VERSION 5.8 ;
BUSBITCHARS "[]" ;
DIVIDERCHAR "/" ;
UNITS
    DATABASE MICRONS 1000 ;
END UNITS

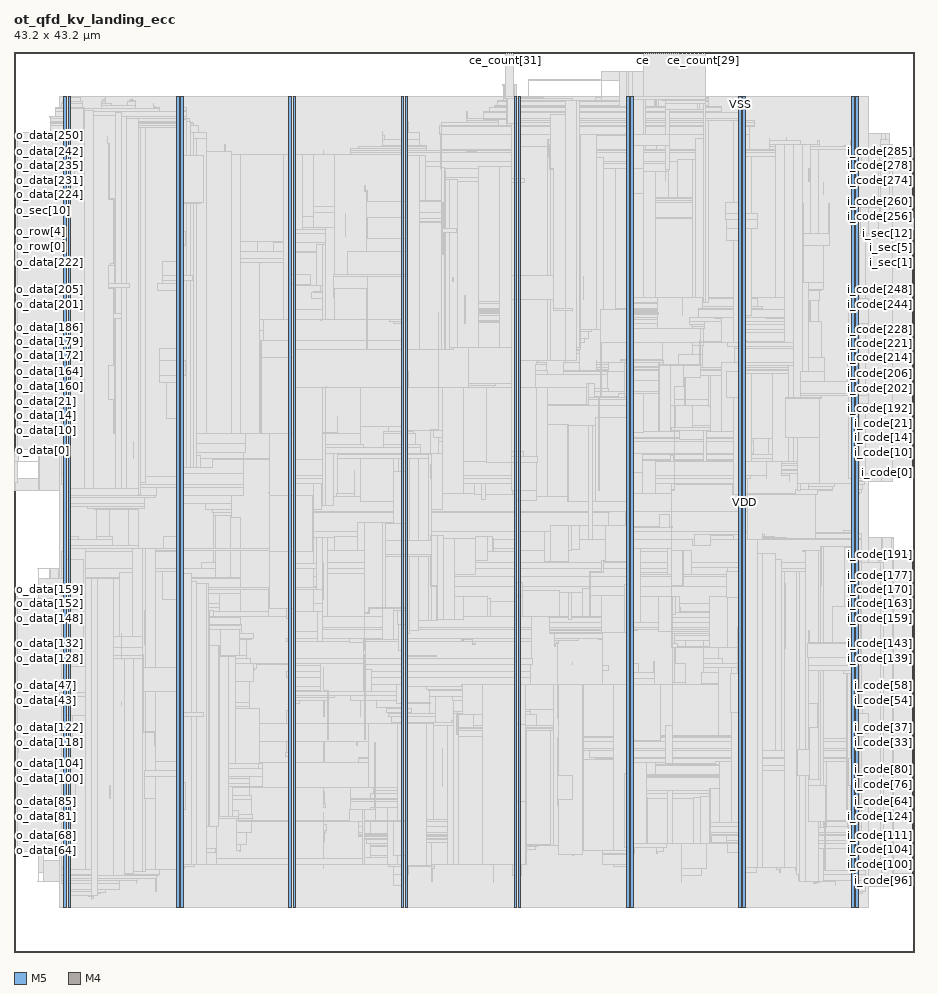
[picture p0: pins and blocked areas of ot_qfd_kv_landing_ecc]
MACRO ot_qfd_kv_landing_ecc
  FOREIGN ot_qfd_kv_landing_ecc 0 0 ;
  CLASS BLOCK ;
  SIZE 43.2 BY 43.2 ;
  PIN ce
    DIRECTION OUTPUT ;
    USE SIGNAL ;
    PORT
      LAYER M5 ;
        RECT  30.192 43.116 30.216 43.2 ;
    END
  END ce
  PIN ce_count[0]
    DIRECTION OUTPUT ;
    USE SIGNAL ;
    PORT
      LAYER M5 ;
        RECT  30.288 43.116 30.312 43.2 ;
    END
  END ce_count[0]
  PIN ce_count[10]
    DIRECTION OUTPUT ;
    USE SIGNAL ;
    PORT
      LAYER M5 ;
        RECT  31.248 43.116 31.272 43.2 ;
    END
  END ce_count[10]
  PIN ce_count[11]
    DIRECTION OUTPUT ;
    USE SIGNAL ;
    PORT
      LAYER M5 ;
        RECT  31.344 43.116 31.368 43.2 ;
    END
  END ce_count[11]
  PIN ce_count[12]
    DIRECTION OUTPUT ;
    USE SIGNAL ;
    PORT
      LAYER M5 ;
        RECT  31.44 43.116 31.464 43.2 ;
    END
  END ce_count[12]
  PIN ce_count[13]
    DIRECTION OUTPUT ;
    USE SIGNAL ;
    PORT
      LAYER M5 ;
        RECT  31.536 43.116 31.56 43.2 ;
    END
  END ce_count[13]
  PIN ce_count[14]
    DIRECTION OUTPUT ;
    USE SIGNAL ;
    PORT
      LAYER M5 ;
        RECT  31.632 43.116 31.656 43.2 ;
    END
  END ce_count[14]
  PIN ce_count[15]
    DIRECTION OUTPUT ;
    USE SIGNAL ;
    PORT
      LAYER M5 ;
        RECT  31.728 43.116 31.752 43.2 ;
    END
  END ce_count[15]
  PIN ce_count[16]
    DIRECTION OUTPUT ;
    USE SIGNAL ;
    PORT
      LAYER M5 ;
        RECT  31.824 43.116 31.848 43.2 ;
    END
  END ce_count[16]
  PIN ce_count[17]
    DIRECTION OUTPUT ;
    USE SIGNAL ;
    PORT
      LAYER M5 ;
        RECT  31.92 43.116 31.944 43.2 ;
    END
  END ce_count[17]
  PIN ce_count[18]
    DIRECTION OUTPUT ;
    USE SIGNAL ;
    PORT
      LAYER M5 ;
        RECT  32.016 43.116 32.04 43.2 ;
    END
  END ce_count[18]
  PIN ce_count[19]
    DIRECTION OUTPUT ;
    USE SIGNAL ;
    PORT
      LAYER M5 ;
        RECT  32.112 43.116 32.136 43.2 ;
    END
  END ce_count[19]
  PIN ce_count[1]
    DIRECTION OUTPUT ;
    USE SIGNAL ;
    PORT
      LAYER M5 ;
        RECT  30.384 43.116 30.408 43.2 ;
    END
  END ce_count[1]
  PIN ce_count[20]
    DIRECTION OUTPUT ;
    USE SIGNAL ;
    PORT
      LAYER M5 ;
        RECT  32.208 43.116 32.232 43.2 ;
    END
  END ce_count[20]
  PIN ce_count[21]
    DIRECTION OUTPUT ;
    USE SIGNAL ;
    PORT
      LAYER M5 ;
        RECT  32.304 43.116 32.328 43.2 ;
    END
  END ce_count[21]
  PIN ce_count[22]
    DIRECTION OUTPUT ;
    USE SIGNAL ;
    PORT
      LAYER M5 ;
        RECT  32.4 43.116 32.424 43.2 ;
    END
  END ce_count[22]
  PIN ce_count[23]
    DIRECTION OUTPUT ;
    USE SIGNAL ;
    PORT
      LAYER M5 ;
        RECT  32.496 43.116 32.52 43.2 ;
    END
  END ce_count[23]
  PIN ce_count[24]
    DIRECTION OUTPUT ;
    USE SIGNAL ;
    PORT
      LAYER M5 ;
        RECT  32.592 43.116 32.616 43.2 ;
    END
  END ce_count[24]
  PIN ce_count[25]
    DIRECTION OUTPUT ;
    USE SIGNAL ;
    PORT
      LAYER M5 ;
        RECT  32.688 43.116 32.712 43.2 ;
    END
  END ce_count[25]
  PIN ce_count[26]
    DIRECTION OUTPUT ;
    USE SIGNAL ;
    PORT
      LAYER M5 ;
        RECT  32.784 43.116 32.808 43.2 ;
    END
  END ce_count[26]
  PIN ce_count[27]
    DIRECTION OUTPUT ;
    USE SIGNAL ;
    PORT
      LAYER M5 ;
        RECT  32.88 43.116 32.904 43.2 ;
    END
  END ce_count[27]
  PIN ce_count[28]
    DIRECTION OUTPUT ;
    USE SIGNAL ;
    PORT
      LAYER M5 ;
        RECT  32.976 43.116 33 43.2 ;
    END
  END ce_count[28]
  PIN ce_count[29]
    DIRECTION OUTPUT ;
    USE SIGNAL ;
    PORT
      LAYER M5 ;
        RECT  33.072 43.116 33.096 43.2 ;
    END
  END ce_count[29]
  PIN ce_count[2]
    DIRECTION OUTPUT ;
    USE SIGNAL ;
    PORT
      LAYER M5 ;
        RECT  30.48 43.116 30.504 43.2 ;
    END
  END ce_count[2]
  PIN ce_count[30]
    DIRECTION OUTPUT ;
    USE SIGNAL ;
    PORT
      LAYER M5 ;
        RECT  33.168 43.116 33.192 43.2 ;
    END
  END ce_count[30]
  PIN ce_count[31]
    DIRECTION OUTPUT ;
    USE SIGNAL ;
    PORT
      LAYER M5 ;
        RECT  23.568 43.116 23.592 43.2 ;
    END
  END ce_count[31]
  PIN ce_count[3]
    DIRECTION OUTPUT ;
    USE SIGNAL ;
    PORT
      LAYER M5 ;
        RECT  30.576 43.116 30.6 43.2 ;
    END
  END ce_count[3]
  PIN ce_count[4]
    DIRECTION OUTPUT ;
    USE SIGNAL ;
    PORT
      LAYER M5 ;
        RECT  30.672 43.116 30.696 43.2 ;
    END
  END ce_count[4]
  PIN ce_count[5]
    DIRECTION OUTPUT ;
    USE SIGNAL ;
    PORT
      LAYER M5 ;
        RECT  30.768 43.116 30.792 43.2 ;
    END
  END ce_count[5]
  PIN ce_count[6]
    DIRECTION OUTPUT ;
    USE SIGNAL ;
    PORT
      LAYER M5 ;
        RECT  30.864 43.116 30.888 43.2 ;
    END
  END ce_count[6]
  PIN ce_count[7]
    DIRECTION OUTPUT ;
    USE SIGNAL ;
    PORT
      LAYER M5 ;
        RECT  30.96 43.116 30.984 43.2 ;
    END
  END ce_count[7]
  PIN ce_count[8]
    DIRECTION OUTPUT ;
    USE SIGNAL ;
    PORT
      LAYER M5 ;
        RECT  31.056 43.116 31.08 43.2 ;
    END
  END ce_count[8]
  PIN ce_count[9]
    DIRECTION OUTPUT ;
    USE SIGNAL ;
    PORT
      LAYER M5 ;
        RECT  31.152 43.116 31.176 43.2 ;
    END
  END ce_count[9]
  PIN fault
    DIRECTION OUTPUT ;
    USE SIGNAL ;
    PORT
      LAYER M5 ;
        RECT  23.664 43.116 23.688 43.2 ;
    END
  END fault
  PIN h_rst_n
    DIRECTION INPUT ;
    USE SIGNAL ;
    PORT
      LAYER M5 ;
        RECT  23.76 43.116 23.784 43.2 ;
    END
  END h_rst_n
  PIN hclk
    DIRECTION INPUT ;
    USE SIGNAL ;
    PORT
      LAYER M5 ;
        RECT  23.856 43.116 23.88 43.2 ;
    END
  END hclk
  PIN i_code[0]
    DIRECTION INPUT ;
    USE SIGNAL ;
    PORT
      LAYER M4 ;
        RECT  43.116 22.992 43.2 23.016 ;
    END
  END i_code[0]
  PIN i_code[100]
    DIRECTION INPUT ;
    USE SIGNAL ;
    PORT
      LAYER M4 ;
        RECT  43.116 4.176 43.2 4.2 ;
    END
  END i_code[100]
  PIN i_code[101]
    DIRECTION INPUT ;
    USE SIGNAL ;
    PORT
      LAYER M4 ;
        RECT  43.116 4.272 43.2 4.296 ;
    END
  END i_code[101]
  PIN i_code[102]
    DIRECTION INPUT ;
    USE SIGNAL ;
    PORT
      LAYER M4 ;
        RECT  43.116 4.368 43.2 4.392 ;
    END
  END i_code[102]
  PIN i_code[103]
    DIRECTION INPUT ;
    USE SIGNAL ;
    PORT
      LAYER M4 ;
        RECT  43.116 4.464 43.2 4.488 ;
    END
  END i_code[103]
  PIN i_code[104]
    DIRECTION INPUT ;
    USE SIGNAL ;
    PORT
      LAYER M4 ;
        RECT  43.116 4.56 43.2 4.584 ;
    END
  END i_code[104]
  PIN i_code[105]
    DIRECTION INPUT ;
    USE SIGNAL ;
    PORT
      LAYER M4 ;
        RECT  43.116 4.656 43.2 4.68 ;
    END
  END i_code[105]
  PIN i_code[106]
    DIRECTION INPUT ;
    USE SIGNAL ;
    PORT
      LAYER M4 ;
        RECT  43.116 4.752 43.2 4.776 ;
    END
  END i_code[106]
  PIN i_code[107]
    DIRECTION INPUT ;
    USE SIGNAL ;
    PORT
      LAYER M4 ;
        RECT  43.116 4.848 43.2 4.872 ;
    END
  END i_code[107]
  PIN i_code[108]
    DIRECTION INPUT ;
    USE SIGNAL ;
    PORT
      LAYER M4 ;
        RECT  43.116 4.944 43.2 4.968 ;
    END
  END i_code[108]
  PIN i_code[109]
    DIRECTION INPUT ;
    USE SIGNAL ;
    PORT
      LAYER M4 ;
        RECT  43.116 5.04 43.2 5.064 ;
    END
  END i_code[109]
  PIN i_code[10]
    DIRECTION INPUT ;
    USE SIGNAL ;
    PORT
      LAYER M4 ;
        RECT  43.116 23.952 43.2 23.976 ;
    END
  END i_code[10]
  PIN i_code[110]
    DIRECTION INPUT ;
    USE SIGNAL ;
    PORT
      LAYER M4 ;
        RECT  43.116 5.136 43.2 5.16 ;
    END
  END i_code[110]
  PIN i_code[111]
    DIRECTION INPUT ;
    USE SIGNAL ;
    PORT
      LAYER M4 ;
        RECT  43.116 5.232 43.2 5.256 ;
    END
  END i_code[111]
  PIN i_code[112]
    DIRECTION INPUT ;
    USE SIGNAL ;
    PORT
      LAYER M4 ;
        RECT  43.116 5.328 43.2 5.352 ;
    END
  END i_code[112]
  PIN i_code[113]
    DIRECTION INPUT ;
    USE SIGNAL ;
    PORT
      LAYER M4 ;
        RECT  43.116 5.424 43.2 5.448 ;
    END
  END i_code[113]
  PIN i_code[114]
    DIRECTION INPUT ;
    USE SIGNAL ;
    PORT
      LAYER M4 ;
        RECT  43.116 5.52 43.2 5.544 ;
    END
  END i_code[114]
  PIN i_code[115]
    DIRECTION INPUT ;
    USE SIGNAL ;
    PORT
      LAYER M4 ;
        RECT  43.116 5.616 43.2 5.64 ;
    END
  END i_code[115]
  PIN i_code[116]
    DIRECTION INPUT ;
    USE SIGNAL ;
    PORT
      LAYER M4 ;
        RECT  43.116 5.712 43.2 5.736 ;
    END
  END i_code[116]
  PIN i_code[117]
    DIRECTION INPUT ;
    USE SIGNAL ;
    PORT
      LAYER M4 ;
        RECT  43.116 5.808 43.2 5.832 ;
    END
  END i_code[117]
  PIN i_code[118]
    DIRECTION INPUT ;
    USE SIGNAL ;
    PORT
      LAYER M4 ;
        RECT  43.116 5.904 43.2 5.928 ;
    END
  END i_code[118]
  PIN i_code[119]
    DIRECTION INPUT ;
    USE SIGNAL ;
    PORT
      LAYER M4 ;
        RECT  43.116 6 43.2 6.024 ;
    END
  END i_code[119]
  PIN i_code[11]
    DIRECTION INPUT ;
    USE SIGNAL ;
    PORT
      LAYER M4 ;
        RECT  43.116 24.048 43.2 24.072 ;
    END
  END i_code[11]
  PIN i_code[120]
    DIRECTION INPUT ;
    USE SIGNAL ;
    PORT
      LAYER M4 ;
        RECT  43.116 6.096 43.2 6.12 ;
    END
  END i_code[120]
  PIN i_code[121]
    DIRECTION INPUT ;
    USE SIGNAL ;
    PORT
      LAYER M4 ;
        RECT  43.116 6.192 43.2 6.216 ;
    END
  END i_code[121]
  PIN i_code[122]
    DIRECTION INPUT ;
    USE SIGNAL ;
    PORT
      LAYER M4 ;
        RECT  43.116 6.288 43.2 6.312 ;
    END
  END i_code[122]
  PIN i_code[123]
    DIRECTION INPUT ;
    USE SIGNAL ;
    PORT
      LAYER M4 ;
        RECT  43.116 6.384 43.2 6.408 ;
    END
  END i_code[123]
  PIN i_code[124]
    DIRECTION INPUT ;
    USE SIGNAL ;
    PORT
      LAYER M4 ;
        RECT  43.116 6.48 43.2 6.504 ;
    END
  END i_code[124]
  PIN i_code[125]
    DIRECTION INPUT ;
    USE SIGNAL ;
    PORT
      LAYER M4 ;
        RECT  43.116 6.576 43.2 6.6 ;
    END
  END i_code[125]
  PIN i_code[126]
    DIRECTION INPUT ;
    USE SIGNAL ;
    PORT
      LAYER M4 ;
        RECT  43.116 6.672 43.2 6.696 ;
    END
  END i_code[126]
  PIN i_code[127]
    DIRECTION INPUT ;
    USE SIGNAL ;
    PORT
      LAYER M4 ;
        RECT  43.116 6.768 43.2 6.792 ;
    END
  END i_code[127]
  PIN i_code[128]
    DIRECTION INPUT ;
    USE SIGNAL ;
    PORT
      LAYER M4 ;
        RECT  43.116 13.008 43.2 13.032 ;
    END
  END i_code[128]
  PIN i_code[129]
    DIRECTION INPUT ;
    USE SIGNAL ;
    PORT
      LAYER M4 ;
        RECT  43.116 13.104 43.2 13.128 ;
    END
  END i_code[129]
  PIN i_code[12]
    DIRECTION INPUT ;
    USE SIGNAL ;
    PORT
      LAYER M4 ;
        RECT  43.116 24.144 43.2 24.168 ;
    END
  END i_code[12]
  PIN i_code[130]
    DIRECTION INPUT ;
    USE SIGNAL ;
    PORT
      LAYER M4 ;
        RECT  43.116 13.2 43.2 13.224 ;
    END
  END i_code[130]
  PIN i_code[131]
    DIRECTION INPUT ;
    USE SIGNAL ;
    PORT
      LAYER M4 ;
        RECT  43.116 13.296 43.2 13.32 ;
    END
  END i_code[131]
  PIN i_code[132]
    DIRECTION INPUT ;
    USE SIGNAL ;
    PORT
      LAYER M4 ;
        RECT  43.116 13.392 43.2 13.416 ;
    END
  END i_code[132]
  PIN i_code[133]
    DIRECTION INPUT ;
    USE SIGNAL ;
    PORT
      LAYER M4 ;
        RECT  43.116 13.488 43.2 13.512 ;
    END
  END i_code[133]
  PIN i_code[134]
    DIRECTION INPUT ;
    USE SIGNAL ;
    PORT
      LAYER M4 ;
        RECT  43.116 13.584 43.2 13.608 ;
    END
  END i_code[134]
  PIN i_code[135]
    DIRECTION INPUT ;
    USE SIGNAL ;
    PORT
      LAYER M4 ;
        RECT  43.116 13.68 43.2 13.704 ;
    END
  END i_code[135]
  PIN i_code[136]
    DIRECTION INPUT ;
    USE SIGNAL ;
    PORT
      LAYER M4 ;
        RECT  43.116 13.776 43.2 13.8 ;
    END
  END i_code[136]
  PIN i_code[137]
    DIRECTION INPUT ;
    USE SIGNAL ;
    PORT
      LAYER M4 ;
        RECT  43.116 13.872 43.2 13.896 ;
    END
  END i_code[137]
  PIN i_code[138]
    DIRECTION INPUT ;
    USE SIGNAL ;
    PORT
      LAYER M4 ;
        RECT  43.116 13.968 43.2 13.992 ;
    END
  END i_code[138]
  PIN i_code[139]
    DIRECTION INPUT ;
    USE SIGNAL ;
    PORT
      LAYER M4 ;
        RECT  43.116 14.064 43.2 14.088 ;
    END
  END i_code[139]
  PIN i_code[13]
    DIRECTION INPUT ;
    USE SIGNAL ;
    PORT
      LAYER M4 ;
        RECT  43.116 24.24 43.2 24.264 ;
    END
  END i_code[13]
  PIN i_code[140]
    DIRECTION INPUT ;
    USE SIGNAL ;
    PORT
      LAYER M4 ;
        RECT  43.116 14.16 43.2 14.184 ;
    END
  END i_code[140]
  PIN i_code[141]
    DIRECTION INPUT ;
    USE SIGNAL ;
    PORT
      LAYER M4 ;
        RECT  43.116 14.256 43.2 14.28 ;
    END
  END i_code[141]
  PIN i_code[142]
    DIRECTION INPUT ;
    USE SIGNAL ;
    PORT
      LAYER M4 ;
        RECT  43.116 14.352 43.2 14.376 ;
    END
  END i_code[142]
  PIN i_code[143]
    DIRECTION INPUT ;
    USE SIGNAL ;
    PORT
      LAYER M4 ;
        RECT  43.116 14.448 43.2 14.472 ;
    END
  END i_code[143]
  PIN i_code[144]
    DIRECTION INPUT ;
    USE SIGNAL ;
    PORT
      LAYER M4 ;
        RECT  43.116 14.544 43.2 14.568 ;
    END
  END i_code[144]
  PIN i_code[145]
    DIRECTION INPUT ;
    USE SIGNAL ;
    PORT
      LAYER M4 ;
        RECT  43.116 14.64 43.2 14.664 ;
    END
  END i_code[145]
  PIN i_code[146]
    DIRECTION INPUT ;
    USE SIGNAL ;
    PORT
      LAYER M4 ;
        RECT  43.116 14.736 43.2 14.76 ;
    END
  END i_code[146]
  PIN i_code[147]
    DIRECTION INPUT ;
    USE SIGNAL ;
    PORT
      LAYER M4 ;
        RECT  43.116 14.832 43.2 14.856 ;
    END
  END i_code[147]
  PIN i_code[148]
    DIRECTION INPUT ;
    USE SIGNAL ;
    PORT
      LAYER M4 ;
        RECT  43.116 14.928 43.2 14.952 ;
    END
  END i_code[148]
  PIN i_code[149]
    DIRECTION INPUT ;
    USE SIGNAL ;
    PORT
      LAYER M4 ;
        RECT  43.116 15.024 43.2 15.048 ;
    END
  END i_code[149]
  PIN i_code[14]
    DIRECTION INPUT ;
    USE SIGNAL ;
    PORT
      LAYER M4 ;
        RECT  43.116 24.336 43.2 24.36 ;
    END
  END i_code[14]
  PIN i_code[150]
    DIRECTION INPUT ;
    USE SIGNAL ;
    PORT
      LAYER M4 ;
        RECT  43.116 15.12 43.2 15.144 ;
    END
  END i_code[150]
  PIN i_code[151]
    DIRECTION INPUT ;
    USE SIGNAL ;
    PORT
      LAYER M4 ;
        RECT  43.116 15.216 43.2 15.24 ;
    END
  END i_code[151]
  PIN i_code[152]
    DIRECTION INPUT ;
    USE SIGNAL ;
    PORT
      LAYER M4 ;
        RECT  43.116 15.312 43.2 15.336 ;
    END
  END i_code[152]
  PIN i_code[153]
    DIRECTION INPUT ;
    USE SIGNAL ;
    PORT
      LAYER M4 ;
        RECT  43.116 15.408 43.2 15.432 ;
    END
  END i_code[153]
  PIN i_code[154]
    DIRECTION INPUT ;
    USE SIGNAL ;
    PORT
      LAYER M4 ;
        RECT  43.116 15.504 43.2 15.528 ;
    END
  END i_code[154]
  PIN i_code[155]
    DIRECTION INPUT ;
    USE SIGNAL ;
    PORT
      LAYER M4 ;
        RECT  43.116 15.6 43.2 15.624 ;
    END
  END i_code[155]
  PIN i_code[156]
    DIRECTION INPUT ;
    USE SIGNAL ;
    PORT
      LAYER M4 ;
        RECT  43.116 15.696 43.2 15.72 ;
    END
  END i_code[156]
  PIN i_code[157]
    DIRECTION INPUT ;
    USE SIGNAL ;
    PORT
      LAYER M4 ;
        RECT  43.116 15.792 43.2 15.816 ;
    END
  END i_code[157]
  PIN i_code[158]
    DIRECTION INPUT ;
    USE SIGNAL ;
    PORT
      LAYER M4 ;
        RECT  43.116 15.888 43.2 15.912 ;
    END
  END i_code[158]
  PIN i_code[159]
    DIRECTION INPUT ;
    USE SIGNAL ;
    PORT
      LAYER M4 ;
        RECT  43.116 15.984 43.2 16.008 ;
    END
  END i_code[159]
  PIN i_code[15]
    DIRECTION INPUT ;
    USE SIGNAL ;
    PORT
      LAYER M4 ;
        RECT  43.116 24.432 43.2 24.456 ;
    END
  END i_code[15]
  PIN i_code[160]
    DIRECTION INPUT ;
    USE SIGNAL ;
    PORT
      LAYER M4 ;
        RECT  43.116 16.08 43.2 16.104 ;
    END
  END i_code[160]
  PIN i_code[161]
    DIRECTION INPUT ;
    USE SIGNAL ;
    PORT
      LAYER M4 ;
        RECT  43.116 16.176 43.2 16.2 ;
    END
  END i_code[161]
  PIN i_code[162]
    DIRECTION INPUT ;
    USE SIGNAL ;
    PORT
      LAYER M4 ;
        RECT  43.116 16.272 43.2 16.296 ;
    END
  END i_code[162]
  PIN i_code[163]
    DIRECTION INPUT ;
    USE SIGNAL ;
    PORT
      LAYER M4 ;
        RECT  43.116 16.368 43.2 16.392 ;
    END
  END i_code[163]
  PIN i_code[164]
    DIRECTION INPUT ;
    USE SIGNAL ;
    PORT
      LAYER M4 ;
        RECT  43.116 16.464 43.2 16.488 ;
    END
  END i_code[164]
  PIN i_code[165]
    DIRECTION INPUT ;
    USE SIGNAL ;
    PORT
      LAYER M4 ;
        RECT  43.116 16.56 43.2 16.584 ;
    END
  END i_code[165]
  PIN i_code[166]
    DIRECTION INPUT ;
    USE SIGNAL ;
    PORT
      LAYER M4 ;
        RECT  43.116 16.656 43.2 16.68 ;
    END
  END i_code[166]
  PIN i_code[167]
    DIRECTION INPUT ;
    USE SIGNAL ;
    PORT
      LAYER M4 ;
        RECT  43.116 16.752 43.2 16.776 ;
    END
  END i_code[167]
  PIN i_code[168]
    DIRECTION INPUT ;
    USE SIGNAL ;
    PORT
      LAYER M4 ;
        RECT  43.116 16.848 43.2 16.872 ;
    END
  END i_code[168]
  PIN i_code[169]
    DIRECTION INPUT ;
    USE SIGNAL ;
    PORT
      LAYER M4 ;
        RECT  43.116 16.944 43.2 16.968 ;
    END
  END i_code[169]
  PIN i_code[16]
    DIRECTION INPUT ;
    USE SIGNAL ;
    PORT
      LAYER M4 ;
        RECT  43.116 24.528 43.2 24.552 ;
    END
  END i_code[16]
  PIN i_code[170]
    DIRECTION INPUT ;
    USE SIGNAL ;
    PORT
      LAYER M4 ;
        RECT  43.116 17.04 43.2 17.064 ;
    END
  END i_code[170]
  PIN i_code[171]
    DIRECTION INPUT ;
    USE SIGNAL ;
    PORT
      LAYER M4 ;
        RECT  43.116 17.136 43.2 17.16 ;
    END
  END i_code[171]
  PIN i_code[172]
    DIRECTION INPUT ;
    USE SIGNAL ;
    PORT
      LAYER M4 ;
        RECT  43.116 17.232 43.2 17.256 ;
    END
  END i_code[172]
  PIN i_code[173]
    DIRECTION INPUT ;
    USE SIGNAL ;
    PORT
      LAYER M4 ;
        RECT  43.116 17.328 43.2 17.352 ;
    END
  END i_code[173]
  PIN i_code[174]
    DIRECTION INPUT ;
    USE SIGNAL ;
    PORT
      LAYER M4 ;
        RECT  43.116 17.424 43.2 17.448 ;
    END
  END i_code[174]
  PIN i_code[175]
    DIRECTION INPUT ;
    USE SIGNAL ;
    PORT
      LAYER M4 ;
        RECT  43.116 17.52 43.2 17.544 ;
    END
  END i_code[175]
  PIN i_code[176]
    DIRECTION INPUT ;
    USE SIGNAL ;
    PORT
      LAYER M4 ;
        RECT  43.116 17.616 43.2 17.64 ;
    END
  END i_code[176]
  PIN i_code[177]
    DIRECTION INPUT ;
    USE SIGNAL ;
    PORT
      LAYER M4 ;
        RECT  43.116 17.712 43.2 17.736 ;
    END
  END i_code[177]
  PIN i_code[178]
    DIRECTION INPUT ;
    USE SIGNAL ;
    PORT
      LAYER M4 ;
        RECT  43.116 17.808 43.2 17.832 ;
    END
  END i_code[178]
  PIN i_code[179]
    DIRECTION INPUT ;
    USE SIGNAL ;
    PORT
      LAYER M4 ;
        RECT  43.116 17.904 43.2 17.928 ;
    END
  END i_code[179]
  PIN i_code[17]
    DIRECTION INPUT ;
    USE SIGNAL ;
    PORT
      LAYER M4 ;
        RECT  43.116 24.624 43.2 24.648 ;
    END
  END i_code[17]
  PIN i_code[180]
    DIRECTION INPUT ;
    USE SIGNAL ;
    PORT
      LAYER M4 ;
        RECT  43.116 18 43.2 18.024 ;
    END
  END i_code[180]
  PIN i_code[181]
    DIRECTION INPUT ;
    USE SIGNAL ;
    PORT
      LAYER M4 ;
        RECT  43.116 18.096 43.2 18.12 ;
    END
  END i_code[181]
  PIN i_code[182]
    DIRECTION INPUT ;
    USE SIGNAL ;
    PORT
      LAYER M4 ;
        RECT  43.116 18.192 43.2 18.216 ;
    END
  END i_code[182]
  PIN i_code[183]
    DIRECTION INPUT ;
    USE SIGNAL ;
    PORT
      LAYER M4 ;
        RECT  43.116 18.288 43.2 18.312 ;
    END
  END i_code[183]
  PIN i_code[184]
    DIRECTION INPUT ;
    USE SIGNAL ;
    PORT
      LAYER M4 ;
        RECT  43.116 18.384 43.2 18.408 ;
    END
  END i_code[184]
  PIN i_code[185]
    DIRECTION INPUT ;
    USE SIGNAL ;
    PORT
      LAYER M4 ;
        RECT  43.116 18.48 43.2 18.504 ;
    END
  END i_code[185]
  PIN i_code[186]
    DIRECTION INPUT ;
    USE SIGNAL ;
    PORT
      LAYER M4 ;
        RECT  43.116 18.576 43.2 18.6 ;
    END
  END i_code[186]
  PIN i_code[187]
    DIRECTION INPUT ;
    USE SIGNAL ;
    PORT
      LAYER M4 ;
        RECT  43.116 18.672 43.2 18.696 ;
    END
  END i_code[187]
  PIN i_code[188]
    DIRECTION INPUT ;
    USE SIGNAL ;
    PORT
      LAYER M4 ;
        RECT  43.116 18.768 43.2 18.792 ;
    END
  END i_code[188]
  PIN i_code[189]
    DIRECTION INPUT ;
    USE SIGNAL ;
    PORT
      LAYER M4 ;
        RECT  43.116 18.864 43.2 18.888 ;
    END
  END i_code[189]
  PIN i_code[18]
    DIRECTION INPUT ;
    USE SIGNAL ;
    PORT
      LAYER M4 ;
        RECT  43.116 24.72 43.2 24.744 ;
    END
  END i_code[18]
  PIN i_code[190]
    DIRECTION INPUT ;
    USE SIGNAL ;
    PORT
      LAYER M4 ;
        RECT  43.116 18.96 43.2 18.984 ;
    END
  END i_code[190]
  PIN i_code[191]
    DIRECTION INPUT ;
    USE SIGNAL ;
    PORT
      LAYER M4 ;
        RECT  43.116 19.056 43.2 19.08 ;
    END
  END i_code[191]
  PIN i_code[192]
    DIRECTION INPUT ;
    USE SIGNAL ;
    PORT
      LAYER M4 ;
        RECT  43.116 26.064 43.2 26.088 ;
    END
  END i_code[192]
  PIN i_code[193]
    DIRECTION INPUT ;
    USE SIGNAL ;
    PORT
      LAYER M4 ;
        RECT  43.116 26.16 43.2 26.184 ;
    END
  END i_code[193]
  PIN i_code[194]
    DIRECTION INPUT ;
    USE SIGNAL ;
    PORT
      LAYER M4 ;
        RECT  43.116 26.256 43.2 26.28 ;
    END
  END i_code[194]
  PIN i_code[195]
    DIRECTION INPUT ;
    USE SIGNAL ;
    PORT
      LAYER M4 ;
        RECT  43.116 26.352 43.2 26.376 ;
    END
  END i_code[195]
  PIN i_code[196]
    DIRECTION INPUT ;
    USE SIGNAL ;
    PORT
      LAYER M4 ;
        RECT  43.116 26.448 43.2 26.472 ;
    END
  END i_code[196]
  PIN i_code[197]
    DIRECTION INPUT ;
    USE SIGNAL ;
    PORT
      LAYER M4 ;
        RECT  43.116 26.544 43.2 26.568 ;
    END
  END i_code[197]
  PIN i_code[198]
    DIRECTION INPUT ;
    USE SIGNAL ;
    PORT
      LAYER M4 ;
        RECT  43.116 26.64 43.2 26.664 ;
    END
  END i_code[198]
  PIN i_code[199]
    DIRECTION INPUT ;
    USE SIGNAL ;
    PORT
      LAYER M4 ;
        RECT  43.116 26.736 43.2 26.76 ;
    END
  END i_code[199]
  PIN i_code[19]
    DIRECTION INPUT ;
    USE SIGNAL ;
    PORT
      LAYER M4 ;
        RECT  43.116 24.816 43.2 24.84 ;
    END
  END i_code[19]
  PIN i_code[1]
    DIRECTION INPUT ;
    USE SIGNAL ;
    PORT
      LAYER M4 ;
        RECT  43.116 23.088 43.2 23.112 ;
    END
  END i_code[1]
  PIN i_code[200]
    DIRECTION INPUT ;
    USE SIGNAL ;
    PORT
      LAYER M4 ;
        RECT  43.116 26.832 43.2 26.856 ;
    END
  END i_code[200]
  PIN i_code[201]
    DIRECTION INPUT ;
    USE SIGNAL ;
    PORT
      LAYER M4 ;
        RECT  43.116 26.928 43.2 26.952 ;
    END
  END i_code[201]
  PIN i_code[202]
    DIRECTION INPUT ;
    USE SIGNAL ;
    PORT
      LAYER M4 ;
        RECT  43.116 27.024 43.2 27.048 ;
    END
  END i_code[202]
  PIN i_code[203]
    DIRECTION INPUT ;
    USE SIGNAL ;
    PORT
      LAYER M4 ;
        RECT  43.116 27.12 43.2 27.144 ;
    END
  END i_code[203]
  PIN i_code[204]
    DIRECTION INPUT ;
    USE SIGNAL ;
    PORT
      LAYER M4 ;
        RECT  43.116 27.216 43.2 27.24 ;
    END
  END i_code[204]
  PIN i_code[205]
    DIRECTION INPUT ;
    USE SIGNAL ;
    PORT
      LAYER M4 ;
        RECT  43.116 27.312 43.2 27.336 ;
    END
  END i_code[205]
  PIN i_code[206]
    DIRECTION INPUT ;
    USE SIGNAL ;
    PORT
      LAYER M4 ;
        RECT  43.116 27.408 43.2 27.432 ;
    END
  END i_code[206]
  PIN i_code[207]
    DIRECTION INPUT ;
    USE SIGNAL ;
    PORT
      LAYER M4 ;
        RECT  43.116 27.504 43.2 27.528 ;
    END
  END i_code[207]
  PIN i_code[208]
    DIRECTION INPUT ;
    USE SIGNAL ;
    PORT
      LAYER M4 ;
        RECT  43.116 27.6 43.2 27.624 ;
    END
  END i_code[208]
  PIN i_code[209]
    DIRECTION INPUT ;
    USE SIGNAL ;
    PORT
      LAYER M4 ;
        RECT  43.116 27.696 43.2 27.72 ;
    END
  END i_code[209]
  PIN i_code[20]
    DIRECTION INPUT ;
    USE SIGNAL ;
    PORT
      LAYER M4 ;
        RECT  43.116 24.912 43.2 24.936 ;
    END
  END i_code[20]
  PIN i_code[210]
    DIRECTION INPUT ;
    USE SIGNAL ;
    PORT
      LAYER M4 ;
        RECT  43.116 27.792 43.2 27.816 ;
    END
  END i_code[210]
  PIN i_code[211]
    DIRECTION INPUT ;
    USE SIGNAL ;
    PORT
      LAYER M4 ;
        RECT  43.116 27.888 43.2 27.912 ;
    END
  END i_code[211]
  PIN i_code[212]
    DIRECTION INPUT ;
    USE SIGNAL ;
    PORT
      LAYER M4 ;
        RECT  43.116 27.984 43.2 28.008 ;
    END
  END i_code[212]
  PIN i_code[213]
    DIRECTION INPUT ;
    USE SIGNAL ;
    PORT
      LAYER M4 ;
        RECT  43.116 28.08 43.2 28.104 ;
    END
  END i_code[213]
  PIN i_code[214]
    DIRECTION INPUT ;
    USE SIGNAL ;
    PORT
      LAYER M4 ;
        RECT  43.116 28.176 43.2 28.2 ;
    END
  END i_code[214]
  PIN i_code[215]
    DIRECTION INPUT ;
    USE SIGNAL ;
    PORT
      LAYER M4 ;
        RECT  43.116 28.272 43.2 28.296 ;
    END
  END i_code[215]
  PIN i_code[216]
    DIRECTION INPUT ;
    USE SIGNAL ;
    PORT
      LAYER M4 ;
        RECT  43.116 28.368 43.2 28.392 ;
    END
  END i_code[216]
  PIN i_code[217]
    DIRECTION INPUT ;
    USE SIGNAL ;
    PORT
      LAYER M4 ;
        RECT  43.116 28.464 43.2 28.488 ;
    END
  END i_code[217]
  PIN i_code[218]
    DIRECTION INPUT ;
    USE SIGNAL ;
    PORT
      LAYER M4 ;
        RECT  43.116 28.56 43.2 28.584 ;
    END
  END i_code[218]
  PIN i_code[219]
    DIRECTION INPUT ;
    USE SIGNAL ;
    PORT
      LAYER M4 ;
        RECT  43.116 28.656 43.2 28.68 ;
    END
  END i_code[219]
  PIN i_code[21]
    DIRECTION INPUT ;
    USE SIGNAL ;
    PORT
      LAYER M4 ;
        RECT  43.116 25.008 43.2 25.032 ;
    END
  END i_code[21]
  PIN i_code[220]
    DIRECTION INPUT ;
    USE SIGNAL ;
    PORT
      LAYER M4 ;
        RECT  43.116 28.752 43.2 28.776 ;
    END
  END i_code[220]
  PIN i_code[221]
    DIRECTION INPUT ;
    USE SIGNAL ;
    PORT
      LAYER M4 ;
        RECT  43.116 28.848 43.2 28.872 ;
    END
  END i_code[221]
  PIN i_code[222]
    DIRECTION INPUT ;
    USE SIGNAL ;
    PORT
      LAYER M4 ;
        RECT  43.116 28.944 43.2 28.968 ;
    END
  END i_code[222]
  PIN i_code[223]
    DIRECTION INPUT ;
    USE SIGNAL ;
    PORT
      LAYER M4 ;
        RECT  43.116 29.04 43.2 29.064 ;
    END
  END i_code[223]
  PIN i_code[224]
    DIRECTION INPUT ;
    USE SIGNAL ;
    PORT
      LAYER M4 ;
        RECT  43.116 29.136 43.2 29.16 ;
    END
  END i_code[224]
  PIN i_code[225]
    DIRECTION INPUT ;
    USE SIGNAL ;
    PORT
      LAYER M4 ;
        RECT  43.116 29.232 43.2 29.256 ;
    END
  END i_code[225]
  PIN i_code[226]
    DIRECTION INPUT ;
    USE SIGNAL ;
    PORT
      LAYER M4 ;
        RECT  43.116 29.328 43.2 29.352 ;
    END
  END i_code[226]
  PIN i_code[227]
    DIRECTION INPUT ;
    USE SIGNAL ;
    PORT
      LAYER M4 ;
        RECT  43.116 29.424 43.2 29.448 ;
    END
  END i_code[227]
  PIN i_code[228]
    DIRECTION INPUT ;
    USE SIGNAL ;
    PORT
      LAYER M4 ;
        RECT  43.116 29.52 43.2 29.544 ;
    END
  END i_code[228]
  PIN i_code[229]
    DIRECTION INPUT ;
    USE SIGNAL ;
    PORT
      LAYER M4 ;
        RECT  43.116 29.616 43.2 29.64 ;
    END
  END i_code[229]
  PIN i_code[22]
    DIRECTION INPUT ;
    USE SIGNAL ;
    PORT
      LAYER M4 ;
        RECT  43.116 25.104 43.2 25.128 ;
    END
  END i_code[22]
  PIN i_code[230]
    DIRECTION INPUT ;
    USE SIGNAL ;
    PORT
      LAYER M4 ;
        RECT  43.116 29.712 43.2 29.736 ;
    END
  END i_code[230]
  PIN i_code[231]
    DIRECTION INPUT ;
    USE SIGNAL ;
    PORT
      LAYER M4 ;
        RECT  43.116 29.808 43.2 29.832 ;
    END
  END i_code[231]
  PIN i_code[232]
    DIRECTION INPUT ;
    USE SIGNAL ;
    PORT
      LAYER M4 ;
        RECT  43.116 29.904 43.2 29.928 ;
    END
  END i_code[232]
  PIN i_code[233]
    DIRECTION INPUT ;
    USE SIGNAL ;
    PORT
      LAYER M4 ;
        RECT  43.116 30 43.2 30.024 ;
    END
  END i_code[233]
  PIN i_code[234]
    DIRECTION INPUT ;
    USE SIGNAL ;
    PORT
      LAYER M4 ;
        RECT  43.116 30.096 43.2 30.12 ;
    END
  END i_code[234]
  PIN i_code[235]
    DIRECTION INPUT ;
    USE SIGNAL ;
    PORT
      LAYER M4 ;
        RECT  43.116 30.192 43.2 30.216 ;
    END
  END i_code[235]
  PIN i_code[236]
    DIRECTION INPUT ;
    USE SIGNAL ;
    PORT
      LAYER M4 ;
        RECT  43.116 30.288 43.2 30.312 ;
    END
  END i_code[236]
  PIN i_code[237]
    DIRECTION INPUT ;
    USE SIGNAL ;
    PORT
      LAYER M4 ;
        RECT  43.116 30.384 43.2 30.408 ;
    END
  END i_code[237]
  PIN i_code[238]
    DIRECTION INPUT ;
    USE SIGNAL ;
    PORT
      LAYER M4 ;
        RECT  43.116 30.48 43.2 30.504 ;
    END
  END i_code[238]
  PIN i_code[239]
    DIRECTION INPUT ;
    USE SIGNAL ;
    PORT
      LAYER M4 ;
        RECT  43.116 30.576 43.2 30.6 ;
    END
  END i_code[239]
  PIN i_code[23]
    DIRECTION INPUT ;
    USE SIGNAL ;
    PORT
      LAYER M4 ;
        RECT  43.116 25.2 43.2 25.224 ;
    END
  END i_code[23]
  PIN i_code[240]
    DIRECTION INPUT ;
    USE SIGNAL ;
    PORT
      LAYER M4 ;
        RECT  43.116 30.672 43.2 30.696 ;
    END
  END i_code[240]
  PIN i_code[241]
    DIRECTION INPUT ;
    USE SIGNAL ;
    PORT
      LAYER M4 ;
        RECT  43.116 30.768 43.2 30.792 ;
    END
  END i_code[241]
  PIN i_code[242]
    DIRECTION INPUT ;
    USE SIGNAL ;
    PORT
      LAYER M4 ;
        RECT  43.116 30.864 43.2 30.888 ;
    END
  END i_code[242]
  PIN i_code[243]
    DIRECTION INPUT ;
    USE SIGNAL ;
    PORT
      LAYER M4 ;
        RECT  43.116 30.96 43.2 30.984 ;
    END
  END i_code[243]
  PIN i_code[244]
    DIRECTION INPUT ;
    USE SIGNAL ;
    PORT
      LAYER M4 ;
        RECT  43.116 31.056 43.2 31.08 ;
    END
  END i_code[244]
  PIN i_code[245]
    DIRECTION INPUT ;
    USE SIGNAL ;
    PORT
      LAYER M4 ;
        RECT  43.116 31.152 43.2 31.176 ;
    END
  END i_code[245]
  PIN i_code[246]
    DIRECTION INPUT ;
    USE SIGNAL ;
    PORT
      LAYER M4 ;
        RECT  43.116 31.248 43.2 31.272 ;
    END
  END i_code[246]
  PIN i_code[247]
    DIRECTION INPUT ;
    USE SIGNAL ;
    PORT
      LAYER M4 ;
        RECT  43.116 31.344 43.2 31.368 ;
    END
  END i_code[247]
  PIN i_code[248]
    DIRECTION INPUT ;
    USE SIGNAL ;
    PORT
      LAYER M4 ;
        RECT  43.116 31.44 43.2 31.464 ;
    END
  END i_code[248]
  PIN i_code[249]
    DIRECTION INPUT ;
    USE SIGNAL ;
    PORT
      LAYER M4 ;
        RECT  43.116 31.536 43.2 31.56 ;
    END
  END i_code[249]
  PIN i_code[24]
    DIRECTION INPUT ;
    USE SIGNAL ;
    PORT
      LAYER M4 ;
        RECT  43.116 25.296 43.2 25.32 ;
    END
  END i_code[24]
  PIN i_code[250]
    DIRECTION INPUT ;
    USE SIGNAL ;
    PORT
      LAYER M4 ;
        RECT  43.116 31.632 43.2 31.656 ;
    END
  END i_code[250]
  PIN i_code[251]
    DIRECTION INPUT ;
    USE SIGNAL ;
    PORT
      LAYER M4 ;
        RECT  43.116 31.728 43.2 31.752 ;
    END
  END i_code[251]
  PIN i_code[252]
    DIRECTION INPUT ;
    USE SIGNAL ;
    PORT
      LAYER M4 ;
        RECT  43.116 31.824 43.2 31.848 ;
    END
  END i_code[252]
  PIN i_code[253]
    DIRECTION INPUT ;
    USE SIGNAL ;
    PORT
      LAYER M4 ;
        RECT  43.116 31.92 43.2 31.944 ;
    END
  END i_code[253]
  PIN i_code[254]
    DIRECTION INPUT ;
    USE SIGNAL ;
    PORT
      LAYER M4 ;
        RECT  43.116 32.016 43.2 32.04 ;
    END
  END i_code[254]
  PIN i_code[255]
    DIRECTION INPUT ;
    USE SIGNAL ;
    PORT
      LAYER M4 ;
        RECT  43.116 32.112 43.2 32.136 ;
    END
  END i_code[255]
  PIN i_code[256]
    DIRECTION INPUT ;
    USE SIGNAL ;
    PORT
      LAYER M4 ;
        RECT  43.116 35.28 43.2 35.304 ;
    END
  END i_code[256]
  PIN i_code[257]
    DIRECTION INPUT ;
    USE SIGNAL ;
    PORT
      LAYER M4 ;
        RECT  43.116 35.376 43.2 35.4 ;
    END
  END i_code[257]
  PIN i_code[258]
    DIRECTION INPUT ;
    USE SIGNAL ;
    PORT
      LAYER M4 ;
        RECT  43.116 35.472 43.2 35.496 ;
    END
  END i_code[258]
  PIN i_code[259]
    DIRECTION INPUT ;
    USE SIGNAL ;
    PORT
      LAYER M4 ;
        RECT  43.116 35.568 43.2 35.592 ;
    END
  END i_code[259]
  PIN i_code[25]
    DIRECTION INPUT ;
    USE SIGNAL ;
    PORT
      LAYER M4 ;
        RECT  43.116 25.392 43.2 25.416 ;
    END
  END i_code[25]
  PIN i_code[260]
    DIRECTION INPUT ;
    USE SIGNAL ;
    PORT
      LAYER M4 ;
        RECT  43.116 35.664 43.2 35.688 ;
    END
  END i_code[260]
  PIN i_code[261]
    DIRECTION INPUT ;
    USE SIGNAL ;
    PORT
      LAYER M4 ;
        RECT  43.116 35.76 43.2 35.784 ;
    END
  END i_code[261]
  PIN i_code[262]
    DIRECTION INPUT ;
    USE SIGNAL ;
    PORT
      LAYER M4 ;
        RECT  43.116 35.856 43.2 35.88 ;
    END
  END i_code[262]
  PIN i_code[263]
    DIRECTION INPUT ;
    USE SIGNAL ;
    PORT
      LAYER M4 ;
        RECT  43.116 35.952 43.2 35.976 ;
    END
  END i_code[263]
  PIN i_code[264]
    DIRECTION INPUT ;
    USE SIGNAL ;
    PORT
      LAYER M4 ;
        RECT  43.116 36.048 43.2 36.072 ;
    END
  END i_code[264]
  PIN i_code[265]
    DIRECTION INPUT ;
    USE SIGNAL ;
    PORT
      LAYER M4 ;
        RECT  43.116 36.144 43.2 36.168 ;
    END
  END i_code[265]
  PIN i_code[266]
    DIRECTION INPUT ;
    USE SIGNAL ;
    PORT
      LAYER M4 ;
        RECT  43.116 36.24 43.2 36.264 ;
    END
  END i_code[266]
  PIN i_code[267]
    DIRECTION INPUT ;
    USE SIGNAL ;
    PORT
      LAYER M4 ;
        RECT  43.116 36.336 43.2 36.36 ;
    END
  END i_code[267]
  PIN i_code[268]
    DIRECTION INPUT ;
    USE SIGNAL ;
    PORT
      LAYER M4 ;
        RECT  43.116 36.432 43.2 36.456 ;
    END
  END i_code[268]
  PIN i_code[269]
    DIRECTION INPUT ;
    USE SIGNAL ;
    PORT
      LAYER M4 ;
        RECT  43.116 36.528 43.2 36.552 ;
    END
  END i_code[269]
  PIN i_code[26]
    DIRECTION INPUT ;
    USE SIGNAL ;
    PORT
      LAYER M4 ;
        RECT  43.116 25.488 43.2 25.512 ;
    END
  END i_code[26]
  PIN i_code[270]
    DIRECTION INPUT ;
    USE SIGNAL ;
    PORT
      LAYER M4 ;
        RECT  43.116 36.624 43.2 36.648 ;
    END
  END i_code[270]
  PIN i_code[271]
    DIRECTION INPUT ;
    USE SIGNAL ;
    PORT
      LAYER M4 ;
        RECT  43.116 36.72 43.2 36.744 ;
    END
  END i_code[271]
  PIN i_code[272]
    DIRECTION INPUT ;
    USE SIGNAL ;
    PORT
      LAYER M4 ;
        RECT  43.116 36.816 43.2 36.84 ;
    END
  END i_code[272]
  PIN i_code[273]
    DIRECTION INPUT ;
    USE SIGNAL ;
    PORT
      LAYER M4 ;
        RECT  43.116 36.912 43.2 36.936 ;
    END
  END i_code[273]
  PIN i_code[274]
    DIRECTION INPUT ;
    USE SIGNAL ;
    PORT
      LAYER M4 ;
        RECT  43.116 37.008 43.2 37.032 ;
    END
  END i_code[274]
  PIN i_code[275]
    DIRECTION INPUT ;
    USE SIGNAL ;
    PORT
      LAYER M4 ;
        RECT  43.116 37.104 43.2 37.128 ;
    END
  END i_code[275]
  PIN i_code[276]
    DIRECTION INPUT ;
    USE SIGNAL ;
    PORT
      LAYER M4 ;
        RECT  43.116 37.2 43.2 37.224 ;
    END
  END i_code[276]
  PIN i_code[277]
    DIRECTION INPUT ;
    USE SIGNAL ;
    PORT
      LAYER M4 ;
        RECT  43.116 37.296 43.2 37.32 ;
    END
  END i_code[277]
  PIN i_code[278]
    DIRECTION INPUT ;
    USE SIGNAL ;
    PORT
      LAYER M4 ;
        RECT  43.116 37.392 43.2 37.416 ;
    END
  END i_code[278]
  PIN i_code[279]
    DIRECTION INPUT ;
    USE SIGNAL ;
    PORT
      LAYER M4 ;
        RECT  43.116 37.488 43.2 37.512 ;
    END
  END i_code[279]
  PIN i_code[27]
    DIRECTION INPUT ;
    USE SIGNAL ;
    PORT
      LAYER M4 ;
        RECT  43.116 25.584 43.2 25.608 ;
    END
  END i_code[27]
  PIN i_code[280]
    DIRECTION INPUT ;
    USE SIGNAL ;
    PORT
      LAYER M4 ;
        RECT  43.116 37.584 43.2 37.608 ;
    END
  END i_code[280]
  PIN i_code[281]
    DIRECTION INPUT ;
    USE SIGNAL ;
    PORT
      LAYER M4 ;
        RECT  43.116 37.68 43.2 37.704 ;
    END
  END i_code[281]
  PIN i_code[282]
    DIRECTION INPUT ;
    USE SIGNAL ;
    PORT
      LAYER M4 ;
        RECT  43.116 37.776 43.2 37.8 ;
    END
  END i_code[282]
  PIN i_code[283]
    DIRECTION INPUT ;
    USE SIGNAL ;
    PORT
      LAYER M4 ;
        RECT  43.116 37.872 43.2 37.896 ;
    END
  END i_code[283]
  PIN i_code[284]
    DIRECTION INPUT ;
    USE SIGNAL ;
    PORT
      LAYER M4 ;
        RECT  43.116 37.968 43.2 37.992 ;
    END
  END i_code[284]
  PIN i_code[285]
    DIRECTION INPUT ;
    USE SIGNAL ;
    PORT
      LAYER M4 ;
        RECT  43.116 38.064 43.2 38.088 ;
    END
  END i_code[285]
  PIN i_code[286]
    DIRECTION INPUT ;
    USE SIGNAL ;
    PORT
      LAYER M4 ;
        RECT  43.116 38.16 43.2 38.184 ;
    END
  END i_code[286]
  PIN i_code[287]
    DIRECTION INPUT ;
    USE SIGNAL ;
    PORT
      LAYER M4 ;
        RECT  43.116 38.256 43.2 38.28 ;
    END
  END i_code[287]
  PIN i_code[28]
    DIRECTION INPUT ;
    USE SIGNAL ;
    PORT
      LAYER M4 ;
        RECT  43.116 25.68 43.2 25.704 ;
    END
  END i_code[28]
  PIN i_code[29]
    DIRECTION INPUT ;
    USE SIGNAL ;
    PORT
      LAYER M4 ;
        RECT  43.116 25.776 43.2 25.8 ;
    END
  END i_code[29]
  PIN i_code[2]
    DIRECTION INPUT ;
    USE SIGNAL ;
    PORT
      LAYER M4 ;
        RECT  43.116 23.184 43.2 23.208 ;
    END
  END i_code[2]
  PIN i_code[30]
    DIRECTION INPUT ;
    USE SIGNAL ;
    PORT
      LAYER M4 ;
        RECT  43.116 25.872 43.2 25.896 ;
    END
  END i_code[30]
  PIN i_code[31]
    DIRECTION INPUT ;
    USE SIGNAL ;
    PORT
      LAYER M4 ;
        RECT  43.116 25.968 43.2 25.992 ;
    END
  END i_code[31]
  PIN i_code[32]
    DIRECTION INPUT ;
    USE SIGNAL ;
    PORT
      LAYER M4 ;
        RECT  43.116 9.936 43.2 9.96 ;
    END
  END i_code[32]
  PIN i_code[33]
    DIRECTION INPUT ;
    USE SIGNAL ;
    PORT
      LAYER M4 ;
        RECT  43.116 10.032 43.2 10.056 ;
    END
  END i_code[33]
  PIN i_code[34]
    DIRECTION INPUT ;
    USE SIGNAL ;
    PORT
      LAYER M4 ;
        RECT  43.116 10.128 43.2 10.152 ;
    END
  END i_code[34]
  PIN i_code[35]
    DIRECTION INPUT ;
    USE SIGNAL ;
    PORT
      LAYER M4 ;
        RECT  43.116 10.224 43.2 10.248 ;
    END
  END i_code[35]
  PIN i_code[36]
    DIRECTION INPUT ;
    USE SIGNAL ;
    PORT
      LAYER M4 ;
        RECT  43.116 10.32 43.2 10.344 ;
    END
  END i_code[36]
  PIN i_code[37]
    DIRECTION INPUT ;
    USE SIGNAL ;
    PORT
      LAYER M4 ;
        RECT  43.116 10.416 43.2 10.44 ;
    END
  END i_code[37]
  PIN i_code[38]
    DIRECTION INPUT ;
    USE SIGNAL ;
    PORT
      LAYER M4 ;
        RECT  43.116 10.512 43.2 10.536 ;
    END
  END i_code[38]
  PIN i_code[39]
    DIRECTION INPUT ;
    USE SIGNAL ;
    PORT
      LAYER M4 ;
        RECT  43.116 10.608 43.2 10.632 ;
    END
  END i_code[39]
  PIN i_code[3]
    DIRECTION INPUT ;
    USE SIGNAL ;
    PORT
      LAYER M4 ;
        RECT  43.116 23.28 43.2 23.304 ;
    END
  END i_code[3]
  PIN i_code[40]
    DIRECTION INPUT ;
    USE SIGNAL ;
    PORT
      LAYER M4 ;
        RECT  43.116 10.704 43.2 10.728 ;
    END
  END i_code[40]
  PIN i_code[41]
    DIRECTION INPUT ;
    USE SIGNAL ;
    PORT
      LAYER M4 ;
        RECT  43.116 10.8 43.2 10.824 ;
    END
  END i_code[41]
  PIN i_code[42]
    DIRECTION INPUT ;
    USE SIGNAL ;
    PORT
      LAYER M4 ;
        RECT  43.116 10.896 43.2 10.92 ;
    END
  END i_code[42]
  PIN i_code[43]
    DIRECTION INPUT ;
    USE SIGNAL ;
    PORT
      LAYER M4 ;
        RECT  43.116 10.992 43.2 11.016 ;
    END
  END i_code[43]
  PIN i_code[44]
    DIRECTION INPUT ;
    USE SIGNAL ;
    PORT
      LAYER M4 ;
        RECT  43.116 11.088 43.2 11.112 ;
    END
  END i_code[44]
  PIN i_code[45]
    DIRECTION INPUT ;
    USE SIGNAL ;
    PORT
      LAYER M4 ;
        RECT  43.116 11.184 43.2 11.208 ;
    END
  END i_code[45]
  PIN i_code[46]
    DIRECTION INPUT ;
    USE SIGNAL ;
    PORT
      LAYER M4 ;
        RECT  43.116 11.28 43.2 11.304 ;
    END
  END i_code[46]
  PIN i_code[47]
    DIRECTION INPUT ;
    USE SIGNAL ;
    PORT
      LAYER M4 ;
        RECT  43.116 11.376 43.2 11.4 ;
    END
  END i_code[47]
  PIN i_code[48]
    DIRECTION INPUT ;
    USE SIGNAL ;
    PORT
      LAYER M4 ;
        RECT  43.116 11.472 43.2 11.496 ;
    END
  END i_code[48]
  PIN i_code[49]
    DIRECTION INPUT ;
    USE SIGNAL ;
    PORT
      LAYER M4 ;
        RECT  43.116 11.568 43.2 11.592 ;
    END
  END i_code[49]
  PIN i_code[4]
    DIRECTION INPUT ;
    USE SIGNAL ;
    PORT
      LAYER M4 ;
        RECT  43.116 23.376 43.2 23.4 ;
    END
  END i_code[4]
  PIN i_code[50]
    DIRECTION INPUT ;
    USE SIGNAL ;
    PORT
      LAYER M4 ;
        RECT  43.116 11.664 43.2 11.688 ;
    END
  END i_code[50]
  PIN i_code[51]
    DIRECTION INPUT ;
    USE SIGNAL ;
    PORT
      LAYER M4 ;
        RECT  43.116 11.76 43.2 11.784 ;
    END
  END i_code[51]
  PIN i_code[52]
    DIRECTION INPUT ;
    USE SIGNAL ;
    PORT
      LAYER M4 ;
        RECT  43.116 11.856 43.2 11.88 ;
    END
  END i_code[52]
  PIN i_code[53]
    DIRECTION INPUT ;
    USE SIGNAL ;
    PORT
      LAYER M4 ;
        RECT  43.116 11.952 43.2 11.976 ;
    END
  END i_code[53]
  PIN i_code[54]
    DIRECTION INPUT ;
    USE SIGNAL ;
    PORT
      LAYER M4 ;
        RECT  43.116 12.048 43.2 12.072 ;
    END
  END i_code[54]
  PIN i_code[55]
    DIRECTION INPUT ;
    USE SIGNAL ;
    PORT
      LAYER M4 ;
        RECT  43.116 12.144 43.2 12.168 ;
    END
  END i_code[55]
  PIN i_code[56]
    DIRECTION INPUT ;
    USE SIGNAL ;
    PORT
      LAYER M4 ;
        RECT  43.116 12.24 43.2 12.264 ;
    END
  END i_code[56]
  PIN i_code[57]
    DIRECTION INPUT ;
    USE SIGNAL ;
    PORT
      LAYER M4 ;
        RECT  43.116 12.336 43.2 12.36 ;
    END
  END i_code[57]
  PIN i_code[58]
    DIRECTION INPUT ;
    USE SIGNAL ;
    PORT
      LAYER M4 ;
        RECT  43.116 12.432 43.2 12.456 ;
    END
  END i_code[58]
  PIN i_code[59]
    DIRECTION INPUT ;
    USE SIGNAL ;
    PORT
      LAYER M4 ;
        RECT  43.116 12.528 43.2 12.552 ;
    END
  END i_code[59]
  PIN i_code[5]
    DIRECTION INPUT ;
    USE SIGNAL ;
    PORT
      LAYER M4 ;
        RECT  43.116 23.472 43.2 23.496 ;
    END
  END i_code[5]
  PIN i_code[60]
    DIRECTION INPUT ;
    USE SIGNAL ;
    PORT
      LAYER M4 ;
        RECT  43.116 12.624 43.2 12.648 ;
    END
  END i_code[60]
  PIN i_code[61]
    DIRECTION INPUT ;
    USE SIGNAL ;
    PORT
      LAYER M4 ;
        RECT  43.116 12.72 43.2 12.744 ;
    END
  END i_code[61]
  PIN i_code[62]
    DIRECTION INPUT ;
    USE SIGNAL ;
    PORT
      LAYER M4 ;
        RECT  43.116 12.816 43.2 12.84 ;
    END
  END i_code[62]
  PIN i_code[63]
    DIRECTION INPUT ;
    USE SIGNAL ;
    PORT
      LAYER M4 ;
        RECT  43.116 12.912 43.2 12.936 ;
    END
  END i_code[63]
  PIN i_code[64]
    DIRECTION INPUT ;
    USE SIGNAL ;
    PORT
      LAYER M4 ;
        RECT  43.116 6.864 43.2 6.888 ;
    END
  END i_code[64]
  PIN i_code[65]
    DIRECTION INPUT ;
    USE SIGNAL ;
    PORT
      LAYER M4 ;
        RECT  43.116 6.96 43.2 6.984 ;
    END
  END i_code[65]
  PIN i_code[66]
    DIRECTION INPUT ;
    USE SIGNAL ;
    PORT
      LAYER M4 ;
        RECT  43.116 7.056 43.2 7.08 ;
    END
  END i_code[66]
  PIN i_code[67]
    DIRECTION INPUT ;
    USE SIGNAL ;
    PORT
      LAYER M4 ;
        RECT  43.116 7.152 43.2 7.176 ;
    END
  END i_code[67]
  PIN i_code[68]
    DIRECTION INPUT ;
    USE SIGNAL ;
    PORT
      LAYER M4 ;
        RECT  43.116 7.248 43.2 7.272 ;
    END
  END i_code[68]
  PIN i_code[69]
    DIRECTION INPUT ;
    USE SIGNAL ;
    PORT
      LAYER M4 ;
        RECT  43.116 7.344 43.2 7.368 ;
    END
  END i_code[69]
  PIN i_code[6]
    DIRECTION INPUT ;
    USE SIGNAL ;
    PORT
      LAYER M4 ;
        RECT  43.116 23.568 43.2 23.592 ;
    END
  END i_code[6]
  PIN i_code[70]
    DIRECTION INPUT ;
    USE SIGNAL ;
    PORT
      LAYER M4 ;
        RECT  43.116 7.44 43.2 7.464 ;
    END
  END i_code[70]
  PIN i_code[71]
    DIRECTION INPUT ;
    USE SIGNAL ;
    PORT
      LAYER M4 ;
        RECT  43.116 7.536 43.2 7.56 ;
    END
  END i_code[71]
  PIN i_code[72]
    DIRECTION INPUT ;
    USE SIGNAL ;
    PORT
      LAYER M4 ;
        RECT  43.116 7.632 43.2 7.656 ;
    END
  END i_code[72]
  PIN i_code[73]
    DIRECTION INPUT ;
    USE SIGNAL ;
    PORT
      LAYER M4 ;
        RECT  43.116 7.728 43.2 7.752 ;
    END
  END i_code[73]
  PIN i_code[74]
    DIRECTION INPUT ;
    USE SIGNAL ;
    PORT
      LAYER M4 ;
        RECT  43.116 7.824 43.2 7.848 ;
    END
  END i_code[74]
  PIN i_code[75]
    DIRECTION INPUT ;
    USE SIGNAL ;
    PORT
      LAYER M4 ;
        RECT  43.116 7.92 43.2 7.944 ;
    END
  END i_code[75]
  PIN i_code[76]
    DIRECTION INPUT ;
    USE SIGNAL ;
    PORT
      LAYER M4 ;
        RECT  43.116 8.016 43.2 8.04 ;
    END
  END i_code[76]
  PIN i_code[77]
    DIRECTION INPUT ;
    USE SIGNAL ;
    PORT
      LAYER M4 ;
        RECT  43.116 8.112 43.2 8.136 ;
    END
  END i_code[77]
  PIN i_code[78]
    DIRECTION INPUT ;
    USE SIGNAL ;
    PORT
      LAYER M4 ;
        RECT  43.116 8.208 43.2 8.232 ;
    END
  END i_code[78]
  PIN i_code[79]
    DIRECTION INPUT ;
    USE SIGNAL ;
    PORT
      LAYER M4 ;
        RECT  43.116 8.304 43.2 8.328 ;
    END
  END i_code[79]
  PIN i_code[7]
    DIRECTION INPUT ;
    USE SIGNAL ;
    PORT
      LAYER M4 ;
        RECT  43.116 23.664 43.2 23.688 ;
    END
  END i_code[7]
  PIN i_code[80]
    DIRECTION INPUT ;
    USE SIGNAL ;
    PORT
      LAYER M4 ;
        RECT  43.116 8.4 43.2 8.424 ;
    END
  END i_code[80]
  PIN i_code[81]
    DIRECTION INPUT ;
    USE SIGNAL ;
    PORT
      LAYER M4 ;
        RECT  43.116 8.496 43.2 8.52 ;
    END
  END i_code[81]
  PIN i_code[82]
    DIRECTION INPUT ;
    USE SIGNAL ;
    PORT
      LAYER M4 ;
        RECT  43.116 8.592 43.2 8.616 ;
    END
  END i_code[82]
  PIN i_code[83]
    DIRECTION INPUT ;
    USE SIGNAL ;
    PORT
      LAYER M4 ;
        RECT  43.116 8.688 43.2 8.712 ;
    END
  END i_code[83]
  PIN i_code[84]
    DIRECTION INPUT ;
    USE SIGNAL ;
    PORT
      LAYER M4 ;
        RECT  43.116 8.784 43.2 8.808 ;
    END
  END i_code[84]
  PIN i_code[85]
    DIRECTION INPUT ;
    USE SIGNAL ;
    PORT
      LAYER M4 ;
        RECT  43.116 8.88 43.2 8.904 ;
    END
  END i_code[85]
  PIN i_code[86]
    DIRECTION INPUT ;
    USE SIGNAL ;
    PORT
      LAYER M4 ;
        RECT  43.116 8.976 43.2 9 ;
    END
  END i_code[86]
  PIN i_code[87]
    DIRECTION INPUT ;
    USE SIGNAL ;
    PORT
      LAYER M4 ;
        RECT  43.116 9.072 43.2 9.096 ;
    END
  END i_code[87]
  PIN i_code[88]
    DIRECTION INPUT ;
    USE SIGNAL ;
    PORT
      LAYER M4 ;
        RECT  43.116 9.168 43.2 9.192 ;
    END
  END i_code[88]
  PIN i_code[89]
    DIRECTION INPUT ;
    USE SIGNAL ;
    PORT
      LAYER M4 ;
        RECT  43.116 9.264 43.2 9.288 ;
    END
  END i_code[89]
  PIN i_code[8]
    DIRECTION INPUT ;
    USE SIGNAL ;
    PORT
      LAYER M4 ;
        RECT  43.116 23.76 43.2 23.784 ;
    END
  END i_code[8]
  PIN i_code[90]
    DIRECTION INPUT ;
    USE SIGNAL ;
    PORT
      LAYER M4 ;
        RECT  43.116 9.36 43.2 9.384 ;
    END
  END i_code[90]
  PIN i_code[91]
    DIRECTION INPUT ;
    USE SIGNAL ;
    PORT
      LAYER M4 ;
        RECT  43.116 9.456 43.2 9.48 ;
    END
  END i_code[91]
  PIN i_code[92]
    DIRECTION INPUT ;
    USE SIGNAL ;
    PORT
      LAYER M4 ;
        RECT  43.116 9.552 43.2 9.576 ;
    END
  END i_code[92]
  PIN i_code[93]
    DIRECTION INPUT ;
    USE SIGNAL ;
    PORT
      LAYER M4 ;
        RECT  43.116 9.648 43.2 9.672 ;
    END
  END i_code[93]
  PIN i_code[94]
    DIRECTION INPUT ;
    USE SIGNAL ;
    PORT
      LAYER M4 ;
        RECT  43.116 9.744 43.2 9.768 ;
    END
  END i_code[94]
  PIN i_code[95]
    DIRECTION INPUT ;
    USE SIGNAL ;
    PORT
      LAYER M4 ;
        RECT  43.116 9.84 43.2 9.864 ;
    END
  END i_code[95]
  PIN i_code[96]
    DIRECTION INPUT ;
    USE SIGNAL ;
    PORT
      LAYER M4 ;
        RECT  43.116 3.792 43.2 3.816 ;
    END
  END i_code[96]
  PIN i_code[97]
    DIRECTION INPUT ;
    USE SIGNAL ;
    PORT
      LAYER M4 ;
        RECT  43.116 3.888 43.2 3.912 ;
    END
  END i_code[97]
  PIN i_code[98]
    DIRECTION INPUT ;
    USE SIGNAL ;
    PORT
      LAYER M4 ;
        RECT  43.116 3.984 43.2 4.008 ;
    END
  END i_code[98]
  PIN i_code[99]
    DIRECTION INPUT ;
    USE SIGNAL ;
    PORT
      LAYER M4 ;
        RECT  43.116 4.08 43.2 4.104 ;
    END
  END i_code[99]
  PIN i_code[9]
    DIRECTION INPUT ;
    USE SIGNAL ;
    PORT
      LAYER M4 ;
        RECT  43.116 23.856 43.2 23.88 ;
    END
  END i_code[9]
  PIN i_row[0]
    DIRECTION INPUT ;
    USE SIGNAL ;
    PORT
      LAYER M4 ;
        RECT  43.116 32.208 43.2 32.232 ;
    END
  END i_row[0]
  PIN i_row[1]
    DIRECTION INPUT ;
    USE SIGNAL ;
    PORT
      LAYER M4 ;
        RECT  43.116 32.304 43.2 32.328 ;
    END
  END i_row[1]
  PIN i_row[2]
    DIRECTION INPUT ;
    USE SIGNAL ;
    PORT
      LAYER M4 ;
        RECT  43.116 32.4 43.2 32.424 ;
    END
  END i_row[2]
  PIN i_row[3]
    DIRECTION INPUT ;
    USE SIGNAL ;
    PORT
      LAYER M4 ;
        RECT  43.116 32.496 43.2 32.52 ;
    END
  END i_row[3]
  PIN i_row[4]
    DIRECTION INPUT ;
    USE SIGNAL ;
    PORT
      LAYER M4 ;
        RECT  43.116 32.592 43.2 32.616 ;
    END
  END i_row[4]
  PIN i_row[5]
    DIRECTION INPUT ;
    USE SIGNAL ;
    PORT
      LAYER M4 ;
        RECT  43.116 32.688 43.2 32.712 ;
    END
  END i_row[5]
  PIN i_row[6]
    DIRECTION INPUT ;
    USE SIGNAL ;
    PORT
      LAYER M4 ;
        RECT  43.116 32.784 43.2 32.808 ;
    END
  END i_row[6]
  PIN i_row[7]
    DIRECTION INPUT ;
    USE SIGNAL ;
    PORT
      LAYER M4 ;
        RECT  43.116 32.88 43.2 32.904 ;
    END
  END i_row[7]
  PIN i_sec[0]
    DIRECTION INPUT ;
    USE SIGNAL ;
    PORT
      LAYER M4 ;
        RECT  43.116 32.976 43.2 33 ;
    END
  END i_sec[0]
  PIN i_sec[10]
    DIRECTION INPUT ;
    USE SIGNAL ;
    PORT
      LAYER M4 ;
        RECT  43.116 33.936 43.2 33.96 ;
    END
  END i_sec[10]
  PIN i_sec[11]
    DIRECTION INPUT ;
    USE SIGNAL ;
    PORT
      LAYER M4 ;
        RECT  43.116 34.032 43.2 34.056 ;
    END
  END i_sec[11]
  PIN i_sec[12]
    DIRECTION INPUT ;
    USE SIGNAL ;
    PORT
      LAYER M4 ;
        RECT  43.116 34.128 43.2 34.152 ;
    END
  END i_sec[12]
  PIN i_sec[13]
    DIRECTION INPUT ;
    USE SIGNAL ;
    PORT
      LAYER M4 ;
        RECT  43.116 34.224 43.2 34.248 ;
    END
  END i_sec[13]
  PIN i_sec[14]
    DIRECTION INPUT ;
    USE SIGNAL ;
    PORT
      LAYER M4 ;
        RECT  43.116 34.32 43.2 34.344 ;
    END
  END i_sec[14]
  PIN i_sec[15]
    DIRECTION INPUT ;
    USE SIGNAL ;
    PORT
      LAYER M4 ;
        RECT  43.116 34.416 43.2 34.44 ;
    END
  END i_sec[15]
  PIN i_sec[16]
    DIRECTION INPUT ;
    USE SIGNAL ;
    PORT
      LAYER M4 ;
        RECT  43.116 34.512 43.2 34.536 ;
    END
  END i_sec[16]
  PIN i_sec[1]
    DIRECTION INPUT ;
    USE SIGNAL ;
    PORT
      LAYER M4 ;
        RECT  43.116 33.072 43.2 33.096 ;
    END
  END i_sec[1]
  PIN i_sec[2]
    DIRECTION INPUT ;
    USE SIGNAL ;
    PORT
      LAYER M4 ;
        RECT  43.116 33.168 43.2 33.192 ;
    END
  END i_sec[2]
  PIN i_sec[3]
    DIRECTION INPUT ;
    USE SIGNAL ;
    PORT
      LAYER M4 ;
        RECT  43.116 33.264 43.2 33.288 ;
    END
  END i_sec[3]
  PIN i_sec[4]
    DIRECTION INPUT ;
    USE SIGNAL ;
    PORT
      LAYER M4 ;
        RECT  43.116 33.36 43.2 33.384 ;
    END
  END i_sec[4]
  PIN i_sec[5]
    DIRECTION INPUT ;
    USE SIGNAL ;
    PORT
      LAYER M4 ;
        RECT  43.116 33.456 43.2 33.48 ;
    END
  END i_sec[5]
  PIN i_sec[6]
    DIRECTION INPUT ;
    USE SIGNAL ;
    PORT
      LAYER M4 ;
        RECT  43.116 33.552 43.2 33.576 ;
    END
  END i_sec[6]
  PIN i_sec[7]
    DIRECTION INPUT ;
    USE SIGNAL ;
    PORT
      LAYER M4 ;
        RECT  43.116 33.648 43.2 33.672 ;
    END
  END i_sec[7]
  PIN i_sec[8]
    DIRECTION INPUT ;
    USE SIGNAL ;
    PORT
      LAYER M4 ;
        RECT  43.116 33.744 43.2 33.768 ;
    END
  END i_sec[8]
  PIN i_sec[9]
    DIRECTION INPUT ;
    USE SIGNAL ;
    PORT
      LAYER M4 ;
        RECT  43.116 33.84 43.2 33.864 ;
    END
  END i_sec[9]
  PIN i_v
    DIRECTION INPUT ;
    USE SIGNAL ;
    PORT
      LAYER M4 ;
        RECT  43.116 34.608 43.2 34.632 ;
    END
  END i_v
  PIN o_data[0]
    DIRECTION OUTPUT ;
    USE SIGNAL ;
    PORT
      LAYER M4 ;
        RECT  0 24.048 0.084 24.072 ;
    END
  END o_data[0]
  PIN o_data[100]
    DIRECTION OUTPUT ;
    USE SIGNAL ;
    PORT
      LAYER M4 ;
        RECT  0 8.304 0.084 8.328 ;
    END
  END o_data[100]
  PIN o_data[101]
    DIRECTION OUTPUT ;
    USE SIGNAL ;
    PORT
      LAYER M4 ;
        RECT  0 8.4 0.084 8.424 ;
    END
  END o_data[101]
  PIN o_data[102]
    DIRECTION OUTPUT ;
    USE SIGNAL ;
    PORT
      LAYER M4 ;
        RECT  0 8.496 0.084 8.52 ;
    END
  END o_data[102]
  PIN o_data[103]
    DIRECTION OUTPUT ;
    USE SIGNAL ;
    PORT
      LAYER M4 ;
        RECT  0 8.592 0.084 8.616 ;
    END
  END o_data[103]
  PIN o_data[104]
    DIRECTION OUTPUT ;
    USE SIGNAL ;
    PORT
      LAYER M4 ;
        RECT  0 8.688 0.084 8.712 ;
    END
  END o_data[104]
  PIN o_data[105]
    DIRECTION OUTPUT ;
    USE SIGNAL ;
    PORT
      LAYER M4 ;
        RECT  0 8.784 0.084 8.808 ;
    END
  END o_data[105]
  PIN o_data[106]
    DIRECTION OUTPUT ;
    USE SIGNAL ;
    PORT
      LAYER M4 ;
        RECT  0 8.88 0.084 8.904 ;
    END
  END o_data[106]
  PIN o_data[107]
    DIRECTION OUTPUT ;
    USE SIGNAL ;
    PORT
      LAYER M4 ;
        RECT  0 8.976 0.084 9 ;
    END
  END o_data[107]
  PIN o_data[108]
    DIRECTION OUTPUT ;
    USE SIGNAL ;
    PORT
      LAYER M4 ;
        RECT  0 9.072 0.084 9.096 ;
    END
  END o_data[108]
  PIN o_data[109]
    DIRECTION OUTPUT ;
    USE SIGNAL ;
    PORT
      LAYER M4 ;
        RECT  0 9.168 0.084 9.192 ;
    END
  END o_data[109]
  PIN o_data[10]
    DIRECTION OUTPUT ;
    USE SIGNAL ;
    PORT
      LAYER M4 ;
        RECT  0 25.008 0.084 25.032 ;
    END
  END o_data[10]
  PIN o_data[110]
    DIRECTION OUTPUT ;
    USE SIGNAL ;
    PORT
      LAYER M4 ;
        RECT  0 9.264 0.084 9.288 ;
    END
  END o_data[110]
  PIN o_data[111]
    DIRECTION OUTPUT ;
    USE SIGNAL ;
    PORT
      LAYER M4 ;
        RECT  0 9.36 0.084 9.384 ;
    END
  END o_data[111]
  PIN o_data[112]
    DIRECTION OUTPUT ;
    USE SIGNAL ;
    PORT
      LAYER M4 ;
        RECT  0 9.456 0.084 9.48 ;
    END
  END o_data[112]
  PIN o_data[113]
    DIRECTION OUTPUT ;
    USE SIGNAL ;
    PORT
      LAYER M4 ;
        RECT  0 9.552 0.084 9.576 ;
    END
  END o_data[113]
  PIN o_data[114]
    DIRECTION OUTPUT ;
    USE SIGNAL ;
    PORT
      LAYER M4 ;
        RECT  0 9.648 0.084 9.672 ;
    END
  END o_data[114]
  PIN o_data[115]
    DIRECTION OUTPUT ;
    USE SIGNAL ;
    PORT
      LAYER M4 ;
        RECT  0 9.744 0.084 9.768 ;
    END
  END o_data[115]
  PIN o_data[116]
    DIRECTION OUTPUT ;
    USE SIGNAL ;
    PORT
      LAYER M4 ;
        RECT  0 9.84 0.084 9.864 ;
    END
  END o_data[116]
  PIN o_data[117]
    DIRECTION OUTPUT ;
    USE SIGNAL ;
    PORT
      LAYER M4 ;
        RECT  0 9.936 0.084 9.96 ;
    END
  END o_data[117]
  PIN o_data[118]
    DIRECTION OUTPUT ;
    USE SIGNAL ;
    PORT
      LAYER M4 ;
        RECT  0 10.032 0.084 10.056 ;
    END
  END o_data[118]
  PIN o_data[119]
    DIRECTION OUTPUT ;
    USE SIGNAL ;
    PORT
      LAYER M4 ;
        RECT  0 10.128 0.084 10.152 ;
    END
  END o_data[119]
  PIN o_data[11]
    DIRECTION OUTPUT ;
    USE SIGNAL ;
    PORT
      LAYER M4 ;
        RECT  0 25.104 0.084 25.128 ;
    END
  END o_data[11]
  PIN o_data[120]
    DIRECTION OUTPUT ;
    USE SIGNAL ;
    PORT
      LAYER M4 ;
        RECT  0 10.224 0.084 10.248 ;
    END
  END o_data[120]
  PIN o_data[121]
    DIRECTION OUTPUT ;
    USE SIGNAL ;
    PORT
      LAYER M4 ;
        RECT  0 10.32 0.084 10.344 ;
    END
  END o_data[121]
  PIN o_data[122]
    DIRECTION OUTPUT ;
    USE SIGNAL ;
    PORT
      LAYER M4 ;
        RECT  0 10.416 0.084 10.44 ;
    END
  END o_data[122]
  PIN o_data[123]
    DIRECTION OUTPUT ;
    USE SIGNAL ;
    PORT
      LAYER M4 ;
        RECT  0 10.512 0.084 10.536 ;
    END
  END o_data[123]
  PIN o_data[124]
    DIRECTION OUTPUT ;
    USE SIGNAL ;
    PORT
      LAYER M4 ;
        RECT  0 10.608 0.084 10.632 ;
    END
  END o_data[124]
  PIN o_data[125]
    DIRECTION OUTPUT ;
    USE SIGNAL ;
    PORT
      LAYER M4 ;
        RECT  0 10.704 0.084 10.728 ;
    END
  END o_data[125]
  PIN o_data[126]
    DIRECTION OUTPUT ;
    USE SIGNAL ;
    PORT
      LAYER M4 ;
        RECT  0 10.8 0.084 10.824 ;
    END
  END o_data[126]
  PIN o_data[127]
    DIRECTION OUTPUT ;
    USE SIGNAL ;
    PORT
      LAYER M4 ;
        RECT  0 10.896 0.084 10.92 ;
    END
  END o_data[127]
  PIN o_data[128]
    DIRECTION OUTPUT ;
    USE SIGNAL ;
    PORT
      LAYER M4 ;
        RECT  0 14.064 0.084 14.088 ;
    END
  END o_data[128]
  PIN o_data[129]
    DIRECTION OUTPUT ;
    USE SIGNAL ;
    PORT
      LAYER M4 ;
        RECT  0 14.16 0.084 14.184 ;
    END
  END o_data[129]
  PIN o_data[12]
    DIRECTION OUTPUT ;
    USE SIGNAL ;
    PORT
      LAYER M4 ;
        RECT  0 25.2 0.084 25.224 ;
    END
  END o_data[12]
  PIN o_data[130]
    DIRECTION OUTPUT ;
    USE SIGNAL ;
    PORT
      LAYER M4 ;
        RECT  0 14.256 0.084 14.28 ;
    END
  END o_data[130]
  PIN o_data[131]
    DIRECTION OUTPUT ;
    USE SIGNAL ;
    PORT
      LAYER M4 ;
        RECT  0 14.352 0.084 14.376 ;
    END
  END o_data[131]
  PIN o_data[132]
    DIRECTION OUTPUT ;
    USE SIGNAL ;
    PORT
      LAYER M4 ;
        RECT  0 14.448 0.084 14.472 ;
    END
  END o_data[132]
  PIN o_data[133]
    DIRECTION OUTPUT ;
    USE SIGNAL ;
    PORT
      LAYER M4 ;
        RECT  0 14.544 0.084 14.568 ;
    END
  END o_data[133]
  PIN o_data[134]
    DIRECTION OUTPUT ;
    USE SIGNAL ;
    PORT
      LAYER M4 ;
        RECT  0 14.64 0.084 14.664 ;
    END
  END o_data[134]
  PIN o_data[135]
    DIRECTION OUTPUT ;
    USE SIGNAL ;
    PORT
      LAYER M4 ;
        RECT  0 14.736 0.084 14.76 ;
    END
  END o_data[135]
  PIN o_data[136]
    DIRECTION OUTPUT ;
    USE SIGNAL ;
    PORT
      LAYER M4 ;
        RECT  0 14.832 0.084 14.856 ;
    END
  END o_data[136]
  PIN o_data[137]
    DIRECTION OUTPUT ;
    USE SIGNAL ;
    PORT
      LAYER M4 ;
        RECT  0 14.928 0.084 14.952 ;
    END
  END o_data[137]
  PIN o_data[138]
    DIRECTION OUTPUT ;
    USE SIGNAL ;
    PORT
      LAYER M4 ;
        RECT  0 15.024 0.084 15.048 ;
    END
  END o_data[138]
  PIN o_data[139]
    DIRECTION OUTPUT ;
    USE SIGNAL ;
    PORT
      LAYER M4 ;
        RECT  0 15.12 0.084 15.144 ;
    END
  END o_data[139]
  PIN o_data[13]
    DIRECTION OUTPUT ;
    USE SIGNAL ;
    PORT
      LAYER M4 ;
        RECT  0 25.296 0.084 25.32 ;
    END
  END o_data[13]
  PIN o_data[140]
    DIRECTION OUTPUT ;
    USE SIGNAL ;
    PORT
      LAYER M4 ;
        RECT  0 15.216 0.084 15.24 ;
    END
  END o_data[140]
  PIN o_data[141]
    DIRECTION OUTPUT ;
    USE SIGNAL ;
    PORT
      LAYER M4 ;
        RECT  0 15.312 0.084 15.336 ;
    END
  END o_data[141]
  PIN o_data[142]
    DIRECTION OUTPUT ;
    USE SIGNAL ;
    PORT
      LAYER M4 ;
        RECT  0 15.408 0.084 15.432 ;
    END
  END o_data[142]
  PIN o_data[143]
    DIRECTION OUTPUT ;
    USE SIGNAL ;
    PORT
      LAYER M4 ;
        RECT  0 15.504 0.084 15.528 ;
    END
  END o_data[143]
  PIN o_data[144]
    DIRECTION OUTPUT ;
    USE SIGNAL ;
    PORT
      LAYER M4 ;
        RECT  0 15.6 0.084 15.624 ;
    END
  END o_data[144]
  PIN o_data[145]
    DIRECTION OUTPUT ;
    USE SIGNAL ;
    PORT
      LAYER M4 ;
        RECT  0 15.696 0.084 15.72 ;
    END
  END o_data[145]
  PIN o_data[146]
    DIRECTION OUTPUT ;
    USE SIGNAL ;
    PORT
      LAYER M4 ;
        RECT  0 15.792 0.084 15.816 ;
    END
  END o_data[146]
  PIN o_data[147]
    DIRECTION OUTPUT ;
    USE SIGNAL ;
    PORT
      LAYER M4 ;
        RECT  0 15.888 0.084 15.912 ;
    END
  END o_data[147]
  PIN o_data[148]
    DIRECTION OUTPUT ;
    USE SIGNAL ;
    PORT
      LAYER M4 ;
        RECT  0 15.984 0.084 16.008 ;
    END
  END o_data[148]
  PIN o_data[149]
    DIRECTION OUTPUT ;
    USE SIGNAL ;
    PORT
      LAYER M4 ;
        RECT  0 16.08 0.084 16.104 ;
    END
  END o_data[149]
  PIN o_data[14]
    DIRECTION OUTPUT ;
    USE SIGNAL ;
    PORT
      LAYER M4 ;
        RECT  0 25.392 0.084 25.416 ;
    END
  END o_data[14]
  PIN o_data[150]
    DIRECTION OUTPUT ;
    USE SIGNAL ;
    PORT
      LAYER M4 ;
        RECT  0 16.176 0.084 16.2 ;
    END
  END o_data[150]
  PIN o_data[151]
    DIRECTION OUTPUT ;
    USE SIGNAL ;
    PORT
      LAYER M4 ;
        RECT  0 16.272 0.084 16.296 ;
    END
  END o_data[151]
  PIN o_data[152]
    DIRECTION OUTPUT ;
    USE SIGNAL ;
    PORT
      LAYER M4 ;
        RECT  0 16.368 0.084 16.392 ;
    END
  END o_data[152]
  PIN o_data[153]
    DIRECTION OUTPUT ;
    USE SIGNAL ;
    PORT
      LAYER M4 ;
        RECT  0 16.464 0.084 16.488 ;
    END
  END o_data[153]
  PIN o_data[154]
    DIRECTION OUTPUT ;
    USE SIGNAL ;
    PORT
      LAYER M4 ;
        RECT  0 16.56 0.084 16.584 ;
    END
  END o_data[154]
  PIN o_data[155]
    DIRECTION OUTPUT ;
    USE SIGNAL ;
    PORT
      LAYER M4 ;
        RECT  0 16.656 0.084 16.68 ;
    END
  END o_data[155]
  PIN o_data[156]
    DIRECTION OUTPUT ;
    USE SIGNAL ;
    PORT
      LAYER M4 ;
        RECT  0 16.752 0.084 16.776 ;
    END
  END o_data[156]
  PIN o_data[157]
    DIRECTION OUTPUT ;
    USE SIGNAL ;
    PORT
      LAYER M4 ;
        RECT  0 16.848 0.084 16.872 ;
    END
  END o_data[157]
  PIN o_data[158]
    DIRECTION OUTPUT ;
    USE SIGNAL ;
    PORT
      LAYER M4 ;
        RECT  0 16.944 0.084 16.968 ;
    END
  END o_data[158]
  PIN o_data[159]
    DIRECTION OUTPUT ;
    USE SIGNAL ;
    PORT
      LAYER M4 ;
        RECT  0 17.04 0.084 17.064 ;
    END
  END o_data[159]
  PIN o_data[15]
    DIRECTION OUTPUT ;
    USE SIGNAL ;
    PORT
      LAYER M4 ;
        RECT  0 25.488 0.084 25.512 ;
    END
  END o_data[15]
  PIN o_data[160]
    DIRECTION OUTPUT ;
    USE SIGNAL ;
    PORT
      LAYER M4 ;
        RECT  0 27.12 0.084 27.144 ;
    END
  END o_data[160]
  PIN o_data[161]
    DIRECTION OUTPUT ;
    USE SIGNAL ;
    PORT
      LAYER M4 ;
        RECT  0 27.216 0.084 27.24 ;
    END
  END o_data[161]
  PIN o_data[162]
    DIRECTION OUTPUT ;
    USE SIGNAL ;
    PORT
      LAYER M4 ;
        RECT  0 27.312 0.084 27.336 ;
    END
  END o_data[162]
  PIN o_data[163]
    DIRECTION OUTPUT ;
    USE SIGNAL ;
    PORT
      LAYER M4 ;
        RECT  0 27.408 0.084 27.432 ;
    END
  END o_data[163]
  PIN o_data[164]
    DIRECTION OUTPUT ;
    USE SIGNAL ;
    PORT
      LAYER M4 ;
        RECT  0 27.504 0.084 27.528 ;
    END
  END o_data[164]
  PIN o_data[165]
    DIRECTION OUTPUT ;
    USE SIGNAL ;
    PORT
      LAYER M4 ;
        RECT  0 27.6 0.084 27.624 ;
    END
  END o_data[165]
  PIN o_data[166]
    DIRECTION OUTPUT ;
    USE SIGNAL ;
    PORT
      LAYER M4 ;
        RECT  0 27.696 0.084 27.72 ;
    END
  END o_data[166]
  PIN o_data[167]
    DIRECTION OUTPUT ;
    USE SIGNAL ;
    PORT
      LAYER M4 ;
        RECT  0 27.792 0.084 27.816 ;
    END
  END o_data[167]
  PIN o_data[168]
    DIRECTION OUTPUT ;
    USE SIGNAL ;
    PORT
      LAYER M4 ;
        RECT  0 27.888 0.084 27.912 ;
    END
  END o_data[168]
  PIN o_data[169]
    DIRECTION OUTPUT ;
    USE SIGNAL ;
    PORT
      LAYER M4 ;
        RECT  0 27.984 0.084 28.008 ;
    END
  END o_data[169]
  PIN o_data[16]
    DIRECTION OUTPUT ;
    USE SIGNAL ;
    PORT
      LAYER M4 ;
        RECT  0 25.584 0.084 25.608 ;
    END
  END o_data[16]
  PIN o_data[170]
    DIRECTION OUTPUT ;
    USE SIGNAL ;
    PORT
      LAYER M4 ;
        RECT  0 28.08 0.084 28.104 ;
    END
  END o_data[170]
  PIN o_data[171]
    DIRECTION OUTPUT ;
    USE SIGNAL ;
    PORT
      LAYER M4 ;
        RECT  0 28.176 0.084 28.2 ;
    END
  END o_data[171]
  PIN o_data[172]
    DIRECTION OUTPUT ;
    USE SIGNAL ;
    PORT
      LAYER M4 ;
        RECT  0 28.272 0.084 28.296 ;
    END
  END o_data[172]
  PIN o_data[173]
    DIRECTION OUTPUT ;
    USE SIGNAL ;
    PORT
      LAYER M4 ;
        RECT  0 28.368 0.084 28.392 ;
    END
  END o_data[173]
  PIN o_data[174]
    DIRECTION OUTPUT ;
    USE SIGNAL ;
    PORT
      LAYER M4 ;
        RECT  0 28.464 0.084 28.488 ;
    END
  END o_data[174]
  PIN o_data[175]
    DIRECTION OUTPUT ;
    USE SIGNAL ;
    PORT
      LAYER M4 ;
        RECT  0 28.56 0.084 28.584 ;
    END
  END o_data[175]
  PIN o_data[176]
    DIRECTION OUTPUT ;
    USE SIGNAL ;
    PORT
      LAYER M4 ;
        RECT  0 28.656 0.084 28.68 ;
    END
  END o_data[176]
  PIN o_data[177]
    DIRECTION OUTPUT ;
    USE SIGNAL ;
    PORT
      LAYER M4 ;
        RECT  0 28.752 0.084 28.776 ;
    END
  END o_data[177]
  PIN o_data[178]
    DIRECTION OUTPUT ;
    USE SIGNAL ;
    PORT
      LAYER M4 ;
        RECT  0 28.848 0.084 28.872 ;
    END
  END o_data[178]
  PIN o_data[179]
    DIRECTION OUTPUT ;
    USE SIGNAL ;
    PORT
      LAYER M4 ;
        RECT  0 28.944 0.084 28.968 ;
    END
  END o_data[179]
  PIN o_data[17]
    DIRECTION OUTPUT ;
    USE SIGNAL ;
    PORT
      LAYER M4 ;
        RECT  0 25.68 0.084 25.704 ;
    END
  END o_data[17]
  PIN o_data[180]
    DIRECTION OUTPUT ;
    USE SIGNAL ;
    PORT
      LAYER M4 ;
        RECT  0 29.04 0.084 29.064 ;
    END
  END o_data[180]
  PIN o_data[181]
    DIRECTION OUTPUT ;
    USE SIGNAL ;
    PORT
      LAYER M4 ;
        RECT  0 29.136 0.084 29.16 ;
    END
  END o_data[181]
  PIN o_data[182]
    DIRECTION OUTPUT ;
    USE SIGNAL ;
    PORT
      LAYER M4 ;
        RECT  0 29.232 0.084 29.256 ;
    END
  END o_data[182]
  PIN o_data[183]
    DIRECTION OUTPUT ;
    USE SIGNAL ;
    PORT
      LAYER M4 ;
        RECT  0 29.328 0.084 29.352 ;
    END
  END o_data[183]
  PIN o_data[184]
    DIRECTION OUTPUT ;
    USE SIGNAL ;
    PORT
      LAYER M4 ;
        RECT  0 29.424 0.084 29.448 ;
    END
  END o_data[184]
  PIN o_data[185]
    DIRECTION OUTPUT ;
    USE SIGNAL ;
    PORT
      LAYER M4 ;
        RECT  0 29.52 0.084 29.544 ;
    END
  END o_data[185]
  PIN o_data[186]
    DIRECTION OUTPUT ;
    USE SIGNAL ;
    PORT
      LAYER M4 ;
        RECT  0 29.616 0.084 29.64 ;
    END
  END o_data[186]
  PIN o_data[187]
    DIRECTION OUTPUT ;
    USE SIGNAL ;
    PORT
      LAYER M4 ;
        RECT  0 29.712 0.084 29.736 ;
    END
  END o_data[187]
  PIN o_data[188]
    DIRECTION OUTPUT ;
    USE SIGNAL ;
    PORT
      LAYER M4 ;
        RECT  0 29.808 0.084 29.832 ;
    END
  END o_data[188]
  PIN o_data[189]
    DIRECTION OUTPUT ;
    USE SIGNAL ;
    PORT
      LAYER M4 ;
        RECT  0 29.904 0.084 29.928 ;
    END
  END o_data[189]
  PIN o_data[18]
    DIRECTION OUTPUT ;
    USE SIGNAL ;
    PORT
      LAYER M4 ;
        RECT  0 25.776 0.084 25.8 ;
    END
  END o_data[18]
  PIN o_data[190]
    DIRECTION OUTPUT ;
    USE SIGNAL ;
    PORT
      LAYER M4 ;
        RECT  0 30 0.084 30.024 ;
    END
  END o_data[190]
  PIN o_data[191]
    DIRECTION OUTPUT ;
    USE SIGNAL ;
    PORT
      LAYER M4 ;
        RECT  0 30.096 0.084 30.12 ;
    END
  END o_data[191]
  PIN o_data[192]
    DIRECTION OUTPUT ;
    USE SIGNAL ;
    PORT
      LAYER M4 ;
        RECT  0 30.192 0.084 30.216 ;
    END
  END o_data[192]
  PIN o_data[193]
    DIRECTION OUTPUT ;
    USE SIGNAL ;
    PORT
      LAYER M4 ;
        RECT  0 30.288 0.084 30.312 ;
    END
  END o_data[193]
  PIN o_data[194]
    DIRECTION OUTPUT ;
    USE SIGNAL ;
    PORT
      LAYER M4 ;
        RECT  0 30.384 0.084 30.408 ;
    END
  END o_data[194]
  PIN o_data[195]
    DIRECTION OUTPUT ;
    USE SIGNAL ;
    PORT
      LAYER M4 ;
        RECT  0 30.48 0.084 30.504 ;
    END
  END o_data[195]
  PIN o_data[196]
    DIRECTION OUTPUT ;
    USE SIGNAL ;
    PORT
      LAYER M4 ;
        RECT  0 30.576 0.084 30.6 ;
    END
  END o_data[196]
  PIN o_data[197]
    DIRECTION OUTPUT ;
    USE SIGNAL ;
    PORT
      LAYER M4 ;
        RECT  0 30.672 0.084 30.696 ;
    END
  END o_data[197]
  PIN o_data[198]
    DIRECTION OUTPUT ;
    USE SIGNAL ;
    PORT
      LAYER M4 ;
        RECT  0 30.768 0.084 30.792 ;
    END
  END o_data[198]
  PIN o_data[199]
    DIRECTION OUTPUT ;
    USE SIGNAL ;
    PORT
      LAYER M4 ;
        RECT  0 30.864 0.084 30.888 ;
    END
  END o_data[199]
  PIN o_data[19]
    DIRECTION OUTPUT ;
    USE SIGNAL ;
    PORT
      LAYER M4 ;
        RECT  0 25.872 0.084 25.896 ;
    END
  END o_data[19]
  PIN o_data[1]
    DIRECTION OUTPUT ;
    USE SIGNAL ;
    PORT
      LAYER M4 ;
        RECT  0 24.144 0.084 24.168 ;
    END
  END o_data[1]
  PIN o_data[200]
    DIRECTION OUTPUT ;
    USE SIGNAL ;
    PORT
      LAYER M4 ;
        RECT  0 30.96 0.084 30.984 ;
    END
  END o_data[200]
  PIN o_data[201]
    DIRECTION OUTPUT ;
    USE SIGNAL ;
    PORT
      LAYER M4 ;
        RECT  0 31.056 0.084 31.08 ;
    END
  END o_data[201]
  PIN o_data[202]
    DIRECTION OUTPUT ;
    USE SIGNAL ;
    PORT
      LAYER M4 ;
        RECT  0 31.152 0.084 31.176 ;
    END
  END o_data[202]
  PIN o_data[203]
    DIRECTION OUTPUT ;
    USE SIGNAL ;
    PORT
      LAYER M4 ;
        RECT  0 31.248 0.084 31.272 ;
    END
  END o_data[203]
  PIN o_data[204]
    DIRECTION OUTPUT ;
    USE SIGNAL ;
    PORT
      LAYER M4 ;
        RECT  0 31.344 0.084 31.368 ;
    END
  END o_data[204]
  PIN o_data[205]
    DIRECTION OUTPUT ;
    USE SIGNAL ;
    PORT
      LAYER M4 ;
        RECT  0 31.44 0.084 31.464 ;
    END
  END o_data[205]
  PIN o_data[206]
    DIRECTION OUTPUT ;
    USE SIGNAL ;
    PORT
      LAYER M4 ;
        RECT  0 31.536 0.084 31.56 ;
    END
  END o_data[206]
  PIN o_data[207]
    DIRECTION OUTPUT ;
    USE SIGNAL ;
    PORT
      LAYER M4 ;
        RECT  0 31.632 0.084 31.656 ;
    END
  END o_data[207]
  PIN o_data[208]
    DIRECTION OUTPUT ;
    USE SIGNAL ;
    PORT
      LAYER M4 ;
        RECT  0 31.728 0.084 31.752 ;
    END
  END o_data[208]
  PIN o_data[209]
    DIRECTION OUTPUT ;
    USE SIGNAL ;
    PORT
      LAYER M4 ;
        RECT  0 31.824 0.084 31.848 ;
    END
  END o_data[209]
  PIN o_data[20]
    DIRECTION OUTPUT ;
    USE SIGNAL ;
    PORT
      LAYER M4 ;
        RECT  0 25.968 0.084 25.992 ;
    END
  END o_data[20]
  PIN o_data[210]
    DIRECTION OUTPUT ;
    USE SIGNAL ;
    PORT
      LAYER M4 ;
        RECT  0 31.92 0.084 31.944 ;
    END
  END o_data[210]
  PIN o_data[211]
    DIRECTION OUTPUT ;
    USE SIGNAL ;
    PORT
      LAYER M4 ;
        RECT  0 32.016 0.084 32.04 ;
    END
  END o_data[211]
  PIN o_data[212]
    DIRECTION OUTPUT ;
    USE SIGNAL ;
    PORT
      LAYER M4 ;
        RECT  0 32.112 0.084 32.136 ;
    END
  END o_data[212]
  PIN o_data[213]
    DIRECTION OUTPUT ;
    USE SIGNAL ;
    PORT
      LAYER M4 ;
        RECT  0 32.208 0.084 32.232 ;
    END
  END o_data[213]
  PIN o_data[214]
    DIRECTION OUTPUT ;
    USE SIGNAL ;
    PORT
      LAYER M4 ;
        RECT  0 32.304 0.084 32.328 ;
    END
  END o_data[214]
  PIN o_data[215]
    DIRECTION OUTPUT ;
    USE SIGNAL ;
    PORT
      LAYER M4 ;
        RECT  0 32.4 0.084 32.424 ;
    END
  END o_data[215]
  PIN o_data[216]
    DIRECTION OUTPUT ;
    USE SIGNAL ;
    PORT
      LAYER M4 ;
        RECT  0 32.496 0.084 32.52 ;
    END
  END o_data[216]
  PIN o_data[217]
    DIRECTION OUTPUT ;
    USE SIGNAL ;
    PORT
      LAYER M4 ;
        RECT  0 32.592 0.084 32.616 ;
    END
  END o_data[217]
  PIN o_data[218]
    DIRECTION OUTPUT ;
    USE SIGNAL ;
    PORT
      LAYER M4 ;
        RECT  0 32.688 0.084 32.712 ;
    END
  END o_data[218]
  PIN o_data[219]
    DIRECTION OUTPUT ;
    USE SIGNAL ;
    PORT
      LAYER M4 ;
        RECT  0 32.784 0.084 32.808 ;
    END
  END o_data[219]
  PIN o_data[21]
    DIRECTION OUTPUT ;
    USE SIGNAL ;
    PORT
      LAYER M4 ;
        RECT  0 26.064 0.084 26.088 ;
    END
  END o_data[21]
  PIN o_data[220]
    DIRECTION OUTPUT ;
    USE SIGNAL ;
    PORT
      LAYER M4 ;
        RECT  0 32.88 0.084 32.904 ;
    END
  END o_data[220]
  PIN o_data[221]
    DIRECTION OUTPUT ;
    USE SIGNAL ;
    PORT
      LAYER M4 ;
        RECT  0 32.976 0.084 33 ;
    END
  END o_data[221]
  PIN o_data[222]
    DIRECTION OUTPUT ;
    USE SIGNAL ;
    PORT
      LAYER M4 ;
        RECT  0 33.072 0.084 33.096 ;
    END
  END o_data[222]
  PIN o_data[223]
    DIRECTION OUTPUT ;
    USE SIGNAL ;
    PORT
      LAYER M4 ;
        RECT  0 33.168 0.084 33.192 ;
    END
  END o_data[223]
  PIN o_data[224]
    DIRECTION OUTPUT ;
    USE SIGNAL ;
    PORT
      LAYER M4 ;
        RECT  0 36.336 0.084 36.36 ;
    END
  END o_data[224]
  PIN o_data[225]
    DIRECTION OUTPUT ;
    USE SIGNAL ;
    PORT
      LAYER M4 ;
        RECT  0 36.432 0.084 36.456 ;
    END
  END o_data[225]
  PIN o_data[226]
    DIRECTION OUTPUT ;
    USE SIGNAL ;
    PORT
      LAYER M4 ;
        RECT  0 36.528 0.084 36.552 ;
    END
  END o_data[226]
  PIN o_data[227]
    DIRECTION OUTPUT ;
    USE SIGNAL ;
    PORT
      LAYER M4 ;
        RECT  0 36.624 0.084 36.648 ;
    END
  END o_data[227]
  PIN o_data[228]
    DIRECTION OUTPUT ;
    USE SIGNAL ;
    PORT
      LAYER M4 ;
        RECT  0 36.72 0.084 36.744 ;
    END
  END o_data[228]
  PIN o_data[229]
    DIRECTION OUTPUT ;
    USE SIGNAL ;
    PORT
      LAYER M4 ;
        RECT  0 36.816 0.084 36.84 ;
    END
  END o_data[229]
  PIN o_data[22]
    DIRECTION OUTPUT ;
    USE SIGNAL ;
    PORT
      LAYER M4 ;
        RECT  0 26.16 0.084 26.184 ;
    END
  END o_data[22]
  PIN o_data[230]
    DIRECTION OUTPUT ;
    USE SIGNAL ;
    PORT
      LAYER M4 ;
        RECT  0 36.912 0.084 36.936 ;
    END
  END o_data[230]
  PIN o_data[231]
    DIRECTION OUTPUT ;
    USE SIGNAL ;
    PORT
      LAYER M4 ;
        RECT  0 37.008 0.084 37.032 ;
    END
  END o_data[231]
  PIN o_data[232]
    DIRECTION OUTPUT ;
    USE SIGNAL ;
    PORT
      LAYER M4 ;
        RECT  0 37.104 0.084 37.128 ;
    END
  END o_data[232]
  PIN o_data[233]
    DIRECTION OUTPUT ;
    USE SIGNAL ;
    PORT
      LAYER M4 ;
        RECT  0 37.2 0.084 37.224 ;
    END
  END o_data[233]
  PIN o_data[234]
    DIRECTION OUTPUT ;
    USE SIGNAL ;
    PORT
      LAYER M4 ;
        RECT  0 37.296 0.084 37.32 ;
    END
  END o_data[234]
  PIN o_data[235]
    DIRECTION OUTPUT ;
    USE SIGNAL ;
    PORT
      LAYER M4 ;
        RECT  0 37.392 0.084 37.416 ;
    END
  END o_data[235]
  PIN o_data[236]
    DIRECTION OUTPUT ;
    USE SIGNAL ;
    PORT
      LAYER M4 ;
        RECT  0 37.488 0.084 37.512 ;
    END
  END o_data[236]
  PIN o_data[237]
    DIRECTION OUTPUT ;
    USE SIGNAL ;
    PORT
      LAYER M4 ;
        RECT  0 37.584 0.084 37.608 ;
    END
  END o_data[237]
  PIN o_data[238]
    DIRECTION OUTPUT ;
    USE SIGNAL ;
    PORT
      LAYER M4 ;
        RECT  0 37.68 0.084 37.704 ;
    END
  END o_data[238]
  PIN o_data[239]
    DIRECTION OUTPUT ;
    USE SIGNAL ;
    PORT
      LAYER M4 ;
        RECT  0 37.776 0.084 37.8 ;
    END
  END o_data[239]
  PIN o_data[23]
    DIRECTION OUTPUT ;
    USE SIGNAL ;
    PORT
      LAYER M4 ;
        RECT  0 26.256 0.084 26.28 ;
    END
  END o_data[23]
  PIN o_data[240]
    DIRECTION OUTPUT ;
    USE SIGNAL ;
    PORT
      LAYER M4 ;
        RECT  0 37.872 0.084 37.896 ;
    END
  END o_data[240]
  PIN o_data[241]
    DIRECTION OUTPUT ;
    USE SIGNAL ;
    PORT
      LAYER M4 ;
        RECT  0 37.968 0.084 37.992 ;
    END
  END o_data[241]
  PIN o_data[242]
    DIRECTION OUTPUT ;
    USE SIGNAL ;
    PORT
      LAYER M4 ;
        RECT  0 38.064 0.084 38.088 ;
    END
  END o_data[242]
  PIN o_data[243]
    DIRECTION OUTPUT ;
    USE SIGNAL ;
    PORT
      LAYER M4 ;
        RECT  0 38.16 0.084 38.184 ;
    END
  END o_data[243]
  PIN o_data[244]
    DIRECTION OUTPUT ;
    USE SIGNAL ;
    PORT
      LAYER M4 ;
        RECT  0 38.256 0.084 38.28 ;
    END
  END o_data[244]
  PIN o_data[245]
    DIRECTION OUTPUT ;
    USE SIGNAL ;
    PORT
      LAYER M4 ;
        RECT  0 38.352 0.084 38.376 ;
    END
  END o_data[245]
  PIN o_data[246]
    DIRECTION OUTPUT ;
    USE SIGNAL ;
    PORT
      LAYER M4 ;
        RECT  0 38.448 0.084 38.472 ;
    END
  END o_data[246]
  PIN o_data[247]
    DIRECTION OUTPUT ;
    USE SIGNAL ;
    PORT
      LAYER M4 ;
        RECT  0 38.544 0.084 38.568 ;
    END
  END o_data[247]
  PIN o_data[248]
    DIRECTION OUTPUT ;
    USE SIGNAL ;
    PORT
      LAYER M4 ;
        RECT  0 38.64 0.084 38.664 ;
    END
  END o_data[248]
  PIN o_data[249]
    DIRECTION OUTPUT ;
    USE SIGNAL ;
    PORT
      LAYER M4 ;
        RECT  0 38.736 0.084 38.76 ;
    END
  END o_data[249]
  PIN o_data[24]
    DIRECTION OUTPUT ;
    USE SIGNAL ;
    PORT
      LAYER M4 ;
        RECT  0 26.352 0.084 26.376 ;
    END
  END o_data[24]
  PIN o_data[250]
    DIRECTION OUTPUT ;
    USE SIGNAL ;
    PORT
      LAYER M4 ;
        RECT  0 38.832 0.084 38.856 ;
    END
  END o_data[250]
  PIN o_data[251]
    DIRECTION OUTPUT ;
    USE SIGNAL ;
    PORT
      LAYER M4 ;
        RECT  0 38.928 0.084 38.952 ;
    END
  END o_data[251]
  PIN o_data[252]
    DIRECTION OUTPUT ;
    USE SIGNAL ;
    PORT
      LAYER M4 ;
        RECT  0 39.024 0.084 39.048 ;
    END
  END o_data[252]
  PIN o_data[253]
    DIRECTION OUTPUT ;
    USE SIGNAL ;
    PORT
      LAYER M4 ;
        RECT  0 39.12 0.084 39.144 ;
    END
  END o_data[253]
  PIN o_data[254]
    DIRECTION OUTPUT ;
    USE SIGNAL ;
    PORT
      LAYER M4 ;
        RECT  0 39.216 0.084 39.24 ;
    END
  END o_data[254]
  PIN o_data[255]
    DIRECTION OUTPUT ;
    USE SIGNAL ;
    PORT
      LAYER M4 ;
        RECT  0 39.312 0.084 39.336 ;
    END
  END o_data[255]
  PIN o_data[25]
    DIRECTION OUTPUT ;
    USE SIGNAL ;
    PORT
      LAYER M4 ;
        RECT  0 26.448 0.084 26.472 ;
    END
  END o_data[25]
  PIN o_data[26]
    DIRECTION OUTPUT ;
    USE SIGNAL ;
    PORT
      LAYER M4 ;
        RECT  0 26.544 0.084 26.568 ;
    END
  END o_data[26]
  PIN o_data[27]
    DIRECTION OUTPUT ;
    USE SIGNAL ;
    PORT
      LAYER M4 ;
        RECT  0 26.64 0.084 26.664 ;
    END
  END o_data[27]
  PIN o_data[28]
    DIRECTION OUTPUT ;
    USE SIGNAL ;
    PORT
      LAYER M4 ;
        RECT  0 26.736 0.084 26.76 ;
    END
  END o_data[28]
  PIN o_data[29]
    DIRECTION OUTPUT ;
    USE SIGNAL ;
    PORT
      LAYER M4 ;
        RECT  0 26.832 0.084 26.856 ;
    END
  END o_data[29]
  PIN o_data[2]
    DIRECTION OUTPUT ;
    USE SIGNAL ;
    PORT
      LAYER M4 ;
        RECT  0 24.24 0.084 24.264 ;
    END
  END o_data[2]
  PIN o_data[30]
    DIRECTION OUTPUT ;
    USE SIGNAL ;
    PORT
      LAYER M4 ;
        RECT  0 26.928 0.084 26.952 ;
    END
  END o_data[30]
  PIN o_data[31]
    DIRECTION OUTPUT ;
    USE SIGNAL ;
    PORT
      LAYER M4 ;
        RECT  0 27.024 0.084 27.048 ;
    END
  END o_data[31]
  PIN o_data[32]
    DIRECTION OUTPUT ;
    USE SIGNAL ;
    PORT
      LAYER M4 ;
        RECT  0 10.992 0.084 11.016 ;
    END
  END o_data[32]
  PIN o_data[33]
    DIRECTION OUTPUT ;
    USE SIGNAL ;
    PORT
      LAYER M4 ;
        RECT  0 11.088 0.084 11.112 ;
    END
  END o_data[33]
  PIN o_data[34]
    DIRECTION OUTPUT ;
    USE SIGNAL ;
    PORT
      LAYER M4 ;
        RECT  0 11.184 0.084 11.208 ;
    END
  END o_data[34]
  PIN o_data[35]
    DIRECTION OUTPUT ;
    USE SIGNAL ;
    PORT
      LAYER M4 ;
        RECT  0 11.28 0.084 11.304 ;
    END
  END o_data[35]
  PIN o_data[36]
    DIRECTION OUTPUT ;
    USE SIGNAL ;
    PORT
      LAYER M4 ;
        RECT  0 11.376 0.084 11.4 ;
    END
  END o_data[36]
  PIN o_data[37]
    DIRECTION OUTPUT ;
    USE SIGNAL ;
    PORT
      LAYER M4 ;
        RECT  0 11.472 0.084 11.496 ;
    END
  END o_data[37]
  PIN o_data[38]
    DIRECTION OUTPUT ;
    USE SIGNAL ;
    PORT
      LAYER M4 ;
        RECT  0 11.568 0.084 11.592 ;
    END
  END o_data[38]
  PIN o_data[39]
    DIRECTION OUTPUT ;
    USE SIGNAL ;
    PORT
      LAYER M4 ;
        RECT  0 11.664 0.084 11.688 ;
    END
  END o_data[39]
  PIN o_data[3]
    DIRECTION OUTPUT ;
    USE SIGNAL ;
    PORT
      LAYER M4 ;
        RECT  0 24.336 0.084 24.36 ;
    END
  END o_data[3]
  PIN o_data[40]
    DIRECTION OUTPUT ;
    USE SIGNAL ;
    PORT
      LAYER M4 ;
        RECT  0 11.76 0.084 11.784 ;
    END
  END o_data[40]
  PIN o_data[41]
    DIRECTION OUTPUT ;
    USE SIGNAL ;
    PORT
      LAYER M4 ;
        RECT  0 11.856 0.084 11.88 ;
    END
  END o_data[41]
  PIN o_data[42]
    DIRECTION OUTPUT ;
    USE SIGNAL ;
    PORT
      LAYER M4 ;
        RECT  0 11.952 0.084 11.976 ;
    END
  END o_data[42]
  PIN o_data[43]
    DIRECTION OUTPUT ;
    USE SIGNAL ;
    PORT
      LAYER M4 ;
        RECT  0 12.048 0.084 12.072 ;
    END
  END o_data[43]
  PIN o_data[44]
    DIRECTION OUTPUT ;
    USE SIGNAL ;
    PORT
      LAYER M4 ;
        RECT  0 12.144 0.084 12.168 ;
    END
  END o_data[44]
  PIN o_data[45]
    DIRECTION OUTPUT ;
    USE SIGNAL ;
    PORT
      LAYER M4 ;
        RECT  0 12.24 0.084 12.264 ;
    END
  END o_data[45]
  PIN o_data[46]
    DIRECTION OUTPUT ;
    USE SIGNAL ;
    PORT
      LAYER M4 ;
        RECT  0 12.336 0.084 12.36 ;
    END
  END o_data[46]
  PIN o_data[47]
    DIRECTION OUTPUT ;
    USE SIGNAL ;
    PORT
      LAYER M4 ;
        RECT  0 12.432 0.084 12.456 ;
    END
  END o_data[47]
  PIN o_data[48]
    DIRECTION OUTPUT ;
    USE SIGNAL ;
    PORT
      LAYER M4 ;
        RECT  0 12.528 0.084 12.552 ;
    END
  END o_data[48]
  PIN o_data[49]
    DIRECTION OUTPUT ;
    USE SIGNAL ;
    PORT
      LAYER M4 ;
        RECT  0 12.624 0.084 12.648 ;
    END
  END o_data[49]
  PIN o_data[4]
    DIRECTION OUTPUT ;
    USE SIGNAL ;
    PORT
      LAYER M4 ;
        RECT  0 24.432 0.084 24.456 ;
    END
  END o_data[4]
  PIN o_data[50]
    DIRECTION OUTPUT ;
    USE SIGNAL ;
    PORT
      LAYER M4 ;
        RECT  0 12.72 0.084 12.744 ;
    END
  END o_data[50]
  PIN o_data[51]
    DIRECTION OUTPUT ;
    USE SIGNAL ;
    PORT
      LAYER M4 ;
        RECT  0 12.816 0.084 12.84 ;
    END
  END o_data[51]
  PIN o_data[52]
    DIRECTION OUTPUT ;
    USE SIGNAL ;
    PORT
      LAYER M4 ;
        RECT  0 12.912 0.084 12.936 ;
    END
  END o_data[52]
  PIN o_data[53]
    DIRECTION OUTPUT ;
    USE SIGNAL ;
    PORT
      LAYER M4 ;
        RECT  0 13.008 0.084 13.032 ;
    END
  END o_data[53]
  PIN o_data[54]
    DIRECTION OUTPUT ;
    USE SIGNAL ;
    PORT
      LAYER M4 ;
        RECT  0 13.104 0.084 13.128 ;
    END
  END o_data[54]
  PIN o_data[55]
    DIRECTION OUTPUT ;
    USE SIGNAL ;
    PORT
      LAYER M4 ;
        RECT  0 13.2 0.084 13.224 ;
    END
  END o_data[55]
  PIN o_data[56]
    DIRECTION OUTPUT ;
    USE SIGNAL ;
    PORT
      LAYER M4 ;
        RECT  0 13.296 0.084 13.32 ;
    END
  END o_data[56]
  PIN o_data[57]
    DIRECTION OUTPUT ;
    USE SIGNAL ;
    PORT
      LAYER M4 ;
        RECT  0 13.392 0.084 13.416 ;
    END
  END o_data[57]
  PIN o_data[58]
    DIRECTION OUTPUT ;
    USE SIGNAL ;
    PORT
      LAYER M4 ;
        RECT  0 13.488 0.084 13.512 ;
    END
  END o_data[58]
  PIN o_data[59]
    DIRECTION OUTPUT ;
    USE SIGNAL ;
    PORT
      LAYER M4 ;
        RECT  0 13.584 0.084 13.608 ;
    END
  END o_data[59]
  PIN o_data[5]
    DIRECTION OUTPUT ;
    USE SIGNAL ;
    PORT
      LAYER M4 ;
        RECT  0 24.528 0.084 24.552 ;
    END
  END o_data[5]
  PIN o_data[60]
    DIRECTION OUTPUT ;
    USE SIGNAL ;
    PORT
      LAYER M4 ;
        RECT  0 13.68 0.084 13.704 ;
    END
  END o_data[60]
  PIN o_data[61]
    DIRECTION OUTPUT ;
    USE SIGNAL ;
    PORT
      LAYER M4 ;
        RECT  0 13.776 0.084 13.8 ;
    END
  END o_data[61]
  PIN o_data[62]
    DIRECTION OUTPUT ;
    USE SIGNAL ;
    PORT
      LAYER M4 ;
        RECT  0 13.872 0.084 13.896 ;
    END
  END o_data[62]
  PIN o_data[63]
    DIRECTION OUTPUT ;
    USE SIGNAL ;
    PORT
      LAYER M4 ;
        RECT  0 13.968 0.084 13.992 ;
    END
  END o_data[63]
  PIN o_data[64]
    DIRECTION OUTPUT ;
    USE SIGNAL ;
    PORT
      LAYER M4 ;
        RECT  0 4.848 0.084 4.872 ;
    END
  END o_data[64]
  PIN o_data[65]
    DIRECTION OUTPUT ;
    USE SIGNAL ;
    PORT
      LAYER M4 ;
        RECT  0 4.944 0.084 4.968 ;
    END
  END o_data[65]
  PIN o_data[66]
    DIRECTION OUTPUT ;
    USE SIGNAL ;
    PORT
      LAYER M4 ;
        RECT  0 5.04 0.084 5.064 ;
    END
  END o_data[66]
  PIN o_data[67]
    DIRECTION OUTPUT ;
    USE SIGNAL ;
    PORT
      LAYER M4 ;
        RECT  0 5.136 0.084 5.16 ;
    END
  END o_data[67]
  PIN o_data[68]
    DIRECTION OUTPUT ;
    USE SIGNAL ;
    PORT
      LAYER M4 ;
        RECT  0 5.232 0.084 5.256 ;
    END
  END o_data[68]
  PIN o_data[69]
    DIRECTION OUTPUT ;
    USE SIGNAL ;
    PORT
      LAYER M4 ;
        RECT  0 5.328 0.084 5.352 ;
    END
  END o_data[69]
  PIN o_data[6]
    DIRECTION OUTPUT ;
    USE SIGNAL ;
    PORT
      LAYER M4 ;
        RECT  0 24.624 0.084 24.648 ;
    END
  END o_data[6]
  PIN o_data[70]
    DIRECTION OUTPUT ;
    USE SIGNAL ;
    PORT
      LAYER M4 ;
        RECT  0 5.424 0.084 5.448 ;
    END
  END o_data[70]
  PIN o_data[71]
    DIRECTION OUTPUT ;
    USE SIGNAL ;
    PORT
      LAYER M4 ;
        RECT  0 5.52 0.084 5.544 ;
    END
  END o_data[71]
  PIN o_data[72]
    DIRECTION OUTPUT ;
    USE SIGNAL ;
    PORT
      LAYER M4 ;
        RECT  0 5.616 0.084 5.64 ;
    END
  END o_data[72]
  PIN o_data[73]
    DIRECTION OUTPUT ;
    USE SIGNAL ;
    PORT
      LAYER M4 ;
        RECT  0 5.712 0.084 5.736 ;
    END
  END o_data[73]
  PIN o_data[74]
    DIRECTION OUTPUT ;
    USE SIGNAL ;
    PORT
      LAYER M4 ;
        RECT  0 5.808 0.084 5.832 ;
    END
  END o_data[74]
  PIN o_data[75]
    DIRECTION OUTPUT ;
    USE SIGNAL ;
    PORT
      LAYER M4 ;
        RECT  0 5.904 0.084 5.928 ;
    END
  END o_data[75]
  PIN o_data[76]
    DIRECTION OUTPUT ;
    USE SIGNAL ;
    PORT
      LAYER M4 ;
        RECT  0 6 0.084 6.024 ;
    END
  END o_data[76]
  PIN o_data[77]
    DIRECTION OUTPUT ;
    USE SIGNAL ;
    PORT
      LAYER M4 ;
        RECT  0 6.096 0.084 6.12 ;
    END
  END o_data[77]
  PIN o_data[78]
    DIRECTION OUTPUT ;
    USE SIGNAL ;
    PORT
      LAYER M4 ;
        RECT  0 6.192 0.084 6.216 ;
    END
  END o_data[78]
  PIN o_data[79]
    DIRECTION OUTPUT ;
    USE SIGNAL ;
    PORT
      LAYER M4 ;
        RECT  0 6.288 0.084 6.312 ;
    END
  END o_data[79]
  PIN o_data[7]
    DIRECTION OUTPUT ;
    USE SIGNAL ;
    PORT
      LAYER M4 ;
        RECT  0 24.72 0.084 24.744 ;
    END
  END o_data[7]
  PIN o_data[80]
    DIRECTION OUTPUT ;
    USE SIGNAL ;
    PORT
      LAYER M4 ;
        RECT  0 6.384 0.084 6.408 ;
    END
  END o_data[80]
  PIN o_data[81]
    DIRECTION OUTPUT ;
    USE SIGNAL ;
    PORT
      LAYER M4 ;
        RECT  0 6.48 0.084 6.504 ;
    END
  END o_data[81]
  PIN o_data[82]
    DIRECTION OUTPUT ;
    USE SIGNAL ;
    PORT
      LAYER M4 ;
        RECT  0 6.576 0.084 6.6 ;
    END
  END o_data[82]
  PIN o_data[83]
    DIRECTION OUTPUT ;
    USE SIGNAL ;
    PORT
      LAYER M4 ;
        RECT  0 6.672 0.084 6.696 ;
    END
  END o_data[83]
  PIN o_data[84]
    DIRECTION OUTPUT ;
    USE SIGNAL ;
    PORT
      LAYER M4 ;
        RECT  0 6.768 0.084 6.792 ;
    END
  END o_data[84]
  PIN o_data[85]
    DIRECTION OUTPUT ;
    USE SIGNAL ;
    PORT
      LAYER M4 ;
        RECT  0 6.864 0.084 6.888 ;
    END
  END o_data[85]
  PIN o_data[86]
    DIRECTION OUTPUT ;
    USE SIGNAL ;
    PORT
      LAYER M4 ;
        RECT  0 6.96 0.084 6.984 ;
    END
  END o_data[86]
  PIN o_data[87]
    DIRECTION OUTPUT ;
    USE SIGNAL ;
    PORT
      LAYER M4 ;
        RECT  0 7.056 0.084 7.08 ;
    END
  END o_data[87]
  PIN o_data[88]
    DIRECTION OUTPUT ;
    USE SIGNAL ;
    PORT
      LAYER M4 ;
        RECT  0 7.152 0.084 7.176 ;
    END
  END o_data[88]
  PIN o_data[89]
    DIRECTION OUTPUT ;
    USE SIGNAL ;
    PORT
      LAYER M4 ;
        RECT  0 7.248 0.084 7.272 ;
    END
  END o_data[89]
  PIN o_data[8]
    DIRECTION OUTPUT ;
    USE SIGNAL ;
    PORT
      LAYER M4 ;
        RECT  0 24.816 0.084 24.84 ;
    END
  END o_data[8]
  PIN o_data[90]
    DIRECTION OUTPUT ;
    USE SIGNAL ;
    PORT
      LAYER M4 ;
        RECT  0 7.344 0.084 7.368 ;
    END
  END o_data[90]
  PIN o_data[91]
    DIRECTION OUTPUT ;
    USE SIGNAL ;
    PORT
      LAYER M4 ;
        RECT  0 7.44 0.084 7.464 ;
    END
  END o_data[91]
  PIN o_data[92]
    DIRECTION OUTPUT ;
    USE SIGNAL ;
    PORT
      LAYER M4 ;
        RECT  0 7.536 0.084 7.56 ;
    END
  END o_data[92]
  PIN o_data[93]
    DIRECTION OUTPUT ;
    USE SIGNAL ;
    PORT
      LAYER M4 ;
        RECT  0 7.632 0.084 7.656 ;
    END
  END o_data[93]
  PIN o_data[94]
    DIRECTION OUTPUT ;
    USE SIGNAL ;
    PORT
      LAYER M4 ;
        RECT  0 7.728 0.084 7.752 ;
    END
  END o_data[94]
  PIN o_data[95]
    DIRECTION OUTPUT ;
    USE SIGNAL ;
    PORT
      LAYER M4 ;
        RECT  0 7.824 0.084 7.848 ;
    END
  END o_data[95]
  PIN o_data[96]
    DIRECTION OUTPUT ;
    USE SIGNAL ;
    PORT
      LAYER M4 ;
        RECT  0 7.92 0.084 7.944 ;
    END
  END o_data[96]
  PIN o_data[97]
    DIRECTION OUTPUT ;
    USE SIGNAL ;
    PORT
      LAYER M4 ;
        RECT  0 8.016 0.084 8.04 ;
    END
  END o_data[97]
  PIN o_data[98]
    DIRECTION OUTPUT ;
    USE SIGNAL ;
    PORT
      LAYER M4 ;
        RECT  0 8.112 0.084 8.136 ;
    END
  END o_data[98]
  PIN o_data[99]
    DIRECTION OUTPUT ;
    USE SIGNAL ;
    PORT
      LAYER M4 ;
        RECT  0 8.208 0.084 8.232 ;
    END
  END o_data[99]
  PIN o_data[9]
    DIRECTION OUTPUT ;
    USE SIGNAL ;
    PORT
      LAYER M4 ;
        RECT  0 24.912 0.084 24.936 ;
    END
  END o_data[9]
  PIN o_row[0]
    DIRECTION OUTPUT ;
    USE SIGNAL ;
    PORT
      LAYER M4 ;
        RECT  0 33.84 0.084 33.864 ;
    END
  END o_row[0]
  PIN o_row[1]
    DIRECTION OUTPUT ;
    USE SIGNAL ;
    PORT
      LAYER M4 ;
        RECT  0 33.936 0.084 33.96 ;
    END
  END o_row[1]
  PIN o_row[2]
    DIRECTION OUTPUT ;
    USE SIGNAL ;
    PORT
      LAYER M4 ;
        RECT  0 34.032 0.084 34.056 ;
    END
  END o_row[2]
  PIN o_row[3]
    DIRECTION OUTPUT ;
    USE SIGNAL ;
    PORT
      LAYER M4 ;
        RECT  0 34.128 0.084 34.152 ;
    END
  END o_row[3]
  PIN o_row[4]
    DIRECTION OUTPUT ;
    USE SIGNAL ;
    PORT
      LAYER M4 ;
        RECT  0 34.224 0.084 34.248 ;
    END
  END o_row[4]
  PIN o_row[5]
    DIRECTION OUTPUT ;
    USE SIGNAL ;
    PORT
      LAYER M4 ;
        RECT  0 34.32 0.084 34.344 ;
    END
  END o_row[5]
  PIN o_row[6]
    DIRECTION OUTPUT ;
    USE SIGNAL ;
    PORT
      LAYER M4 ;
        RECT  0 34.416 0.084 34.44 ;
    END
  END o_row[6]
  PIN o_row[7]
    DIRECTION OUTPUT ;
    USE SIGNAL ;
    PORT
      LAYER M4 ;
        RECT  0 34.512 0.084 34.536 ;
    END
  END o_row[7]
  PIN o_sec[0]
    DIRECTION OUTPUT ;
    USE SIGNAL ;
    PORT
      LAYER M4 ;
        RECT  0 34.608 0.084 34.632 ;
    END
  END o_sec[0]
  PIN o_sec[10]
    DIRECTION OUTPUT ;
    USE SIGNAL ;
    PORT
      LAYER M4 ;
        RECT  0 35.568 0.084 35.592 ;
    END
  END o_sec[10]
  PIN o_sec[11]
    DIRECTION OUTPUT ;
    USE SIGNAL ;
    PORT
      LAYER M4 ;
        RECT  0 35.664 0.084 35.688 ;
    END
  END o_sec[11]
  PIN o_sec[12]
    DIRECTION OUTPUT ;
    USE SIGNAL ;
    PORT
      LAYER M4 ;
        RECT  0 35.76 0.084 35.784 ;
    END
  END o_sec[12]
  PIN o_sec[13]
    DIRECTION OUTPUT ;
    USE SIGNAL ;
    PORT
      LAYER M4 ;
        RECT  0 35.856 0.084 35.88 ;
    END
  END o_sec[13]
  PIN o_sec[14]
    DIRECTION OUTPUT ;
    USE SIGNAL ;
    PORT
      LAYER M4 ;
        RECT  0 35.952 0.084 35.976 ;
    END
  END o_sec[14]
  PIN o_sec[15]
    DIRECTION OUTPUT ;
    USE SIGNAL ;
    PORT
      LAYER M4 ;
        RECT  0 36.048 0.084 36.072 ;
    END
  END o_sec[15]
  PIN o_sec[16]
    DIRECTION OUTPUT ;
    USE SIGNAL ;
    PORT
      LAYER M4 ;
        RECT  0 36.144 0.084 36.168 ;
    END
  END o_sec[16]
  PIN o_sec[1]
    DIRECTION OUTPUT ;
    USE SIGNAL ;
    PORT
      LAYER M4 ;
        RECT  0 34.704 0.084 34.728 ;
    END
  END o_sec[1]
  PIN o_sec[2]
    DIRECTION OUTPUT ;
    USE SIGNAL ;
    PORT
      LAYER M4 ;
        RECT  0 34.8 0.084 34.824 ;
    END
  END o_sec[2]
  PIN o_sec[3]
    DIRECTION OUTPUT ;
    USE SIGNAL ;
    PORT
      LAYER M4 ;
        RECT  0 34.896 0.084 34.92 ;
    END
  END o_sec[3]
  PIN o_sec[4]
    DIRECTION OUTPUT ;
    USE SIGNAL ;
    PORT
      LAYER M4 ;
        RECT  0 34.992 0.084 35.016 ;
    END
  END o_sec[4]
  PIN o_sec[5]
    DIRECTION OUTPUT ;
    USE SIGNAL ;
    PORT
      LAYER M4 ;
        RECT  0 35.088 0.084 35.112 ;
    END
  END o_sec[5]
  PIN o_sec[6]
    DIRECTION OUTPUT ;
    USE SIGNAL ;
    PORT
      LAYER M4 ;
        RECT  0 35.184 0.084 35.208 ;
    END
  END o_sec[6]
  PIN o_sec[7]
    DIRECTION OUTPUT ;
    USE SIGNAL ;
    PORT
      LAYER M4 ;
        RECT  0 35.28 0.084 35.304 ;
    END
  END o_sec[7]
  PIN o_sec[8]
    DIRECTION OUTPUT ;
    USE SIGNAL ;
    PORT
      LAYER M4 ;
        RECT  0 35.376 0.084 35.4 ;
    END
  END o_sec[8]
  PIN o_sec[9]
    DIRECTION OUTPUT ;
    USE SIGNAL ;
    PORT
      LAYER M4 ;
        RECT  0 35.472 0.084 35.496 ;
    END
  END o_sec[9]
  PIN o_v
    DIRECTION OUTPUT ;
    USE SIGNAL ;
    PORT
      LAYER M4 ;
        RECT  0 36.24 0.084 36.264 ;
    END
  END o_v
  PIN ue
    DIRECTION OUTPUT ;
    USE SIGNAL ;
    PORT
      LAYER M5 ;
        RECT  23.952 43.116 23.976 43.2 ;
    END
  END ue
  PIN VDD
    DIRECTION INOUT ;
    USE POWER ;
    PORT
      LAYER M5 ;
        RECT  40.392 2.151 40.512 41.049 ;
        RECT  34.992 2.151 35.112 41.049 ;
        RECT  29.592 2.151 29.712 41.049 ;
        RECT  24.192 2.151 24.312 41.049 ;
        RECT  18.792 2.151 18.912 41.049 ;
        RECT  13.392 2.151 13.512 41.049 ;
        RECT  7.992 2.151 8.112 41.049 ;
        RECT  2.592 2.151 2.712 41.049 ;
    END
  END VDD
  PIN VSS
    DIRECTION INOUT ;
    USE GROUND ;
    PORT
      LAYER M5 ;
        RECT  40.2 2.137 40.32 41.063 ;
        RECT  34.8 2.137 34.92 41.063 ;
        RECT  29.4 2.137 29.52 41.063 ;
        RECT  24 2.137 24.12 41.063 ;
        RECT  18.6 2.137 18.72 41.063 ;
        RECT  13.2 2.137 13.32 41.063 ;
        RECT  7.8 2.137 7.92 41.063 ;
        RECT  2.4 2.137 2.52 41.063 ;
    END
  END VSS
  OBS
    LAYER RVTN ;
     RECT  2.16 2.16 41.04 2.295 ;
     RECT  2.16 2.565 41.04 2.835 ;
     RECT  2.16 3.105 41.04 3.375 ;
     RECT  2.16 3.645 41.04 3.915 ;
     RECT  2.16 4.185 41.04 4.455 ;
     RECT  2.16 4.725 41.04 4.995 ;
     RECT  2.16 5.265 41.04 5.535 ;
     RECT  2.16 5.805 41.04 6.075 ;
     RECT  2.16 6.345 41.04 6.615 ;
     RECT  2.16 6.885 41.04 7.155 ;
     RECT  2.16 7.425 41.04 7.695 ;
     RECT  2.16 7.965 41.04 8.235 ;
     RECT  2.16 8.505 41.04 8.775 ;
     RECT  2.16 9.045 41.04 9.315 ;
     RECT  2.16 9.585 41.04 9.855 ;
     RECT  2.16 10.125 41.04 10.395 ;
     RECT  2.16 10.665 41.04 10.935 ;
     RECT  2.16 11.205 41.04 11.475 ;
     RECT  2.16 11.745 41.04 12.015 ;
     RECT  2.16 12.285 41.04 12.555 ;
     RECT  2.16 12.825 41.04 13.095 ;
     RECT  2.16 13.365 41.04 13.635 ;
     RECT  2.16 13.905 41.04 14.175 ;
     RECT  2.16 14.445 41.04 14.715 ;
     RECT  2.16 14.985 41.04 15.255 ;
     RECT  2.16 15.525 41.04 15.795 ;
     RECT  2.16 16.065 41.04 16.335 ;
     RECT  2.16 16.605 41.04 16.875 ;
     RECT  2.16 17.145 41.04 17.415 ;
     RECT  2.16 17.685 41.04 17.955 ;
     RECT  2.16 18.225 41.04 18.495 ;
     RECT  2.16 18.765 41.04 19.035 ;
     RECT  2.16 19.305 41.04 19.575 ;
     RECT  2.16 19.845 41.04 20.115 ;
     RECT  2.16 20.385 41.04 20.655 ;
     RECT  2.16 20.925 41.04 21.195 ;
     RECT  2.16 21.465 41.04 21.735 ;
     RECT  2.16 22.005 41.04 22.275 ;
     RECT  2.16 22.545 41.04 22.815 ;
     RECT  2.16 23.085 41.04 23.355 ;
     RECT  2.16 23.625 41.04 23.895 ;
     RECT  2.16 24.165 41.04 24.435 ;
     RECT  2.16 24.705 41.04 24.975 ;
     RECT  2.16 25.245 41.04 25.515 ;
     RECT  2.16 25.785 41.04 26.055 ;
     RECT  2.16 26.325 41.04 26.595 ;
     RECT  2.16 26.865 41.04 27.135 ;
     RECT  2.16 27.405 41.04 27.675 ;
     RECT  2.16 27.945 41.04 28.215 ;
     RECT  2.16 28.485 41.04 28.755 ;
     RECT  2.16 29.025 41.04 29.295 ;
     RECT  2.16 29.565 41.04 29.835 ;
     RECT  2.16 30.105 41.04 30.375 ;
     RECT  2.16 30.645 41.04 30.915 ;
     RECT  2.16 31.185 41.04 31.455 ;
     RECT  2.16 31.725 41.04 31.995 ;
     RECT  2.16 32.265 41.04 32.535 ;
     RECT  2.16 32.805 41.04 33.075 ;
     RECT  2.16 33.345 41.04 33.615 ;
     RECT  2.16 33.885 41.04 34.155 ;
     RECT  2.16 34.425 41.04 34.695 ;
     RECT  2.16 34.965 41.04 35.235 ;
     RECT  2.16 35.505 41.04 35.775 ;
     RECT  2.16 36.045 41.04 36.315 ;
     RECT  2.16 36.585 41.04 36.855 ;
     RECT  2.16 37.125 41.04 37.395 ;
     RECT  2.16 37.665 41.04 37.935 ;
     RECT  2.16 38.205 41.04 38.475 ;
     RECT  2.16 38.745 41.04 39.015 ;
     RECT  2.16 39.285 41.04 39.555 ;
     RECT  2.16 39.825 41.04 40.095 ;
     RECT  2.16 40.365 41.04 40.635 ;
     RECT  2.16 40.905 41.04 41.04 ;
    LAYER RVTP ;
     RECT  2.16 2.295 41.04 2.565 ;
     RECT  2.16 2.835 41.04 3.105 ;
     RECT  2.16 3.375 41.04 3.645 ;
     RECT  2.16 3.915 41.04 4.185 ;
     RECT  2.16 4.455 41.04 4.725 ;
     RECT  2.16 4.995 41.04 5.265 ;
     RECT  2.16 5.535 41.04 5.805 ;
     RECT  2.16 6.075 41.04 6.345 ;
     RECT  2.16 6.615 41.04 6.885 ;
     RECT  2.16 7.155 41.04 7.425 ;
     RECT  2.16 7.695 41.04 7.965 ;
     RECT  2.16 8.235 41.04 8.505 ;
     RECT  2.16 8.775 41.04 9.045 ;
     RECT  2.16 9.315 41.04 9.585 ;
     RECT  2.16 9.855 41.04 10.125 ;
     RECT  2.16 10.395 41.04 10.665 ;
     RECT  2.16 10.935 41.04 11.205 ;
     RECT  2.16 11.475 41.04 11.745 ;
     RECT  2.16 12.015 41.04 12.285 ;
     RECT  2.16 12.555 41.04 12.825 ;
     RECT  2.16 13.095 41.04 13.365 ;
     RECT  2.16 13.635 41.04 13.905 ;
     RECT  2.16 14.175 41.04 14.445 ;
     RECT  2.16 14.715 41.04 14.985 ;
     RECT  2.16 15.255 41.04 15.525 ;
     RECT  2.16 15.795 41.04 16.065 ;
     RECT  2.16 16.335 41.04 16.605 ;
     RECT  2.16 16.875 41.04 17.145 ;
     RECT  2.16 17.415 41.04 17.685 ;
     RECT  2.16 17.955 41.04 18.225 ;
     RECT  2.16 18.495 41.04 18.765 ;
     RECT  2.16 19.035 41.04 19.305 ;
     RECT  2.16 19.575 41.04 19.845 ;
     RECT  2.16 20.115 41.04 20.385 ;
     RECT  2.16 20.655 41.04 20.925 ;
     RECT  2.16 21.195 41.04 21.465 ;
     RECT  2.16 21.735 41.04 22.005 ;
     RECT  2.16 22.275 41.04 22.545 ;
     RECT  2.16 22.815 41.04 23.085 ;
     RECT  2.16 23.355 41.04 23.625 ;
     RECT  2.16 23.895 41.04 24.165 ;
     RECT  2.16 24.435 41.04 24.705 ;
     RECT  2.16 24.975 41.04 25.245 ;
     RECT  2.16 25.515 41.04 25.785 ;
     RECT  2.16 26.055 41.04 26.325 ;
     RECT  2.16 26.595 41.04 26.865 ;
     RECT  2.16 27.135 41.04 27.405 ;
     RECT  2.16 27.675 41.04 27.945 ;
     RECT  2.16 28.215 41.04 28.485 ;
     RECT  2.16 28.755 41.04 29.025 ;
     RECT  2.16 29.295 41.04 29.565 ;
     RECT  2.16 29.835 41.04 30.105 ;
     RECT  2.16 30.375 41.04 30.645 ;
     RECT  2.16 30.915 41.04 31.185 ;
     RECT  2.16 31.455 41.04 31.725 ;
     RECT  2.16 31.995 41.04 32.265 ;
     RECT  2.16 32.535 41.04 32.805 ;
     RECT  2.16 33.075 41.04 33.345 ;
     RECT  2.16 33.615 41.04 33.885 ;
     RECT  2.16 34.155 41.04 34.425 ;
     RECT  2.16 34.695 41.04 34.965 ;
     RECT  2.16 35.235 41.04 35.505 ;
     RECT  2.16 35.775 41.04 36.045 ;
     RECT  2.16 36.315 41.04 36.585 ;
     RECT  2.16 36.855 41.04 37.125 ;
     RECT  2.16 37.395 41.04 37.665 ;
     RECT  2.16 37.935 41.04 38.205 ;
     RECT  2.16 38.475 41.04 38.745 ;
     RECT  2.16 39.015 41.04 39.285 ;
     RECT  2.16 39.555 41.04 39.825 ;
     RECT  2.16 40.095 41.04 40.365 ;
     RECT  2.16 40.635 41.04 40.905 ;
    LAYER M1 ;
     RECT  2.16 2.151 41.04 41.049 ;
    LAYER M2 ;
     RECT  0.031 22.176 0.067 22.194 ;
     RECT  0.031 24.606 0.103 24.624 ;
     RECT  0.103 24.444 0.131 24.624 ;
     RECT  0.131 24.444 0.139 24.462 ;
     RECT  0.103 27.846 0.139 27.864 ;
     RECT  0.103 33.084 0.139 33.102 ;
     RECT  0.103 34.434 0.139 34.452 ;
     RECT  0.103 5.661 0.175 6.174 ;
     RECT  0.139 23.868 0.175 24.462 ;
     RECT  0.103 26.766 0.175 26.784 ;
     RECT  0.139 34.128 0.175 34.524 ;
     RECT  0.103 35.478 0.175 35.496 ;
     RECT  0.103 9.828 0.203 9.846 ;
     RECT  0.103 11.682 0.203 11.7 ;
     RECT  0.103 29.916 0.203 29.934 ;
     RECT  0.103 30.726 0.203 30.744 ;
     RECT  0.139 32.778 0.203 33.102 ;
     RECT  0.175 5.661 0.211 6.804 ;
     RECT  0.103 7.596 0.211 7.614 ;
     RECT  0.139 8.586 0.211 8.604 ;
     RECT  0.211 7.596 0.239 8.604 ;
     RECT  0.175 23.526 0.239 24.462 ;
     RECT  0.203 32.778 0.239 32.796 ;
     RECT  0.175 34.128 0.239 35.496 ;
     RECT  0.247 25.326 0.283 25.344 ;
     RECT  0.139 27.846 0.383 28.206 ;
     RECT  0.283 25.326 0.419 25.542 ;
     RECT  0.103 13.644 0.499 14.166 ;
     RECT  0.211 5.346 0.535 6.804 ;
     RECT  0.239 7.596 0.535 8.262 ;
     RECT  0.499 9.756 0.535 9.774 ;
     RECT  0.103 29.034 0.535 29.052 ;
     RECT  0.535 5.346 0.671 8.262 ;
     RECT  0.239 24.336 1.147 24.462 ;
     RECT  0.419 25.326 1.147 25.344 ;
     RECT  0.383 27.846 1.147 27.864 ;
     RECT  1.147 27.846 1.175 27.936 ;
     RECT  0.067 22.176 1.183 22.734 ;
     RECT  0.239 23.526 1.183 23.544 ;
     RECT  1.183 22.176 1.219 23.544 ;
     RECT  1.147 24.336 1.219 25.344 ;
     RECT  1.147 3.384 1.399 3.402 ;
     RECT  1.183 4.356 1.399 4.374 ;
     RECT  1.147 18.396 1.723 18.414 ;
     RECT  0.175 26.766 1.723 27.054 ;
     RECT  1.723 17.928 1.759 18.414 ;
     RECT  1.723 40.068 1.975 40.086 ;
     RECT  1.759 17.226 2.119 18.414 ;
     RECT  2.119 17.154 2.155 18.414 ;
     RECT  1.399 3.384 2.16 4.374 ;
     RECT  0.671 5.346 2.16 7.956 ;
     RECT  0.535 9.558 2.16 9.774 ;
     RECT  0.535 12.186 2.16 12.204 ;
     RECT  0.499 13.338 2.16 14.166 ;
     RECT  2.155 16.776 2.16 18.414 ;
     RECT  1.219 22.176 2.16 25.344 ;
     RECT  1.723 26.496 2.16 27.054 ;
     RECT  1.175 27.918 2.16 27.936 ;
     RECT  0.535 29.034 2.16 29.214 ;
     RECT  0.427 30.15 2.16 30.636 ;
     RECT  0.535 31.896 2.16 31.914 ;
     RECT  0.239 34.74 2.16 34.884 ;
     RECT  1.975 40.068 2.16 40.554 ;
     RECT  2.16 2.151 41.04 41.049 ;
     RECT  41.04 3.15 41.639 19.908 ;
     RECT  41.04 22.59 41.639 39.276 ;
     RECT  41.639 3.15 41.675 16.056 ;
     RECT  41.639 16.848 41.675 19.908 ;
     RECT  41.639 25.218 41.819 39.276 ;
     RECT  41.819 29.808 41.855 39.276 ;
     RECT  41.855 30.888 42.035 39.276 ;
     RECT  41.675 3.15 42.179 14.742 ;
     RECT  41.675 15.57 42.179 16.056 ;
     RECT  41.675 16.92 42.179 19.908 ;
     RECT  41.639 22.59 42.179 24.426 ;
     RECT  41.819 25.218 42.179 26.316 ;
     RECT  41.819 27.108 42.179 29.052 ;
     RECT  41.855 29.808 42.179 30.132 ;
     RECT  42.035 30.888 42.179 38.736 ;
     RECT  42.179 3.15 42.215 3.978 ;
     RECT  42.179 8.514 42.215 8.532 ;
     RECT  42.179 10.44 42.215 11.268 ;
     RECT  42.179 12.636 42.215 13.086 ;
     RECT  42.179 13.986 42.215 14.508 ;
     RECT  42.179 15.57 42.215 15.822 ;
     RECT  42.179 16.92 42.215 16.974 ;
     RECT  42.179 18 42.215 18.054 ;
     RECT  42.179 19.89 42.215 19.908 ;
     RECT  42.179 28.296 42.215 29.052 ;
     RECT  42.179 30.114 42.215 30.132 ;
     RECT  42.179 36.054 42.215 36.072 ;
     RECT  42.215 3.15 42.251 3.168 ;
     RECT  42.179 6.12 42.251 7.524 ;
     RECT  42.215 13.986 42.251 14.004 ;
     RECT  42.215 15.804 42.251 15.822 ;
     RECT  42.251 6.39 42.287 7.524 ;
     RECT  42.179 23.328 42.287 24.228 ;
     RECT  42.215 12.798 42.899 13.086 ;
     RECT  42.215 18.036 42.971 18.054 ;
     RECT  42.287 6.696 43.043 7.524 ;
     RECT  42.899 12.798 43.043 12.816 ;
     RECT  42.179 25.218 43.043 25.506 ;
     RECT  42.179 26.298 43.043 26.316 ;
     RECT  42.179 33.858 43.043 33.876 ;
     RECT  42.179 34.938 43.043 35.028 ;
     RECT  42.179 37.098 43.043 37.116 ;
     RECT  42.215 3.96 43.079 3.978 ;
     RECT  42.215 10.872 43.079 11.268 ;
     RECT  42.179 38.016 43.079 38.574 ;
     RECT  43.043 6.696 43.115 6.84 ;
     RECT  43.079 11.25 43.115 11.268 ;
     RECT  42.215 16.956 43.115 16.974 ;
     RECT  42.179 19.008 43.115 19.026 ;
     RECT  42.287 23.328 43.115 23.346 ;
     RECT  42.287 24.21 43.115 24.228 ;
     RECT  43.043 25.488 43.115 25.506 ;
     RECT  42.179 27.216 43.115 27.504 ;
     RECT  42.179 31.536 43.115 31.752 ;
     RECT  42.179 32.886 43.115 32.904 ;
     RECT  43.043 35.01 43.115 35.028 ;
     RECT  43.079 38.016 43.115 38.034 ;
    LAYER M3 ;
     RECT  2.415 2.143 2.505 2.413 ;
     RECT  7.815 2.143 7.905 2.413 ;
     RECT  13.215 2.143 13.305 2.413 ;
     RECT  18.615 2.143 18.705 2.413 ;
     RECT  24.015 2.143 24.105 2.413 ;
     RECT  29.415 2.143 29.505 2.413 ;
     RECT  34.815 2.143 34.905 2.413 ;
     RECT  40.215 2.143 40.305 2.413 ;
     RECT  3.708 2.533 3.726 2.569 ;
     RECT  3.708 2.569 3.798 2.641 ;
     RECT  2.415 2.413 2.697 2.731 ;
     RECT  3.564 2.641 3.798 2.731 ;
     RECT  2.415 2.731 3.978 2.803 ;
     RECT  40.215 2.413 40.497 2.803 ;
     RECT  2.415 2.803 4.158 2.839 ;
     RECT  40.215 2.803 40.734 2.911 ;
     RECT  2.415 2.839 4.41 3.001 ;
     RECT  18.615 2.413 18.897 3.181 ;
     RECT  34.815 2.413 35.097 3.181 ;
     RECT  2.415 3.001 5.058 3.271 ;
     RECT  2.376 3.271 5.058 3.307 ;
     RECT  38.376 3.307 38.502 3.343 ;
     RECT  38.376 3.343 38.646 3.403 ;
     RECT  39.42 3.181 39.438 3.403 ;
     RECT  2.304 3.307 5.058 3.415 ;
     RECT  5.868 3.271 5.886 3.415 ;
     RECT  37.728 3.403 39.438 3.451 ;
     RECT  40.215 2.911 40.878 3.451 ;
     RECT  2.304 3.415 5.922 3.541 ;
     RECT  6.804 2.911 6.822 3.541 ;
     RECT  2.304 3.541 6.822 3.649 ;
     RECT  24.015 2.413 24.297 3.649 ;
     RECT  32.04 3.343 32.058 3.649 ;
     RECT  23.94 3.649 24.297 3.685 ;
     RECT  32.04 3.649 32.346 3.685 ;
     RECT  42.228 3.145 42.246 3.685 ;
     RECT  2.304 3.649 6.93 3.721 ;
     RECT  18.216 3.181 18.897 3.721 ;
     RECT  37.656 3.451 40.878 3.739 ;
     RECT  1.152 3.379 1.17 3.811 ;
     RECT  34.776 3.181 35.097 3.811 ;
     RECT  42.192 3.685 42.246 3.821 ;
     RECT  42.192 3.821 42.21 3.883 ;
     RECT  37.548 3.739 40.878 3.919 ;
     RECT  36.756 3.811 36.774 3.955 ;
     RECT  2.304 3.721 7.002 3.979 ;
     RECT  7.815 2.413 8.097 3.979 ;
     RECT  2.304 3.979 8.097 3.991 ;
     RECT  20.052 3.379 20.07 3.991 ;
     RECT  32.04 3.685 32.994 3.991 ;
     RECT  34.776 3.811 35.622 4.075 ;
     RECT  36.576 3.955 36.774 4.075 ;
     RECT  37.512 3.919 40.878 4.075 ;
     RECT  2.304 3.991 8.19 4.081 ;
     RECT  20.052 3.991 20.178 4.081 ;
     RECT  29.415 2.413 29.697 4.081 ;
     RECT  18.216 3.721 18.954 4.117 ;
     RECT  19.728 4.081 20.178 4.117 ;
     RECT  42.156 3.883 42.21 4.171 ;
     RECT  28.764 4.081 29.697 4.189 ;
     RECT  37.512 4.075 41.022 4.217 ;
     RECT  23.94 3.685 24.354 4.219 ;
     RECT  34.776 4.075 36.774 4.225 ;
     RECT  37.512 4.217 40.698 4.225 ;
     RECT  21.78 4.225 21.798 4.261 ;
     RECT  41.832 4.171 42.21 4.301 ;
     RECT  21.276 4.261 21.798 4.459 ;
     RECT  41.832 4.301 42.174 4.459 ;
     RECT  17.1 4.459 17.118 4.495 ;
     RECT  17.964 4.117 20.178 4.495 ;
     RECT  34.776 4.225 40.698 4.589 ;
     RECT  2.304 4.081 8.658 4.621 ;
     RECT  23.004 3.343 23.022 4.621 ;
     RECT  17.1 4.495 20.178 4.651 ;
     RECT  23.004 4.621 23.166 4.651 ;
     RECT  23.94 4.219 24.606 4.651 ;
     RECT  21.132 4.459 21.798 4.657 ;
     RECT  23.004 4.651 24.606 4.657 ;
     RECT  26.82 4.621 26.838 4.657 ;
     RECT  28.224 4.189 29.697 4.657 ;
     RECT  26.82 4.657 27.27 4.693 ;
     RECT  26.28 4.693 27.27 4.699 ;
     RECT  28.224 4.657 29.754 4.729 ;
     RECT  34.776 4.589 40.626 4.765 ;
     RECT  2.268 4.621 8.658 4.801 ;
     RECT  30.852 4.729 30.87 4.801 ;
     RECT  10.836 4.801 10.854 4.891 ;
     RECT  28.224 4.729 29.79 4.891 ;
     RECT  21.132 4.657 24.606 4.927 ;
     RECT  28.152 4.891 29.79 4.963 ;
     RECT  2.268 4.801 8.874 4.987 ;
     RECT  9.684 4.747 9.702 4.987 ;
     RECT  28.08 4.963 29.79 4.999 ;
     RECT  30.852 4.801 31.158 4.999 ;
     RECT  17.1 4.651 20.286 5.071 ;
     RECT  21.132 4.927 25.038 5.071 ;
     RECT  17.1 5.071 25.11 5.131 ;
     RECT  26.136 4.699 27.27 5.131 ;
     RECT  10.656 4.891 10.854 5.161 ;
     RECT  17.1 5.131 27.27 5.197 ;
     RECT  28.08 4.999 31.302 5.197 ;
     RECT  32.04 3.991 33.246 5.197 ;
     RECT  34.236 4.765 40.626 5.197 ;
     RECT  1.152 3.811 1.422 5.261 ;
     RECT  14.832 3.991 14.85 5.305 ;
     RECT  0.144 5.179 0.162 5.341 ;
     RECT  34.2 5.197 40.626 5.341 ;
     RECT  16.92 5.197 31.302 5.419 ;
     RECT  0.144 5.341 0.234 5.431 ;
     RECT  16.776 5.419 31.302 5.431 ;
     RECT  32.04 5.197 33.462 5.431 ;
     RECT  16.776 5.431 33.462 5.539 ;
     RECT  16.524 5.539 33.462 5.575 ;
     RECT  34.2 5.341 40.662 5.575 ;
     RECT  41.508 4.459 42.174 5.575 ;
     RECT  0.144 5.431 0.27 5.644 ;
     RECT  16.524 5.575 42.174 5.645 ;
     RECT  16.524 5.645 40.842 5.729 ;
     RECT  10.656 5.161 11.178 5.737 ;
     RECT  14.832 5.305 14.922 5.737 ;
     RECT  14.832 5.737 14.958 5.809 ;
     RECT  43.056 3.955 43.074 5.995 ;
     RECT  16.524 5.729 40.662 6.029 ;
     RECT  2.268 4.987 9.702 6.043 ;
     RECT  41.58 5.645 42.174 6.115 ;
     RECT  43.056 5.995 43.11 6.125 ;
     RECT  14.832 5.809 14.994 6.143 ;
     RECT  1.188 5.261 1.422 6.187 ;
     RECT  2.268 6.043 9.81 6.187 ;
     RECT  36.72 6.029 40.662 6.269 ;
     RECT  16.524 6.029 35.838 6.283 ;
     RECT  10.656 5.737 11.394 6.313 ;
     RECT  41.58 6.115 42.246 6.385 ;
     RECT  1.188 6.187 9.81 6.419 ;
     RECT  7.596 6.419 9.81 6.421 ;
     RECT  10.656 6.313 11.466 6.421 ;
     RECT  1.188 6.419 6.858 6.611 ;
     RECT  7.596 6.421 11.466 6.611 ;
     RECT  14.832 6.143 14.85 6.719 ;
     RECT  1.188 6.611 1.422 6.797 ;
     RECT  41.58 6.385 42.282 6.797 ;
     RECT  36.936 6.269 40.662 6.853 ;
     RECT  43.092 6.125 43.11 6.893 ;
     RECT  36.936 6.853 40.698 6.961 ;
     RECT  0.108 5.644 0.27 7.051 ;
     RECT  36.936 6.961 40.842 7.147 ;
     RECT  41.58 6.797 42.21 7.147 ;
     RECT  14.868 6.925 14.958 7.151 ;
     RECT  0.108 7.051 0.342 7.231 ;
     RECT  16.128 6.283 35.838 7.231 ;
     RECT  2.304 6.611 6.858 7.321 ;
     RECT  7.596 6.611 11.394 7.321 ;
     RECT  16.128 7.231 36.09 7.321 ;
     RECT  36.936 7.147 42.21 7.321 ;
     RECT  16.128 7.321 42.21 7.349 ;
     RECT  2.304 7.321 11.394 7.493 ;
     RECT  14.868 7.151 14.886 7.501 ;
     RECT  1.404 6.797 1.422 7.565 ;
     RECT  17.1 7.349 42.21 7.619 ;
     RECT  14.832 7.501 14.886 7.691 ;
     RECT  17.244 7.619 42.21 7.763 ;
     RECT  16.128 7.349 16.146 7.889 ;
     RECT  2.304 7.493 11.286 7.933 ;
     RECT  2.232 7.933 11.286 8.069 ;
     RECT  0.108 7.231 0.558 8.203 ;
     RECT  14.832 7.691 14.85 8.231 ;
     RECT  0.108 8.203 0.594 8.239 ;
     RECT  0.108 8.239 0.666 8.285 ;
     RECT  2.304 8.069 11.286 8.311 ;
     RECT  0.108 8.285 0.558 8.333 ;
     RECT  17.244 7.763 40.698 8.392 ;
     RECT  17.172 8.392 40.698 8.429 ;
     RECT  43.02 7.501 43.038 8.429 ;
     RECT  2.304 8.311 11.322 8.437 ;
     RECT  2.304 8.437 11.754 8.443 ;
     RECT  17.172 8.429 27.054 8.465 ;
     RECT  18.615 8.465 27.054 8.477 ;
     RECT  27.9 8.429 40.698 8.491 ;
     RECT  41.544 7.763 42.21 8.491 ;
     RECT  0.108 8.333 0.342 8.525 ;
     RECT  26.496 8.477 27.054 8.537 ;
     RECT  27.9 8.491 42.21 8.537 ;
     RECT  26.532 8.537 27.054 8.573 ;
     RECT  0.108 8.525 0.234 8.609 ;
     RECT  0.108 8.609 0.162 8.621 ;
     RECT  18.615 8.477 25.758 8.699 ;
     RECT  0.108 8.621 0.126 8.717 ;
     RECT  2.304 8.443 11.97 8.807 ;
     RECT  26.532 8.573 26.874 8.879 ;
     RECT  27.9 8.537 42.174 8.969 ;
     RECT  16.344 8.971 16.362 9.011 ;
     RECT  27.9 8.969 40.698 9.275 ;
     RECT  16.524 9.085 16.542 9.307 ;
     RECT  17.28 8.465 17.802 9.307 ;
     RECT  27.9 9.275 40.662 9.319 ;
     RECT  16.524 9.307 17.802 9.347 ;
     RECT  13.215 2.413 13.497 9.391 ;
     RECT  14.868 8.581 14.886 9.481 ;
     RECT  14.832 9.481 14.886 9.553 ;
     RECT  13.032 9.391 13.497 9.581 ;
     RECT  0.54 9.553 0.558 9.595 ;
     RECT  2.304 8.807 11.754 9.643 ;
     RECT  14.832 9.553 14.922 9.653 ;
     RECT  17.244 9.347 17.802 9.661 ;
     RECT  18.615 8.699 24.786 9.661 ;
     RECT  25.56 8.699 25.758 9.661 ;
     RECT  26.532 8.879 26.586 9.661 ;
     RECT  2.268 9.643 11.79 9.689 ;
     RECT  25.56 9.661 26.694 9.691 ;
     RECT  27.612 9.319 40.662 9.691 ;
     RECT  17.244 9.661 24.786 9.779 ;
     RECT  17.424 9.779 24.786 9.787 ;
     RECT  25.56 9.691 40.662 9.787 ;
     RECT  0.18 9.595 0.558 9.82 ;
     RECT  2.268 9.689 11.394 9.923 ;
     RECT  0.108 9.82 0.558 9.965 ;
     RECT  17.424 9.787 40.662 10.085 ;
     RECT  17.676 10.085 40.662 10.093 ;
     RECT  41.508 8.969 42.174 10.123 ;
     RECT  2.268 9.923 11.322 10.219 ;
     RECT  41.508 10.123 42.21 10.219 ;
     RECT  14.868 9.653 14.922 10.229 ;
     RECT  16.452 9.895 16.47 10.253 ;
     RECT  2.232 10.219 11.322 10.319 ;
     RECT  17.676 10.093 40.698 10.319 ;
     RECT  18.108 10.319 40.698 10.357 ;
     RECT  13.068 9.581 13.497 10.363 ;
     RECT  41.472 10.219 42.21 10.427 ;
     RECT  0.144 9.965 0.558 10.445 ;
     RECT  2.268 10.319 11.322 10.463 ;
     RECT  13.032 10.363 13.497 10.589 ;
     RECT  18.108 10.357 40.734 10.625 ;
     RECT  0.144 10.445 0.522 10.637 ;
     RECT  18.108 10.625 27.162 10.733 ;
     RECT  18.108 10.733 27.126 10.769 ;
     RECT  43.092 10.603 43.11 10.795 ;
     RECT  2.268 10.463 11.286 10.859 ;
     RECT  22.032 10.769 27.126 10.859 ;
     RECT  28.008 10.625 40.734 10.859 ;
     RECT  14.832 10.597 14.85 10.967 ;
     RECT  28.224 10.859 40.734 10.975 ;
     RECT  18.108 10.769 21.294 11.039 ;
     RECT  43.056 10.795 43.11 11.039 ;
     RECT  20.988 11.039 21.294 11.129 ;
     RECT  25.884 10.859 27.126 11.165 ;
     RECT  42.156 10.427 42.21 11.179 ;
     RECT  28.224 10.975 40.878 11.201 ;
     RECT  25.992 11.165 27.126 11.213 ;
     RECT  26.064 11.213 27.09 11.237 ;
     RECT  29.412 11.201 40.878 11.237 ;
     RECT  41.796 11.179 42.21 11.237 ;
     RECT  43.092 11.039 43.11 11.273 ;
     RECT  2.304 10.859 11.286 11.281 ;
     RECT  18.108 11.039 20.25 11.281 ;
     RECT  28.224 11.201 28.35 11.309 ;
     RECT  14.868 11.281 14.886 11.398 ;
     RECT  22.032 10.859 25.074 11.399 ;
     RECT  26.064 11.237 26.946 11.399 ;
     RECT  17.964 11.281 20.25 11.435 ;
     RECT  0.144 10.637 0.162 11.515 ;
     RECT  17.964 11.435 19.062 11.515 ;
     RECT  41.796 11.237 42.174 11.543 ;
     RECT  26.748 11.399 26.874 11.549 ;
     RECT  21.096 11.129 21.294 11.551 ;
     RECT  22.032 11.399 24.786 11.551 ;
     RECT  0.144 11.515 0.198 11.563 ;
     RECT  13.068 10.589 13.497 11.579 ;
     RECT  2.304 11.281 11.394 11.659 ;
     RECT  17.892 11.515 19.062 11.669 ;
     RECT  2.304 11.659 11.79 11.705 ;
     RECT  29.415 11.237 40.878 11.705 ;
     RECT  0.108 11.563 0.198 11.708 ;
     RECT  17.892 11.669 18.897 11.749 ;
     RECT  26.784 11.549 26.874 11.777 ;
     RECT  2.304 11.705 11.286 11.785 ;
     RECT  31.608 11.705 40.878 11.785 ;
     RECT  0.144 11.708 0.198 11.885 ;
     RECT  13.215 11.579 13.497 11.911 ;
     RECT  26.784 11.777 26.802 11.939 ;
     RECT  2.232 11.785 11.286 11.981 ;
     RECT  14.868 11.398 14.922 12.055 ;
     RECT  21.096 11.551 24.786 12.055 ;
     RECT  13.215 11.911 13.698 12.091 ;
     RECT  14.868 12.055 15.066 12.091 ;
     RECT  16.632 11.281 16.65 12.091 ;
     RECT  17.424 11.749 18.897 12.091 ;
     RECT  31.608 11.785 40.914 12.091 ;
     RECT  13.215 12.091 15.066 12.217 ;
     RECT  19.944 11.435 20.25 12.253 ;
     RECT  21.024 12.055 24.786 12.253 ;
     RECT  13.215 12.217 15.39 12.325 ;
     RECT  16.128 12.091 18.897 12.325 ;
     RECT  31.608 12.091 41.274 12.325 ;
     RECT  42.12 11.543 42.174 12.325 ;
     RECT  29.415 11.705 30.87 12.353 ;
     RECT  29.415 12.353 30.798 12.479 ;
     RECT  31.608 12.325 42.174 12.557 ;
     RECT  19.944 12.253 24.786 12.559 ;
     RECT  19.872 12.559 24.786 12.595 ;
     RECT  41.544 12.557 42.174 12.631 ;
     RECT  13.215 12.325 18.897 12.721 ;
     RECT  19.8 12.595 24.786 12.721 ;
     RECT  41.544 12.631 42.21 12.811 ;
     RECT  43.02 12.715 43.038 12.811 ;
     RECT  41.544 12.811 43.038 12.821 ;
     RECT  31.608 12.557 40.698 12.857 ;
     RECT  33.012 12.857 40.698 12.893 ;
     RECT  41.544 12.821 42.894 12.902 ;
     RECT  0.54 12.181 0.558 12.907 ;
     RECT  31.608 12.857 32.238 12.929 ;
     RECT  2.304 11.981 11.286 13.003 ;
     RECT  41.58 12.902 42.894 13.091 ;
     RECT  29.415 12.479 30.762 13.127 ;
     RECT  13.215 12.721 24.786 13.171 ;
     RECT  29.415 13.127 30.726 13.433 ;
     RECT  33.012 12.893 40.626 13.433 ;
     RECT  41.58 13.091 42.174 13.433 ;
     RECT  2.304 13.003 11.466 13.441 ;
     RECT  13.104 13.171 24.786 13.469 ;
     RECT  2.268 13.441 11.466 13.531 ;
     RECT  28.224 11.309 28.242 13.531 ;
     RECT  2.268 13.531 11.538 13.603 ;
     RECT  0.144 12.907 0.558 13.613 ;
     RECT  0.144 13.613 0.522 13.639 ;
     RECT  2.268 13.603 11.61 13.661 ;
     RECT  2.268 13.661 11.538 13.667 ;
     RECT  2.268 13.667 11.358 13.675 ;
     RECT  33.084 13.433 40.626 13.675 ;
     RECT  28.224 13.531 28.53 13.739 ;
     RECT  13.215 13.469 24.786 13.801 ;
     RECT  29.415 13.433 29.97 13.829 ;
     RECT  31.716 12.929 32.238 13.829 ;
     RECT  33.084 13.675 41.022 13.829 ;
     RECT  29.415 13.829 29.826 13.865 ;
     RECT  0.108 13.639 0.522 13.901 ;
     RECT  26.784 13.801 26.802 13.901 ;
     RECT  42.12 13.433 42.174 13.901 ;
     RECT  30.708 13.433 30.726 13.937 ;
     RECT  42.156 13.901 42.174 13.963 ;
     RECT  42.156 13.963 42.21 13.981 ;
     RECT  42.156 13.981 42.246 14.093 ;
     RECT  2.232 13.675 11.358 14.099 ;
     RECT  13.215 13.801 24.894 14.099 ;
     RECT  33.084 13.829 34.002 14.099 ;
     RECT  34.74 13.829 41.022 14.135 ;
     RECT  34.74 14.135 36.018 14.207 ;
     RECT  2.232 14.099 11.178 14.243 ;
     RECT  34.74 14.207 35.982 14.243 ;
     RECT  36.936 14.135 41.022 14.441 ;
     RECT  36.972 14.441 41.022 14.635 ;
     RECT  42.156 14.093 42.21 14.635 ;
     RECT  2.232 14.243 9.918 14.639 ;
     RECT  0.108 13.901 0.342 14.669 ;
     RECT  31.716 13.829 31.734 14.683 ;
     RECT  25.956 14.683 25.974 14.827 ;
     RECT  34.74 14.243 35.946 14.881 ;
     RECT  13.215 14.099 24.858 14.917 ;
     RECT  25.956 14.827 26.118 14.953 ;
     RECT  31.716 14.683 32.238 14.953 ;
     RECT  33.084 14.099 33.822 14.953 ;
     RECT  34.56 14.881 35.946 14.953 ;
     RECT  10.8 14.243 11.178 14.989 ;
     RECT  28.224 13.739 28.242 14.989 ;
     RECT  25.956 14.953 27.09 15.025 ;
     RECT  28.044 14.989 28.242 15.025 ;
     RECT  13.104 14.917 24.858 15.053 ;
     RECT  10.8 14.989 11.394 15.061 ;
     RECT  31.716 14.953 35.946 15.187 ;
     RECT  36.972 14.635 42.21 15.187 ;
     RECT  10.8 15.061 11.502 15.287 ;
     RECT  25.956 15.025 28.242 15.295 ;
     RECT  31.716 15.187 42.21 15.295 ;
     RECT  25.704 15.295 28.242 15.355 ;
     RECT  29.415 13.865 29.697 15.355 ;
     RECT  31.572 15.295 42.21 15.403 ;
     RECT  25.704 15.355 29.697 15.421 ;
     RECT  2.268 14.639 9.918 15.457 ;
     RECT  10.8 15.287 10.926 15.457 ;
     RECT  25.704 15.421 29.934 15.457 ;
     RECT  30.924 15.403 42.21 15.457 ;
     RECT  13.176 15.053 24.858 15.485 ;
     RECT  0.144 14.669 0.162 15.547 ;
     RECT  25.704 15.457 42.21 15.592 ;
     RECT  14.256 15.485 24.858 15.593 ;
     RECT  0.144 15.547 0.198 15.595 ;
     RECT  2.268 15.457 10.926 15.691 ;
     RECT  2.232 15.691 10.926 15.719 ;
     RECT  0.144 15.595 0.342 15.773 ;
     RECT  0.18 15.773 0.342 15.821 ;
     RECT  25.704 15.592 42.246 15.827 ;
     RECT  0.18 15.821 0.198 15.917 ;
     RECT  13.176 15.485 13.497 16.027 ;
     RECT  25.704 15.827 42.174 16.033 ;
     RECT  2.232 15.719 10.89 16.075 ;
     RECT  2.196 16.075 10.89 16.133 ;
     RECT  2.196 16.133 9.846 16.171 ;
     RECT  10.836 16.133 10.89 16.259 ;
     RECT  13.104 16.027 13.497 16.267 ;
     RECT  14.364 15.593 24.858 16.339 ;
     RECT  25.632 16.033 42.174 16.339 ;
     RECT  12.816 16.267 13.497 16.501 ;
     RECT  12.24 16.501 13.497 16.541 ;
     RECT  2.16 16.171 9.846 16.555 ;
     RECT  14.364 16.339 42.174 16.709 ;
     RECT  1.152 16.363 1.17 16.747 ;
     RECT  2.124 16.555 9.846 16.747 ;
     RECT  41.58 16.709 42.174 16.747 ;
     RECT  12.528 16.541 13.497 16.799 ;
     RECT  43.092 16.459 43.11 16.979 ;
     RECT  0.144 16.891 0.162 17.069 ;
     RECT  13.104 16.799 13.497 17.105 ;
     RECT  1.152 16.747 9.846 17.185 ;
     RECT  10.872 16.259 10.89 17.185 ;
     RECT  41.58 16.747 42.21 17.323 ;
     RECT  41.58 17.323 43.038 17.453 ;
     RECT  14.364 16.709 40.842 17.563 ;
     RECT  41.58 17.453 42.21 17.563 ;
     RECT  42.948 17.453 43.038 17.597 ;
     RECT  1.152 17.185 10.89 17.951 ;
     RECT  2.304 17.951 10.89 17.987 ;
     RECT  14.364 17.563 42.21 18.023 ;
     RECT  42.948 17.597 42.966 18.059 ;
     RECT  1.152 17.951 1.17 18.419 ;
     RECT  2.304 17.987 9.666 18.419 ;
     RECT  13.215 17.105 13.497 18.427 ;
     RECT  14.364 18.023 42.174 18.427 ;
     RECT  9 18.419 9.666 18.689 ;
     RECT  13.215 18.427 42.174 18.701 ;
     RECT  41.508 18.701 42.174 18.797 ;
     RECT  43.092 18.571 43.11 19.031 ;
     RECT  41.76 18.797 42.174 19.051 ;
     RECT  2.304 18.419 8.097 19.229 ;
     RECT  6.804 19.229 8.097 19.265 ;
     RECT  2.415 19.229 6.066 19.337 ;
     RECT  41.76 19.051 42.21 19.373 ;
     RECT  2.415 19.337 5.958 19.499 ;
     RECT  2.415 19.499 4.734 19.805 ;
     RECT  14.292 18.701 40.698 19.805 ;
     RECT  35.928 19.805 40.698 19.841 ;
     RECT  42.12 19.373 42.21 19.841 ;
     RECT  35.928 19.841 37.098 19.913 ;
     RECT  42.192 19.841 42.21 19.913 ;
     RECT  2.415 19.805 3.078 19.949 ;
     RECT  3.96 19.805 4.734 19.949 ;
     RECT  7.164 19.265 8.097 19.949 ;
     RECT  35.928 19.913 36.522 19.949 ;
     RECT  35.928 19.949 36.018 20.039 ;
     RECT  35.928 20.039 35.946 20.075 ;
     RECT  38.448 19.841 40.698 20.075 ;
     RECT  38.448 20.075 40.497 20.147 ;
     RECT  13.215 18.701 13.497 20.155 ;
     RECT  14.292 19.805 35.19 20.189 ;
     RECT  13.215 20.155 13.554 20.191 ;
     RECT  14.292 20.189 28.53 20.191 ;
     RECT  39.816 20.147 40.497 20.219 ;
     RECT  10.404 17.987 10.89 20.849 ;
     RECT  9.576 18.689 9.666 20.965 ;
     RECT  10.404 20.849 10.422 20.965 ;
     RECT  9.576 20.965 10.422 21.091 ;
     RECT  13.215 20.191 28.53 21.091 ;
     RECT  13.215 21.091 28.566 21.127 ;
     RECT  29.34 20.189 35.19 21.127 ;
     RECT  3.96 19.949 4.59 21.235 ;
     RECT  5.472 19.499 5.958 21.235 ;
     RECT  9.54 21.091 10.422 21.235 ;
     RECT  3.852 21.235 5.958 21.271 ;
     RECT  2.415 19.949 2.697 21.397 ;
     RECT  3.528 21.271 6.246 21.397 ;
     RECT  7.815 19.949 8.097 21.505 ;
     RECT  9.18 21.235 10.422 21.505 ;
     RECT  2.415 21.397 6.246 21.541 ;
     RECT  2.415 21.541 6.282 21.811 ;
     RECT  2.415 21.811 6.786 21.901 ;
     RECT  7.815 21.505 10.422 21.901 ;
     RECT  40.215 20.219 40.497 21.973 ;
     RECT  38.448 20.147 38.466 21.979 ;
     RECT  38.448 21.979 38.538 22.009 ;
     RECT  40.215 21.973 40.59 22.045 ;
     RECT  37.584 22.165 37.602 22.171 ;
     RECT  38.448 22.009 38.574 22.171 ;
     RECT  40.215 22.045 40.698 22.207 ;
     RECT  37.584 22.171 39.294 22.208 ;
     RECT  2.415 21.901 6.858 22.279 ;
     RECT  7.815 21.901 11.034 22.279 ;
     RECT  2.415 22.279 11.034 22.315 ;
     RECT  38.124 22.208 39.294 22.351 ;
     RECT  2.376 22.315 11.034 22.441 ;
     RECT  40.215 22.207 40.734 22.441 ;
     RECT  0.036 22.171 0.054 22.513 ;
     RECT  38.124 22.351 39.366 22.549 ;
     RECT  38.124 22.549 39.438 22.585 ;
     RECT  40.215 22.441 40.842 22.585 ;
     RECT  38.124 22.585 40.842 22.621 ;
     RECT  13.215 21.127 35.19 22.711 ;
     RECT  13.215 22.711 35.334 22.855 ;
     RECT  36.108 22.711 36.126 22.855 ;
     RECT  37.224 22.585 37.242 22.855 ;
     RECT  2.304 22.441 11.034 22.981 ;
     RECT  36.864 22.855 37.242 22.981 ;
     RECT  38.124 22.621 41.058 22.981 ;
     RECT  36.864 22.981 41.058 23.125 ;
     RECT  36.864 23.125 41.274 23.161 ;
     RECT  42.156 22.585 42.174 23.161 ;
     RECT  43.092 23.179 43.11 23.351 ;
     RECT  36.864 23.161 42.174 23.371 ;
     RECT  36.864 23.371 42.21 23.431 ;
     RECT  0.036 22.513 0.162 23.521 ;
     RECT  36.864 23.431 42.246 23.629 ;
     RECT  13.215 22.855 36.126 23.659 ;
     RECT  36.864 23.629 42.282 23.659 ;
     RECT  0.036 23.521 0.198 23.863 ;
     RECT  13.215 23.659 42.282 23.891 ;
     RECT  1.188 23.251 1.206 23.899 ;
     RECT  13.215 23.891 35.478 23.933 ;
     RECT  2.268 22.981 11.034 23.971 ;
     RECT  0.036 23.863 0.234 24.139 ;
     RECT  37.368 23.891 42.282 24.173 ;
     RECT  1.188 23.899 1.242 24.187 ;
     RECT  13.215 23.933 19.53 24.233 ;
     RECT  0.036 24.139 0.342 24.269 ;
     RECT  13.215 24.233 16.794 24.359 ;
     RECT  17.712 24.233 19.53 24.359 ;
     RECT  2.268 23.971 11.106 24.395 ;
     RECT  37.368 24.173 42.174 24.431 ;
     RECT  20.376 23.933 35.478 24.509 ;
     RECT  0.036 24.269 0.198 24.629 ;
     RECT  43.092 24.205 43.11 24.653 ;
     RECT  25.02 24.509 35.478 24.664 ;
     RECT  36.216 23.891 36.558 24.664 ;
     RECT  20.376 24.509 24.297 24.709 ;
     RECT  25.02 24.664 36.558 24.709 ;
     RECT  37.368 24.431 41.67 24.709 ;
     RECT  0.108 24.629 0.198 24.845 ;
     RECT  2.304 24.395 11.106 24.871 ;
     RECT  13.215 24.359 16.614 24.899 ;
     RECT  17.712 24.359 19.278 24.899 ;
     RECT  0.18 24.845 0.198 24.941 ;
     RECT  15.768 24.899 16.614 24.941 ;
     RECT  17.712 24.899 19.17 24.971 ;
     RECT  13.215 24.899 14.994 25.037 ;
     RECT  15.768 24.941 16.506 25.043 ;
     RECT  2.304 24.871 11.142 25.169 ;
     RECT  14.58 25.037 14.994 25.169 ;
     RECT  25.02 24.709 41.67 25.169 ;
     RECT  32.58 25.169 41.67 25.195 ;
     RECT  13.215 25.037 13.662 25.205 ;
     RECT  32.58 25.195 42.21 25.277 ;
     RECT  41.58 25.277 42.21 25.313 ;
     RECT  1.152 24.187 1.242 25.339 ;
     RECT  2.304 25.169 10.746 25.339 ;
     RECT  43.02 25.099 43.038 25.387 ;
     RECT  20.124 24.709 24.297 25.411 ;
     RECT  17.964 24.971 19.17 25.439 ;
     RECT  17.964 25.439 18.99 25.475 ;
     RECT  19.944 25.411 24.297 25.475 ;
     RECT  14.832 25.169 14.994 25.511 ;
     RECT  17.964 25.475 18.897 25.511 ;
     RECT  43.02 25.387 43.11 25.511 ;
     RECT  0.216 25.099 0.342 25.519 ;
     RECT  0.216 25.519 0.414 25.565 ;
     RECT  14.868 25.511 14.994 25.583 ;
     RECT  19.944 25.475 19.962 25.583 ;
     RECT  21.204 25.475 24.297 25.619 ;
     RECT  14.976 25.583 14.994 25.675 ;
     RECT  16.488 25.043 16.506 25.709 ;
     RECT  14.976 25.675 15.57 25.715 ;
     RECT  21.204 25.619 22.842 25.781 ;
     RECT  41.58 25.313 42.174 25.781 ;
     RECT  0.216 25.565 0.342 25.805 ;
     RECT  21.636 25.781 22.842 25.853 ;
     RECT  0.216 25.805 0.27 25.867 ;
     RECT  21.816 25.853 22.842 26.087 ;
     RECT  25.02 25.169 31.77 26.221 ;
     RECT  32.58 25.277 40.626 26.221 ;
     RECT  43.02 25.511 43.038 26.321 ;
     RECT  13.215 25.205 13.497 26.329 ;
     RECT  1.152 25.339 10.746 26.519 ;
     RECT  25.02 26.221 40.626 26.519 ;
     RECT  2.196 26.519 10.746 26.635 ;
     RECT  38.304 26.519 40.626 26.635 ;
     RECT  41.58 25.781 42.03 26.635 ;
     RECT  38.304 26.635 40.734 26.671 ;
     RECT  38.304 26.671 40.806 26.731 ;
     RECT  0.144 25.867 0.27 26.761 ;
     RECT  0.108 26.761 0.27 26.765 ;
     RECT  0.108 26.765 0.234 26.861 ;
     RECT  25.02 26.519 37.53 26.897 ;
     RECT  2.196 26.635 10.818 26.941 ;
     RECT  18.615 25.511 18.897 26.941 ;
     RECT  21.816 26.087 22.41 26.941 ;
     RECT  38.304 26.731 40.842 26.941 ;
     RECT  41.58 26.635 42.174 26.941 ;
     RECT  2.196 26.941 11.322 27.031 ;
     RECT  12.528 26.329 13.497 27.031 ;
     RECT  0.18 26.861 0.234 27.053 ;
     RECT  25.02 26.897 28.53 27.059 ;
     RECT  14.976 25.715 14.994 27.131 ;
     RECT  21.816 26.941 23.022 27.211 ;
     RECT  21.816 27.211 23.094 27.301 ;
     RECT  24.015 25.619 24.297 27.301 ;
     RECT  29.304 26.897 37.53 27.445 ;
     RECT  38.304 26.941 42.174 27.445 ;
     RECT  43.092 27.115 43.11 27.533 ;
     RECT  0.18 27.053 0.198 27.643 ;
     RECT  18.615 26.941 18.918 27.643 ;
     RECT  25.02 27.059 28.494 27.707 ;
     RECT  0.144 27.643 0.198 27.841 ;
     RECT  18.615 27.643 18.954 27.869 ;
     RECT  26.352 27.707 28.494 27.883 ;
     RECT  25.02 27.707 25.614 27.905 ;
     RECT  26.352 27.883 28.566 27.905 ;
     RECT  2.196 27.031 13.497 27.917 ;
     RECT  29.304 27.445 42.174 27.917 ;
     RECT  27.936 27.905 28.566 27.949 ;
     RECT  29.304 27.917 40.842 27.949 ;
     RECT  0.108 27.841 0.198 27.979 ;
     RECT  27.936 27.949 40.842 28.049 ;
     RECT  0.108 27.979 0.342 28.109 ;
     RECT  33.948 28.049 40.842 28.139 ;
     RECT  0.144 28.109 0.342 28.183 ;
     RECT  0.144 28.183 0.378 28.211 ;
     RECT  25.02 27.905 25.578 28.211 ;
     RECT  27.936 28.049 33.03 28.211 ;
     RECT  25.092 28.211 25.578 28.283 ;
     RECT  41.58 27.917 42.174 28.291 ;
     RECT  0.18 28.211 0.378 28.301 ;
     RECT  27.936 28.211 31.158 28.301 ;
     RECT  33.948 28.139 40.698 28.301 ;
     RECT  26.352 27.905 27.162 28.319 ;
     RECT  25.092 28.283 25.182 28.409 ;
     RECT  27.936 28.301 27.954 28.409 ;
     RECT  29.088 28.301 31.158 28.409 ;
     RECT  29.088 28.409 31.122 28.445 ;
     RECT  2.304 27.917 13.497 28.651 ;
     RECT  31.896 28.211 33.03 28.679 ;
     RECT  1.152 26.519 1.17 28.733 ;
     RECT  41.58 28.291 42.21 28.747 ;
     RECT  26.496 28.319 27.162 28.751 ;
     RECT  2.268 28.651 13.497 28.859 ;
     RECT  26.604 28.751 27.162 28.859 ;
     RECT  26.676 28.859 27.162 28.921 ;
     RECT  34.56 28.301 40.698 28.957 ;
     RECT  2.34 28.859 13.497 28.973 ;
     RECT  2.34 28.973 12.114 29.057 ;
     RECT  26.676 28.921 27.198 29.057 ;
     RECT  20.88 28.921 21.078 29.065 ;
     RECT  21.816 27.301 24.297 29.065 ;
     RECT  34.56 28.957 40.77 29.065 ;
     RECT  20.88 29.065 24.297 29.101 ;
     RECT  32.58 28.679 33.03 29.101 ;
     RECT  0.108 29.029 0.126 29.131 ;
     RECT  26.964 29.057 27.198 29.263 ;
     RECT  34.272 29.065 40.77 29.323 ;
     RECT  41.544 28.747 42.21 29.323 ;
     RECT  29.415 28.445 31.122 29.363 ;
     RECT  20.448 29.101 24.297 29.371 ;
     RECT  20.34 29.371 24.297 29.399 ;
     RECT  26.964 29.263 27.378 29.461 ;
     RECT  20.34 29.399 20.538 29.489 ;
     RECT  20.34 29.489 20.358 29.645 ;
     RECT  34.272 29.323 42.21 29.755 ;
     RECT  29.415 29.363 30.87 29.767 ;
     RECT  26.964 29.461 27.594 29.803 ;
     RECT  2.34 29.057 11.97 29.839 ;
     RECT  0.108 29.131 0.558 29.899 ;
     RECT  34.128 29.755 42.21 29.899 ;
     RECT  26.856 29.803 27.702 29.911 ;
     RECT  32.58 29.101 33.102 29.911 ;
     RECT  26.856 29.911 28.242 30.001 ;
     RECT  32.58 29.911 33.138 30.037 ;
     RECT  0.108 29.899 1.278 30.077 ;
     RECT  32.508 30.037 33.138 30.109 ;
     RECT  33.948 29.899 42.21 30.137 ;
     RECT  18.615 27.869 18.897 30.145 ;
     RECT  26.856 30.001 28.278 30.145 ;
     RECT  29.268 29.767 30.87 30.145 ;
     RECT  0.108 30.077 1.17 30.173 ;
     RECT  18.216 30.145 18.897 30.181 ;
     RECT  19.728 29.899 19.782 30.181 ;
     RECT  21.276 29.399 24.297 30.181 ;
     RECT  18.216 30.181 19.782 30.271 ;
     RECT  21.132 30.181 24.297 30.271 ;
     RECT  32.436 30.109 33.138 30.271 ;
     RECT  33.948 30.137 41.85 30.271 ;
     RECT  21.024 30.271 24.297 30.307 ;
     RECT  25.704 30.271 25.722 30.379 ;
     RECT  26.856 30.145 30.87 30.379 ;
     RECT  14.724 30.307 14.742 30.407 ;
     RECT  13.215 28.973 13.497 30.415 ;
     RECT  18 30.271 19.782 30.451 ;
     RECT  25.704 30.379 30.87 30.451 ;
     RECT  32.436 30.271 41.85 30.479 ;
     RECT  2.304 29.839 11.97 30.541 ;
     RECT  12.996 30.415 13.497 30.541 ;
     RECT  18 30.451 20.214 30.554 ;
     RECT  21.024 30.307 24.714 30.554 ;
     RECT  25.488 30.451 30.87 30.577 ;
     RECT  18 30.554 24.714 30.667 ;
     RECT  25.488 30.577 30.942 30.667 ;
     RECT  18 30.667 30.942 30.677 ;
     RECT  17.172 30.451 17.19 30.685 ;
     RECT  18 30.677 30.906 30.685 ;
     RECT  17.172 30.685 30.906 30.763 ;
     RECT  0.108 30.173 0.558 30.764 ;
     RECT  17.136 30.763 30.906 30.811 ;
     RECT  32.868 30.479 41.85 30.839 ;
     RECT  16.956 30.811 30.906 30.847 ;
     RECT  36.972 30.839 41.85 30.859 ;
     RECT  32.868 30.839 35.91 30.875 ;
     RECT  16.884 30.847 30.906 30.907 ;
     RECT  0.144 30.764 0.558 30.941 ;
     RECT  33.048 30.875 35.91 30.983 ;
     RECT  14.796 30.649 14.85 30.991 ;
     RECT  0.216 30.941 0.558 31.085 ;
     RECT  43.02 30.763 43.038 31.133 ;
     RECT  16.812 30.907 30.906 31.145 ;
     RECT  16.812 31.145 24.642 31.147 ;
     RECT  25.416 31.145 30.906 31.181 ;
     RECT  15.768 31.117 15.786 31.261 ;
     RECT  16.74 31.147 24.642 31.261 ;
     RECT  1.152 31.099 1.17 31.277 ;
     RECT  14.796 30.991 14.886 31.351 ;
     RECT  15.768 31.261 24.642 31.351 ;
     RECT  33.048 30.983 35.694 31.379 ;
     RECT  14.796 31.351 24.642 31.387 ;
     RECT  32.076 30.541 32.094 31.523 ;
     RECT  25.452 31.181 30.906 31.531 ;
     RECT  14.292 31.387 24.642 31.649 ;
     RECT  36.972 30.859 42.174 31.657 ;
     RECT  14.364 31.649 24.642 31.721 ;
     RECT  33.948 31.379 35.694 31.729 ;
     RECT  33.048 31.379 33.21 31.757 ;
     RECT  33.048 31.757 33.102 31.793 ;
     RECT  33.948 31.729 35.802 31.801 ;
     RECT  33.948 31.801 35.946 31.829 ;
     RECT  0.216 31.085 0.342 31.891 ;
     RECT  25.452 31.531 31.158 31.891 ;
     RECT  34.164 31.829 35.946 31.915 ;
     RECT  0.216 31.891 0.558 31.949 ;
     RECT  34.164 31.915 35.982 31.949 ;
     RECT  34.272 31.949 35.982 31.963 ;
     RECT  36.756 31.657 42.174 31.963 ;
     RECT  33.048 31.793 33.066 31.999 ;
     RECT  14.688 31.721 24.642 32.161 ;
     RECT  25.452 31.891 31.698 32.161 ;
     RECT  2.304 30.541 13.497 32.299 ;
     RECT  32.652 31.999 33.066 32.333 ;
     RECT  2.268 32.299 13.497 32.431 ;
     RECT  2.268 32.431 13.842 32.491 ;
     RECT  14.688 32.161 31.698 32.491 ;
     RECT  33.012 32.333 33.066 32.701 ;
     RECT  0.144 32.251 0.162 32.731 ;
     RECT  0.144 32.731 0.234 32.801 ;
     RECT  43.092 31.339 43.11 32.909 ;
     RECT  34.272 31.963 42.174 33.043 ;
     RECT  33.012 32.701 33.354 33.068 ;
     RECT  0.144 32.801 0.198 33.079 ;
     RECT  2.268 32.491 31.698 33.101 ;
     RECT  0.108 33.079 0.198 33.149 ;
     RECT  15.912 33.101 31.698 33.151 ;
     RECT  34.164 33.043 42.174 33.179 ;
     RECT  0.108 33.149 0.126 33.197 ;
     RECT  2.268 33.101 15.174 33.269 ;
     RECT  15.912 33.151 31.77 33.341 ;
     RECT  2.304 33.269 15.174 33.611 ;
     RECT  33.012 33.068 33.39 33.655 ;
     RECT  32.508 33.655 33.39 33.781 ;
     RECT  34.164 33.179 42.138 33.781 ;
     RECT  15.912 33.341 31.734 33.809 ;
     RECT  32.508 33.781 42.138 33.931 ;
     RECT  15.912 33.809 31.59 33.953 ;
     RECT  32.508 33.931 42.174 33.989 ;
     RECT  12.456 33.611 15.174 34.051 ;
     RECT  15.912 33.953 22.662 34.051 ;
     RECT  0.144 33.883 0.162 34.075 ;
     RECT  0.144 34.075 0.234 34.315 ;
     RECT  33.3 33.989 42.174 34.385 ;
     RECT  0.144 34.315 0.342 34.411 ;
     RECT  43.02 33.547 43.038 34.411 ;
     RECT  0.108 34.411 0.342 34.457 ;
     RECT  2.304 33.611 11.682 34.465 ;
     RECT  12.456 34.051 22.662 34.465 ;
     RECT  36.288 34.385 42.174 34.493 ;
     RECT  2.304 34.465 22.662 34.699 ;
     RECT  23.4 33.953 31.59 34.699 ;
     RECT  0.144 34.457 0.342 34.735 ;
     RECT  2.304 34.699 31.59 34.781 ;
     RECT  15.372 34.781 31.59 34.861 ;
     RECT  32.508 33.989 32.526 34.861 ;
     RECT  43.02 34.411 43.11 34.961 ;
     RECT  43.092 34.961 43.11 35.033 ;
     RECT  15.372 34.861 32.526 35.041 ;
     RECT  33.3 34.385 35.55 35.041 ;
     RECT  15.372 35.041 35.55 35.231 ;
     RECT  41.472 34.493 42.174 35.231 ;
     RECT  25.092 35.231 35.55 35.275 ;
     RECT  36.288 34.493 40.626 35.275 ;
     RECT  41.544 35.231 42.174 35.371 ;
     RECT  0.144 34.735 0.558 35.464 ;
     RECT  0.108 35.464 0.558 35.501 ;
     RECT  2.304 34.781 14.382 35.509 ;
     RECT  15.372 35.231 24.297 35.509 ;
     RECT  0.18 35.501 0.558 35.885 ;
     RECT  25.092 35.275 40.626 35.977 ;
     RECT  2.304 35.509 24.297 36.005 ;
     RECT  2.304 36.005 11.178 36.041 ;
     RECT  41.544 35.371 42.21 36.077 ;
     RECT  12.06 36.005 24.297 36.085 ;
     RECT  25.02 35.977 40.626 36.085 ;
     RECT  12.06 36.085 40.626 36.149 ;
     RECT  0.18 35.885 0.198 36.173 ;
     RECT  12.6 36.149 40.626 36.239 ;
     RECT  12.672 36.239 40.626 36.275 ;
     RECT  2.304 36.041 10.998 36.311 ;
     RECT  13.215 36.275 40.626 36.311 ;
     RECT  13.215 36.311 13.626 36.317 ;
     RECT  14.364 36.311 40.626 36.319 ;
     RECT  14.364 36.319 40.698 36.509 ;
     RECT  14.436 36.509 40.698 36.797 ;
     RECT  43.02 36.715 43.038 36.907 ;
     RECT  14.832 36.797 40.698 36.931 ;
     RECT  41.544 36.077 42.174 36.931 ;
     RECT  2.304 36.311 10.854 37.093 ;
     RECT  43.02 36.907 43.11 37.121 ;
     RECT  14.832 36.931 42.174 37.193 ;
     RECT  2.304 37.093 10.926 37.195 ;
     RECT  0.144 36.715 0.162 37.339 ;
     RECT  2.268 37.195 10.926 37.427 ;
     RECT  0.144 37.339 0.234 37.517 ;
     RECT  14.832 37.193 24.297 37.589 ;
     RECT  14.832 37.589 15.174 37.625 ;
     RECT  2.268 37.427 10.818 37.771 ;
     RECT  25.056 37.193 40.734 37.859 ;
     RECT  16.164 37.589 24.297 37.939 ;
     RECT  25.056 37.859 40.662 37.939 ;
     RECT  1.98 37.771 10.818 38.003 ;
     RECT  41.508 37.193 42.174 38.003 ;
     RECT  43.056 37.121 43.11 38.039 ;
     RECT  43.056 38.039 43.074 38.059 ;
     RECT  0.144 37.517 0.162 38.093 ;
     RECT  43.02 38.059 43.074 38.309 ;
     RECT  1.98 38.003 10.422 38.399 ;
     RECT  16.164 37.939 40.662 38.399 ;
     RECT  10.116 38.399 10.422 38.429 ;
     RECT  14.832 37.625 14.85 38.471 ;
     RECT  16.164 38.399 40.554 38.471 ;
     RECT  20.52 38.471 40.554 38.543 ;
     RECT  41.544 38.003 42.174 38.543 ;
     RECT  16.164 38.471 19.782 38.579 ;
     RECT  43.056 38.309 43.074 38.579 ;
     RECT  16.524 38.579 19.782 38.669 ;
     RECT  36.252 38.543 40.554 38.669 ;
     RECT  17.676 38.669 19.782 38.705 ;
     RECT  39.816 38.669 40.554 38.705 ;
     RECT  10.116 38.429 10.134 38.741 ;
     RECT  41.58 38.543 42.174 38.741 ;
     RECT  36.252 38.669 38.682 38.765 ;
     RECT  1.98 38.399 9.234 38.827 ;
     RECT  38.592 38.765 38.682 38.939 ;
     RECT  40.14 38.705 40.554 38.939 ;
     RECT  36.252 38.765 37.746 38.975 ;
     RECT  17.676 38.705 19.458 39.011 ;
     RECT  41.58 38.741 42.03 39.011 ;
     RECT  36.252 38.975 36.27 39.047 ;
     RECT  37.08 38.975 37.098 39.119 ;
     RECT  17.676 39.011 17.802 39.209 ;
     RECT  40.215 38.939 40.554 39.209 ;
     RECT  20.52 38.543 35.298 39.259 ;
     RECT  42.012 39.011 42.03 39.281 ;
     RECT  0.144 39.115 0.162 39.293 ;
     RECT  1.728 38.827 9.234 39.317 ;
     RECT  18.615 39.011 19.458 39.317 ;
     RECT  17.676 39.209 17.694 39.389 ;
     RECT  20.412 39.259 35.298 39.631 ;
     RECT  1.728 39.317 8.874 39.659 ;
     RECT  20.412 39.631 35.55 39.677 ;
     RECT  1.728 39.659 8.622 39.749 ;
     RECT  1.728 39.749 8.586 39.821 ;
     RECT  20.52 39.677 35.55 39.821 ;
     RECT  18.615 39.317 18.954 39.857 ;
     RECT  1.728 39.821 8.442 39.869 ;
     RECT  21.744 39.821 35.55 39.893 ;
     RECT  1.728 39.869 8.406 40.019 ;
     RECT  21.744 39.893 35.097 40.019 ;
     RECT  1.728 40.019 8.262 40.091 ;
     RECT  22.536 40.019 35.097 40.289 ;
     RECT  1.98 40.091 8.262 40.325 ;
     RECT  21.744 40.019 21.762 40.325 ;
     RECT  22.536 40.289 33.966 40.325 ;
     RECT  7.776 40.325 8.262 40.397 ;
     RECT  1.98 40.325 6.966 40.469 ;
     RECT  1.98 40.469 3.366 40.559 ;
     RECT  6.696 40.469 6.966 40.559 ;
     RECT  7.815 40.397 8.262 40.559 ;
     RECT  22.824 40.325 33.966 40.559 ;
     RECT  6.696 40.559 6.786 40.595 ;
     RECT  7.815 40.559 8.154 40.595 ;
     RECT  23.076 40.559 33.966 40.595 ;
     RECT  4.212 40.469 5.85 40.631 ;
     RECT  23.076 40.595 33.318 40.631 ;
     RECT  2.304 40.559 3.294 40.739 ;
     RECT  4.212 40.631 4.698 40.739 ;
     RECT  6.696 40.595 6.714 40.739 ;
     RECT  7.815 40.595 8.097 40.787 ;
     RECT  13.215 36.317 13.497 40.787 ;
     RECT  18.615 39.857 18.897 40.787 ;
     RECT  34.815 40.289 35.097 40.787 ;
     RECT  40.215 39.209 40.497 40.787 ;
     RECT  2.34 40.739 3.294 40.829 ;
     RECT  4.212 40.739 4.41 40.829 ;
     RECT  5.436 40.631 5.85 40.829 ;
     RECT  23.184 40.631 33.318 40.829 ;
     RECT  5.544 40.829 5.85 40.865 ;
     RECT  23.184 40.829 26.802 40.865 ;
     RECT  27.756 40.829 33.318 40.865 ;
     RECT  4.248 40.829 4.41 40.901 ;
     RECT  5.544 40.865 5.706 40.901 ;
     RECT  4.356 40.901 4.41 40.973 ;
     RECT  5.688 40.901 5.706 40.973 ;
     RECT  23.472 40.865 26.802 40.973 ;
     RECT  2.415 40.829 3.186 41.009 ;
     RECT  4.392 40.973 4.41 41.009 ;
     RECT  23.472 40.973 25.434 41.009 ;
     RECT  27.9 40.865 28.206 41.009 ;
     RECT  29.052 40.865 33.318 41.021 ;
     RECT  2.415 41.009 2.505 41.057 ;
     RECT  7.815 40.787 7.905 41.057 ;
     RECT  13.215 40.787 13.305 41.057 ;
     RECT  18.615 40.787 18.705 41.057 ;
     RECT  23.472 41.009 24.714 41.057 ;
     RECT  34.815 40.787 34.905 41.057 ;
     RECT  40.215 40.787 40.305 41.057 ;
     RECT  29.052 41.021 33.138 41.069 ;
     RECT  30.024 41.069 33.138 41.117 ;
     RECT  23.472 41.057 23.67 41.597 ;
     RECT  30.672 41.117 33.138 41.597 ;
     RECT  23.472 41.597 23.49 41.645 ;
     RECT  29.052 41.069 29.106 41.645 ;
     RECT  24.696 41.057 24.714 41.885 ;
     RECT  29.088 41.645 29.106 42.221 ;
     RECT  31.356 41.597 33.138 42.221 ;
     RECT  28.188 41.009 28.206 42.269 ;
     RECT  31.356 42.221 32.202 42.269 ;
     RECT  31.356 42.269 31.626 42.859 ;
     RECT  30.96 42.859 31.626 43.085 ;
    LAYER M4 ;
     RECT  0.06 24.048 0.061 39.336 ;
     RECT  0.06 4.848 0.173 17.064 ;
     RECT  0.061 23.952 0.173 39.336 ;
     RECT  0.173 4.848 2.257 16.968 ;
     RECT  2.257 4.848 2.293 17.112 ;
     RECT  2.293 4.752 2.408 17.112 ;
     RECT  0.173 24.144 2.408 39.336 ;
     RECT  2.408 2.148 2.512 41.052 ;
     RECT  2.512 2.418 2.704 40.782 ;
     RECT  2.704 22.272 3.377 40.488 ;
     RECT  2.704 3.984 3.413 19.368 ;
     RECT  2.704 2.736 3.733 2.904 ;
     RECT  3.413 3.984 3.733 17.928 ;
     RECT  3.377 22.272 3.809 40.392 ;
     RECT  3.733 2.736 3.989 17.928 ;
     RECT  3.989 3.696 4.781 17.928 ;
     RECT  3.809 22.272 4.885 40.152 ;
     RECT  4.781 15.168 5.065 17.928 ;
     RECT  4.885 22.272 5.177 40.296 ;
     RECT  4.781 3.696 5.285 14.088 ;
     RECT  5.177 22.272 5.393 40.104 ;
     RECT  5.065 15.168 5.677 18.216 ;
     RECT  3.413 19.248 5.677 19.368 ;
     RECT  5.285 3.792 5.753 14.088 ;
     RECT  5.393 22.272 5.965 40.008 ;
     RECT  5.965 21.984 5.969 40.008 ;
     RECT  5.969 21.984 6.077 39.576 ;
     RECT  5.753 3.888 6.181 14.088 ;
     RECT  5.677 15.168 6.181 19.368 ;
     RECT  6.181 3.888 6.293 19.368 ;
     RECT  6.077 22.56 6.293 39.576 ;
     RECT  6.293 3.984 6.797 19.368 ;
     RECT  6.797 3.984 7.808 18.264 ;
     RECT  6.797 19.296 7.808 19.368 ;
     RECT  6.293 22.848 7.808 39.576 ;
     RECT  7.808 2.148 7.912 41.052 ;
     RECT  7.912 2.418 8.104 40.782 ;
     RECT  8.104 23.28 8.273 39.96 ;
     RECT  8.273 23.28 8.453 39.864 ;
     RECT  8.453 23.28 8.489 39.528 ;
     RECT  8.104 4.224 8.525 18.168 ;
     RECT  8.489 23.28 8.633 39.336 ;
     RECT  8.525 4.224 8.741 17.784 ;
     RECT  8.633 23.28 8.777 39.048 ;
     RECT  8.777 23.28 8.957 23.832 ;
     RECT  8.741 4.224 9.245 17.688 ;
     RECT  8.777 24.912 9.245 39.048 ;
     RECT  9.245 6.048 9.353 17.688 ;
     RECT  9.353 6.048 9.389 16.392 ;
     RECT  8.957 23.28 9.533 23.688 ;
     RECT  9.389 16.128 9.569 16.392 ;
     RECT  9.245 4.224 9.713 4.776 ;
     RECT  9.389 6.048 9.821 14.712 ;
     RECT  9.821 6.528 9.857 14.712 ;
     RECT  9.857 6.528 10.289 14.184 ;
     RECT  9.245 24.912 10.433 38.424 ;
     RECT  10.289 6.528 10.505 7.944 ;
     RECT  10.289 9.072 10.649 14.184 ;
     RECT  10.505 6.528 10.789 6.792 ;
     RECT  10.789 6.288 10.793 6.792 ;
     RECT  10.433 24.912 10.865 38.28 ;
     RECT  10.649 13.008 11.477 13.848 ;
     RECT  11.477 13.632 11.621 13.848 ;
     RECT  10.649 9.072 11.801 11.688 ;
     RECT  10.865 24.912 11.801 33.096 ;
     RECT  11.801 24.912 11.837 29.352 ;
     RECT  11.837 24.912 11.891 27.096 ;
     RECT  11.837 28.368 11.891 29.352 ;
     RECT  10.505 7.92 11.941 7.944 ;
     RECT  11.801 9.072 11.941 9.096 ;
     RECT  9.569 16.128 12.229 16.344 ;
     RECT  9.353 17.424 12.229 17.496 ;
     RECT  11.801 30.384 12.913 33.096 ;
     RECT  10.865 34.128 12.913 38.28 ;
     RECT  12.229 16.128 13.093 17.496 ;
     RECT  9.713 4.224 13.208 4.488 ;
     RECT  10.793 6.288 13.208 6.312 ;
     RECT  11.941 7.92 13.208 9.096 ;
     RECT  11.801 10.128 13.208 10.968 ;
     RECT  11.621 13.824 13.208 13.848 ;
     RECT  13.093 16.032 13.208 17.496 ;
     RECT  8.104 19.296 13.208 19.368 ;
     RECT  12.229 22.032 13.208 22.056 ;
     RECT  9.533 23.664 13.208 23.688 ;
     RECT  11.891 25.008 13.208 27.096 ;
     RECT  11.891 28.512 13.208 29.352 ;
     RECT  12.913 30.384 13.208 38.28 ;
     RECT  13.208 2.148 13.312 41.052 ;
     RECT  13.312 2.418 13.504 40.782 ;
     RECT  13.504 34.704 13.853 38.28 ;
     RECT  13.504 18.672 14.38 22.488 ;
     RECT  13.853 35.328 14.393 38.28 ;
     RECT  13.504 17.424 14.533 17.496 ;
     RECT  14.38 18.672 14.533 19.896 ;
     RECT  13.504 32.016 14.533 33.576 ;
     RECT  13.504 15.408 14.569 16.344 ;
     RECT  13.504 12.528 14.713 12.552 ;
     RECT  13.504 13.776 14.713 13.848 ;
     RECT  14.38 21.264 14.753 22.488 ;
     RECT  14.569 14.928 14.789 16.344 ;
     RECT  14.789 16.128 14.821 16.344 ;
     RECT  14.533 17.424 14.821 19.896 ;
     RECT  14.753 21.456 14.821 22.488 ;
     RECT  13.504 23.664 14.821 27.096 ;
     RECT  13.504 30.384 14.821 30.84 ;
     RECT  14.533 32.016 14.821 33.96 ;
     RECT  14.821 21.456 14.933 27.096 ;
     RECT  14.821 30.384 14.965 33.96 ;
     RECT  14.821 16.128 15.041 19.896 ;
     RECT  14.933 21.456 15.329 23.928 ;
     RECT  15.041 19.296 15.361 19.896 ;
     RECT  14.965 30.384 15.361 34.776 ;
     RECT  14.393 35.808 15.361 38.28 ;
     RECT  15.329 21.888 15.509 23.928 ;
     RECT  14.789 14.928 16.081 15.048 ;
     RECT  13.504 6.288 16.117 6.312 ;
     RECT  15.361 19.296 16.477 19.944 ;
     RECT  15.509 21.888 16.621 23.688 ;
     RECT  14.933 24.912 16.625 27.096 ;
     RECT  13.504 4.224 16.748 4.488 ;
     RECT  16.117 6.288 16.748 6.84 ;
     RECT  14.713 12.528 16.789 13.848 ;
     RECT  16.081 14.88 16.789 15.048 ;
     RECT  15.041 16.128 16.801 18.168 ;
     RECT  16.477 19.296 16.801 20.616 ;
     RECT  16.748 4.224 16.835 6.84 ;
     RECT  16.789 12.528 16.885 15.048 ;
     RECT  13.504 7.92 17.017 9.096 ;
     RECT  13.504 10.128 17.017 10.968 ;
     RECT  16.835 5.712 17.125 6.84 ;
     RECT  16.885 12.528 17.165 13.56 ;
     RECT  16.885 15.024 17.701 15.048 ;
     RECT  16.801 16.128 17.701 20.616 ;
     RECT  16.835 4.224 17.917 4.536 ;
     RECT  17.125 5.712 17.917 6.936 ;
     RECT  17.701 15.024 18.229 20.616 ;
     RECT  16.621 21.648 18.229 23.688 ;
     RECT  17.165 12.528 18.349 12.84 ;
     RECT  17.917 4.224 18.421 6.936 ;
     RECT  17.017 7.92 18.421 10.968 ;
     RECT  18.229 15.024 18.457 23.688 ;
     RECT  18.421 4.224 18.608 10.968 ;
     RECT  18.349 11.952 18.608 12.84 ;
     RECT  18.457 14.496 18.608 23.688 ;
     RECT  16.625 25.248 18.608 27.096 ;
     RECT  13.504 28.944 18.608 29.352 ;
     RECT  15.361 30.384 18.608 38.28 ;
     RECT  18.608 2.148 18.712 41.052 ;
     RECT  18.712 2.418 18.904 40.782 ;
     RECT  18.904 15.312 18.965 23.688 ;
     RECT  18.965 15.456 19.433 23.688 ;
     RECT  18.904 28.944 19.469 38.232 ;
     RECT  19.469 36.096 19.757 38.232 ;
     RECT  18.904 4.176 19.793 10.968 ;
     RECT  19.433 15.936 19.916 23.688 ;
     RECT  18.904 11.952 19.973 11.976 ;
     RECT  19.793 4.176 20.045 5.256 ;
     RECT  19.916 15.936 20.045 23.928 ;
     RECT  19.793 6.384 20.117 10.968 ;
     RECT  18.904 14.208 20.261 14.232 ;
     RECT  20.045 15.936 20.305 19.992 ;
     RECT  19.757 36.096 20.513 37.704 ;
     RECT  20.401 39.264 20.531 39.672 ;
     RECT  19.469 28.944 20.54 35.016 ;
     RECT  20.513 36.096 20.54 37.656 ;
     RECT  20.045 21.264 20.581 23.928 ;
     RECT  18.904 25.056 20.581 27.096 ;
     RECT  20.581 21.264 20.585 27.096 ;
     RECT  20.305 15.984 20.621 19.992 ;
     RECT  20.54 28.944 20.657 37.656 ;
     RECT  20.657 28.944 20.693 37.512 ;
     RECT  20.045 4.224 20.797 5.256 ;
     RECT  20.117 6.384 20.797 10.872 ;
     RECT  20.693 28.944 20.909 37.08 ;
     RECT  20.797 4.224 21.085 10.872 ;
     RECT  20.621 15.984 21.161 19.848 ;
     RECT  20.909 29.04 21.269 37.08 ;
     RECT  21.085 4.224 21.341 11.448 ;
     RECT  20.531 39.648 21.377 39.672 ;
     RECT  21.341 11.424 21.517 11.448 ;
     RECT  21.481 12.816 21.517 12.84 ;
     RECT  21.481 14.976 21.553 15 ;
     RECT  20.585 22.032 21.557 27.096 ;
     RECT  21.161 15.984 21.593 17.064 ;
     RECT  21.553 14.928 22.021 15 ;
     RECT  22.021 14.784 22.025 15 ;
     RECT  21.557 22.032 22.093 22.488 ;
     RECT  21.161 18.144 22.133 19.848 ;
     RECT  22.133 18.816 22.165 19.848 ;
     RECT  22.025 14.784 22.169 14.808 ;
     RECT  21.733 38.4 22.205 38.424 ;
     RECT  21.269 29.04 22.277 36.984 ;
     RECT  22.277 31.248 22.309 36.984 ;
     RECT  22.093 21.984 22.417 22.488 ;
     RECT  21.341 4.224 22.489 10.344 ;
     RECT  21.517 11.424 22.489 12.84 ;
     RECT  22.417 21.744 22.637 22.488 ;
     RECT  21.557 23.568 22.669 27.096 ;
     RECT  22.165 18.816 22.709 19.944 ;
     RECT  21.593 16.128 22.745 17.064 ;
     RECT  22.745 16.128 22.853 16.968 ;
     RECT  22.709 19.248 22.961 19.944 ;
     RECT  22.961 19.248 23.033 19.848 ;
     RECT  22.525 39.936 23.245 39.96 ;
     RECT  22.277 29.04 23.281 30.216 ;
     RECT  22.309 31.248 23.281 37.704 ;
     RECT  23.461 41.616 23.557 41.64 ;
     RECT  23.245 39.696 23.653 39.96 ;
     RECT  23.557 40.992 23.653 41.64 ;
     RECT  22.637 21.984 23.929 22.488 ;
     RECT  22.669 23.52 23.929 27.096 ;
     RECT  22.489 4.224 24.008 12.84 ;
     RECT  22.853 16.128 24.008 16.824 ;
     RECT  23.033 19.248 24.008 19.368 ;
     RECT  23.929 21.984 24.008 27.096 ;
     RECT  23.281 29.04 24.008 37.704 ;
     RECT  23.653 39.696 24.008 41.64 ;
     RECT  24.008 2.148 24.112 41.64 ;
     RECT  24.112 2.418 24.304 40.782 ;
     RECT  24.304 16.128 24.419 17.736 ;
     RECT  24.304 4.224 24.563 12.84 ;
     RECT  24.563 4.224 24.617 10.632 ;
     RECT  24.304 40.56 24.833 40.584 ;
     RECT  24.304 21.696 25.091 27.096 ;
     RECT  24.304 19.296 25.477 20.184 ;
     RECT  25.091 21.888 25.589 27.096 ;
     RECT  24.304 28.416 25.621 38.664 ;
     RECT  25.477 18.768 25.729 20.184 ;
     RECT  24.617 5.184 25.765 10.632 ;
     RECT  25.621 28.416 25.765 39 ;
     RECT  25.765 5.136 25.873 10.632 ;
     RECT  24.563 11.664 25.873 12.84 ;
     RECT  25.873 5.136 26.125 12.84 ;
     RECT  26.045 14.832 26.129 14.856 ;
     RECT  24.419 16.128 26.201 17.352 ;
     RECT  25.765 28.416 26.449 40.2 ;
     RECT  25.589 21.888 26.557 25.32 ;
     RECT  26.201 16.128 26.593 17.256 ;
     RECT  25.729 18.768 26.633 20.472 ;
     RECT  26.557 21.648 26.633 25.32 ;
     RECT  26.593 15.984 26.777 17.256 ;
     RECT  26.633 19.296 26.779 20.472 ;
     RECT  26.449 28.416 26.993 40.872 ;
     RECT  26.779 19.344 27.137 20.472 ;
     RECT  26.993 29.04 27.137 40.872 ;
     RECT  27.137 29.04 27.209 39.24 ;
     RECT  26.777 16.128 27.277 17.256 ;
     RECT  26.125 4.704 27.281 12.84 ;
     RECT  27.281 4.896 27.317 12.84 ;
     RECT  25.589 26.304 27.493 27.096 ;
     RECT  27.137 19.824 27.565 20.472 ;
     RECT  26.633 21.648 27.565 25.272 ;
     RECT  27.493 26.304 27.569 27.288 ;
     RECT  27.277 16.128 27.637 17.448 ;
     RECT  27.637 16.128 27.677 18.264 ;
     RECT  27.565 19.824 27.785 25.272 ;
     RECT  27.569 26.64 27.857 27.288 ;
     RECT  27.785 21.648 27.889 25.272 ;
     RECT  27.209 29.904 27.965 39.24 ;
     RECT  27.677 16.128 28.177 17.112 ;
     RECT  27.677 18.24 28.177 18.264 ;
     RECT  24.685 41.856 28.177 41.88 ;
     RECT  28.177 18.24 28.289 18.792 ;
     RECT  27.965 29.904 28.289 38.136 ;
     RECT  28.289 18.768 28.393 18.792 ;
     RECT  27.785 19.824 28.393 20.472 ;
     RECT  28.357 27.888 28.537 27.912 ;
     RECT  27.317 4.896 28.753 9.24 ;
     RECT  27.317 10.368 28.753 12.84 ;
     RECT  28.289 29.904 28.885 37.608 ;
     RECT  27.857 26.64 29.005 26.664 ;
     RECT  27.137 40.848 29.041 40.872 ;
     RECT  28.177 41.856 29.041 42.264 ;
     RECT  29.041 40.848 29.077 42.264 ;
     RECT  28.177 15.36 29.293 17.112 ;
     RECT  29.005 26.64 29.293 26.808 ;
     RECT  28.537 27.888 29.293 28.296 ;
     RECT  27.965 39.216 29.365 39.24 ;
     RECT  28.753 4.896 29.408 12.84 ;
     RECT  29.293 15.36 29.408 17.64 ;
     RECT  28.393 18.768 29.408 20.472 ;
     RECT  27.889 21.648 29.408 25.656 ;
     RECT  29.293 26.64 29.408 28.296 ;
     RECT  28.885 29.28 29.408 37.608 ;
     RECT  29.365 39.216 29.408 39.288 ;
     RECT  29.077 40.608 29.408 42.264 ;
     RECT  29.408 2.148 29.512 42.264 ;
     RECT  29.512 2.418 29.704 42.264 ;
     RECT  29.704 15.84 30.089 19.368 ;
     RECT  29.704 22.032 30.179 23.928 ;
     RECT  29.704 31.44 30.227 42.264 ;
     RECT  29.704 24.96 30.233 26.808 ;
     RECT  30.227 38.544 30.305 42.264 ;
     RECT  29.704 5.232 30.377 9.096 ;
     RECT  30.377 5.232 30.413 7.416 ;
     RECT  30.305 40.608 30.757 42.264 ;
     RECT  30.377 8.544 30.773 9.096 ;
     RECT  30.227 31.44 30.773 37.464 ;
     RECT  30.757 40.608 30.805 42.792 ;
     RECT  30.179 22.032 30.809 23.592 ;
     RECT  30.305 38.544 30.845 39.24 ;
     RECT  30.805 40.608 30.853 42.888 ;
     RECT  30.089 15.84 30.913 17.064 ;
     RECT  30.233 25.008 30.913 26.808 ;
     RECT  29.704 28.128 30.913 28.296 ;
     RECT  30.853 40.608 30.949 42.984 ;
     RECT  29.704 20.4 30.985 20.424 ;
     RECT  30.913 25.008 30.989 28.296 ;
     RECT  29.704 10.176 31.025 12.84 ;
     RECT  30.089 18.144 31.345 18.216 ;
     RECT  30.089 19.248 31.345 19.368 ;
     RECT  30.413 5.232 31.381 7.368 ;
     RECT  30.773 36.24 31.429 37.464 ;
     RECT  30.985 20.4 31.457 21 ;
     RECT  30.809 23.568 31.489 23.592 ;
     RECT  30.989 25.008 31.529 28.152 ;
     RECT  31.345 18.144 31.565 19.368 ;
     RECT  31.529 25.008 31.565 25.128 ;
     RECT  30.809 22.032 31.571 22.488 ;
     RECT  30.913 15.408 31.573 17.064 ;
     RECT  31.381 5.232 31.601 7.752 ;
     RECT  31.573 14.64 31.601 17.064 ;
     RECT  31.457 20.4 31.601 20.424 ;
     RECT  30.773 9.024 31.619 9.096 ;
     RECT  31.489 23.568 31.637 23.832 ;
     RECT  30.949 40.608 31.637 43.08 ;
     RECT  31.571 22.176 31.715 22.488 ;
     RECT  31.601 16.224 31.745 17.064 ;
     RECT  31.637 40.608 31.813 42.264 ;
     RECT  31.429 36.24 31.849 37.944 ;
     RECT  31.601 14.64 31.853 14.808 ;
     RECT  31.565 25.008 31.921 25.032 ;
     RECT  31.745 16.32 31.961 17.064 ;
     RECT  31.961 16.32 31.997 16.536 ;
     RECT  31.565 18.144 32.053 19.272 ;
     RECT  32.053 17.616 32.141 19.272 ;
     RECT  31.529 26.256 32.195 28.152 ;
     RECT  32.195 26.256 32.249 27.672 ;
     RECT  31.813 40.464 32.435 42.264 ;
     RECT  32.141 18.144 32.537 19.272 ;
     RECT  30.773 31.44 32.569 35.208 ;
     RECT  31.849 36.24 32.569 38.04 ;
     RECT  31.601 5.232 32.605 7.368 ;
     RECT  32.569 19.536 32.641 19.8 ;
     RECT  32.569 31.44 32.713 38.04 ;
     RECT  32.435 40.464 32.915 42.216 ;
     RECT  32.605 5.232 32.929 7.416 ;
     RECT  29.704 29.28 32.933 29.928 ;
     RECT  32.933 29.28 32.963 29.352 ;
     RECT  31.637 23.568 33.073 23.592 ;
     RECT  31.921 24.624 33.073 25.032 ;
     RECT  32.713 31.44 33.073 39.048 ;
     RECT  32.915 40.464 33.073 41.016 ;
     RECT  33.073 31.44 33.109 41.016 ;
     RECT  32.915 42.192 33.149 42.216 ;
     RECT  33.109 31.2 33.203 41.016 ;
     RECT  33.073 23.568 33.257 25.032 ;
     RECT  32.249 26.544 33.325 27.672 ;
     RECT  33.203 31.2 33.329 39.912 ;
     RECT  33.203 40.992 33.329 41.016 ;
     RECT  31.853 14.64 33.361 14.664 ;
     RECT  31.997 16.32 33.361 16.344 ;
     RECT  32.929 5.232 33.397 7.464 ;
     RECT  33.257 25.008 33.433 25.032 ;
     RECT  33.325 26.208 33.433 27.672 ;
     RECT  33.397 5.232 33.437 7.848 ;
     RECT  32.641 19.536 33.437 20.04 ;
     RECT  31.619 9.024 33.649 9.048 ;
     RECT  31.025 10.416 33.793 12.84 ;
     RECT  33.437 6.24 33.865 7.848 ;
     RECT  33.649 9.024 33.865 9.144 ;
     RECT  33.433 25.008 33.937 27.672 ;
     RECT  32.963 29.28 33.937 29.304 ;
     RECT  33.613 30.432 33.937 30.456 ;
     RECT  33.361 14.64 34.261 17.064 ;
     RECT  32.537 18.144 34.261 18.456 ;
     RECT  33.865 6.24 34.441 9.144 ;
     RECT  33.793 10.416 34.441 13.656 ;
     RECT  31.715 22.464 34.501 22.488 ;
     RECT  33.437 20.016 34.513 20.04 ;
     RECT  33.937 29.28 34.513 30.456 ;
     RECT  33.329 31.44 34.513 39.912 ;
     RECT  33.437 5.232 34.765 5.256 ;
     RECT  34.441 6.24 34.765 13.656 ;
     RECT  34.765 5.232 34.808 13.656 ;
     RECT  34.261 14.64 34.808 18.456 ;
     RECT  34.513 19.824 34.808 20.04 ;
     RECT  34.501 21.984 34.808 22.488 ;
     RECT  33.257 23.568 34.808 23.592 ;
     RECT  33.937 25.008 34.808 28.296 ;
     RECT  34.513 29.28 34.808 39.912 ;
     RECT  34.808 2.148 34.912 41.052 ;
     RECT  34.912 2.418 35.104 40.782 ;
     RECT  35.104 29.28 35.165 29.352 ;
     RECT  35.104 23.568 35.381 27.768 ;
     RECT  35.104 30.576 35.381 38.184 ;
     RECT  35.104 4.08 35.669 19.8 ;
     RECT  35.669 4.08 35.921 19.128 ;
     RECT  35.381 23.568 36.421 23.688 ;
     RECT  35.381 24.672 36.421 27.768 ;
     RECT  35.381 31.44 36.565 38.184 ;
     RECT  35.921 9.696 36.569 19.128 ;
     RECT  36.569 9.696 36.857 18.84 ;
     RECT  36.133 30.432 36.961 30.456 ;
     RECT  36.565 31.44 36.961 38.76 ;
     RECT  35.921 4.08 36.997 8.712 ;
     RECT  36.857 9.696 36.997 18.264 ;
     RECT  35.165 29.28 36.997 29.304 ;
     RECT  36.961 30.432 36.997 38.76 ;
     RECT  36.421 23.568 37.177 27.768 ;
     RECT  37.177 23.568 37.393 28.152 ;
     RECT  36.997 29.28 37.393 38.76 ;
     RECT  35.104 21.984 37.532 22.008 ;
     RECT  36.997 4.08 37.537 18.264 ;
     RECT  37.537 3.744 37.717 18.264 ;
     RECT  37.393 23.568 37.861 38.76 ;
     RECT  37.717 3.408 37.969 18.264 ;
     RECT  37.825 19.248 37.969 19.272 ;
     RECT  37.861 23.28 38.225 38.76 ;
     RECT  37.532 21.984 38.549 22.2 ;
     RECT  37.969 3.408 38.621 19.272 ;
     RECT  38.225 23.28 38.629 38.52 ;
     RECT  38.621 6 38.725 19.272 ;
     RECT  38.621 3.408 38.837 4.968 ;
     RECT  38.725 6 38.873 19.464 ;
     RECT  38.873 6 38.981 9.144 ;
     RECT  38.981 6.336 39.949 9.144 ;
     RECT  38.873 10.272 39.949 19.464 ;
     RECT  39.949 6.336 39.985 19.464 ;
     RECT  38.837 3.936 40.069 4.968 ;
     RECT  40.069 3.888 40.129 4.968 ;
     RECT  39.985 6 40.129 19.464 ;
     RECT  40.129 3.888 40.208 19.464 ;
     RECT  38.629 22.512 40.208 38.52 ;
     RECT  40.208 2.148 40.312 41.052 ;
     RECT  40.312 2.418 40.504 40.782 ;
     RECT  40.504 3.984 40.565 18.744 ;
     RECT  40.565 3.984 40.601 5.832 ;
     RECT  40.565 6.816 40.601 18.744 ;
     RECT  40.504 22.752 40.601 34.392 ;
     RECT  40.601 7.152 40.673 18.744 ;
     RECT  40.601 22.752 40.889 34.248 ;
     RECT  40.504 35.76 41.497 37.608 ;
     RECT  40.601 3.984 41.569 5.736 ;
     RECT  40.673 7.152 41.569 18.696 ;
     RECT  41.497 35.76 41.605 37.992 ;
     RECT  41.569 3.984 41.749 18.696 ;
     RECT  41.605 35.472 42.001 37.992 ;
     RECT  41.749 3.984 42.145 18.984 ;
     RECT  40.889 22.992 42.145 34.248 ;
     RECT  42.001 35.472 42.145 38.184 ;
     RECT  42.145 3.888 42.181 18.984 ;
     RECT  42.181 3.888 42.217 19.08 ;
     RECT  42.217 3.792 43.164 19.08 ;
     RECT  42.145 22.992 43.164 38.28 ;
    LAYER M5 ;
     RECT  2.4 2.137 2.52 2.151 ;
     RECT  7.8 2.137 7.92 2.151 ;
     RECT  13.2 2.137 13.32 2.151 ;
     RECT  18.6 2.137 18.72 2.151 ;
     RECT  24 2.137 24.12 2.151 ;
     RECT  29.4 2.137 29.52 2.151 ;
     RECT  34.8 2.137 34.92 2.151 ;
     RECT  40.2 2.137 40.32 2.151 ;
     RECT  40.2 2.151 40.512 3.877 ;
     RECT  18.6 2.151 18.912 4.645 ;
     RECT  5.712 3.925 5.736 4.691 ;
     RECT  29.4 2.151 29.712 5.029 ;
     RECT  16.8 4.501 16.824 6.277 ;
     RECT  18.24 4.645 18.912 6.277 ;
     RECT  38.928 3.925 38.952 6.277 ;
     RECT  16.8 6.277 18.912 6.323 ;
     RECT  40.08 3.877 40.512 6.323 ;
     RECT  16.8 6.323 17.352 6.851 ;
     RECT  7.8 2.151 8.112 6.853 ;
     RECT  0.144 6.901 0.168 7.187 ;
     RECT  2.4 2.151 2.712 7.189 ;
     RECT  24 2.151 24.312 7.237 ;
     RECT  26.112 7.045 26.136 7.333 ;
     RECT  6.768 6.805 6.792 7.381 ;
     RECT  4.608 7.381 4.632 8.003 ;
     RECT  38.16 6.277 38.952 8.003 ;
     RECT  40.2 6.323 40.512 8.005 ;
     RECT  7.8 6.853 8.232 8.147 ;
     RECT  38.16 8.003 38.712 8.291 ;
     RECT  2.4 7.189 2.952 8.435 ;
     RECT  6.24 7.381 6.792 8.437 ;
     RECT  7.8 8.147 8.112 8.437 ;
     RECT  26.112 7.333 26.808 8.483 ;
     RECT  38.16 8.291 38.184 8.485 ;
     RECT  0.144 8.341 0.168 8.531 ;
     RECT  29.28 5.029 29.712 8.579 ;
     RECT  6.24 8.437 8.112 8.723 ;
     RECT  31.248 9.013 31.272 9.061 ;
     RECT  6.768 8.723 8.112 9.155 ;
     RECT  40.08 8.005 40.512 9.299 ;
     RECT  6.768 9.155 6.792 9.731 ;
     RECT  37.584 8.485 38.184 9.731 ;
     RECT  20.544 7.957 20.568 9.779 ;
     RECT  0.192 9.589 0.216 9.827 ;
     RECT  17.328 6.851 17.352 10.067 ;
     RECT  26.112 8.483 26.136 10.307 ;
     RECT  2.4 8.435 2.712 10.357 ;
     RECT  40.2 9.299 40.512 10.357 ;
     RECT  40.2 10.357 40.776 10.501 ;
     RECT  6.72 9.925 6.744 10.549 ;
     RECT  6.192 10.549 6.744 10.595 ;
     RECT  38.16 9.731 38.184 10.789 ;
     RECT  31.248 9.061 31.608 10.883 ;
     RECT  24 7.237 24.552 10.931 ;
     RECT  7.8 9.155 8.112 11.317 ;
     RECT  2.4 10.357 2.808 11.365 ;
     RECT  21.264 10.453 21.288 11.459 ;
     RECT  40.2 10.501 41.016 11.459 ;
     RECT  7.8 11.317 9.096 11.507 ;
     RECT  34.8 2.151 35.112 11.509 ;
     RECT  40.2 11.459 40.728 11.699 ;
     RECT  38.16 10.789 38.568 11.941 ;
     RECT  5.136 11.845 5.16 12.035 ;
     RECT  2.4 11.365 3.432 12.277 ;
     RECT  2.16 12.277 3.432 12.467 ;
     RECT  6.192 10.595 6.216 12.517 ;
     RECT  7.8 11.507 8.112 12.517 ;
     RECT  15.072 10.213 15.096 12.517 ;
     RECT  14.832 12.517 15.096 12.563 ;
     RECT  34.368 11.509 35.112 13.379 ;
     RECT  40.2 11.699 40.512 13.381 ;
     RECT  38.16 11.941 38.616 13.525 ;
     RECT  39.792 13.381 40.512 13.525 ;
     RECT  6.192 12.517 8.112 13.667 ;
     RECT  14.832 12.563 14.856 13.667 ;
     RECT  2.4 12.467 3.432 13.715 ;
     RECT  38.16 13.525 40.512 13.765 ;
     RECT  38.16 13.765 40.632 14.149 ;
     RECT  6.192 13.667 6.216 14.291 ;
     RECT  16.848 10.213 16.872 14.291 ;
     RECT  31.584 10.883 31.608 14.819 ;
     RECT  38.064 14.149 40.632 14.819 ;
     RECT  26.064 11.221 26.088 14.867 ;
     RECT  38.16 14.819 40.632 14.867 ;
     RECT  5.136 14.053 5.16 15.299 ;
     RECT  38.16 14.867 38.184 15.443 ;
     RECT  34.704 13.379 35.112 15.587 ;
     RECT  18.6 6.323 18.912 15.733 ;
     RECT  0.144 15.781 0.168 15.971 ;
     RECT  16.8 14.485 16.824 16.261 ;
     RECT  16.8 16.261 17.064 16.307 ;
     RECT  6.24 14.773 6.264 16.403 ;
     RECT  18.384 15.733 18.912 16.405 ;
     RECT  2.4 13.715 3.336 16.453 ;
     RECT  13.2 2.151 13.512 16.501 ;
     RECT  17.04 16.307 17.064 16.501 ;
     RECT  18.24 16.405 18.912 16.501 ;
     RECT  17.04 16.501 18.912 16.547 ;
     RECT  39.264 14.867 40.632 16.595 ;
     RECT  2.304 16.453 3.336 16.835 ;
     RECT  7.8 13.667 8.112 16.933 ;
     RECT  34.8 15.587 35.112 17.029 ;
     RECT  24 10.931 24.312 17.077 ;
     RECT  20.256 15.925 20.28 17.557 ;
     RECT  19.968 17.557 20.28 17.603 ;
     RECT  31.536 15.973 31.56 17.605 ;
     RECT  37.008 14.581 37.032 17.699 ;
     RECT  24 17.077 24.408 17.747 ;
     RECT  7.104 16.933 8.112 18.275 ;
     RECT  34.176 17.029 35.112 18.275 ;
     RECT  14.832 16.933 14.856 18.707 ;
     RECT  2.4 16.835 3.336 18.851 ;
     RECT  17.808 16.547 18.912 18.997 ;
     RECT  19.968 17.603 19.992 18.997 ;
     RECT  17.808 18.997 19.992 19.093 ;
     RECT  12.24 16.501 13.512 19.237 ;
     RECT  31.536 17.605 32.088 19.283 ;
     RECT  39.84 16.595 40.512 19.427 ;
     RECT  38.736 17.605 38.76 19.475 ;
     RECT  17.808 19.093 20.04 19.763 ;
     RECT  20.016 19.763 20.04 20.003 ;
     RECT  17.808 19.763 18.912 20.579 ;
     RECT  24 17.747 24.312 21.685 ;
     RECT  12.24 19.237 14.328 21.923 ;
     RECT  34.8 18.275 35.112 21.973 ;
     RECT  15.456 21.877 16.344 22.019 ;
     RECT  24 21.685 25.08 22.165 ;
     RECT  31.536 19.283 31.56 22.165 ;
     RECT  31.536 22.165 31.704 22.211 ;
     RECT  37.584 22.165 37.752 22.501 ;
     RECT  40.2 19.427 40.512 22.741 ;
     RECT  29.4 8.579 29.712 23.029 ;
     RECT  18.24 20.579 18.912 23.075 ;
     RECT  16.32 22.019 16.344 23.123 ;
     RECT  20.016 22.741 20.04 23.411 ;
     RECT  23.856 22.165 25.08 23.509 ;
     RECT  23.856 23.509 25.128 23.795 ;
     RECT  29.4 23.029 30.168 23.939 ;
     RECT  23.856 23.795 24.456 24.035 ;
     RECT  5.712 23.701 5.736 24.515 ;
     RECT  37.584 22.501 38.664 24.709 ;
     RECT  12.24 21.923 13.512 24.901 ;
     RECT  14.784 23.893 14.808 24.901 ;
     RECT  14.784 24.901 15.528 24.947 ;
     RECT  19.968 23.893 19.992 25.045 ;
     RECT  19.968 25.045 20.376 25.091 ;
     RECT  2.4 18.851 2.712 25.237 ;
     RECT  7.8 18.275 8.112 25.621 ;
     RECT  15.504 24.947 15.528 25.715 ;
     RECT  2.304 25.237 2.712 26.099 ;
     RECT  0.144 25.765 0.168 26.147 ;
     RECT  40.08 22.741 40.512 26.341 ;
     RECT  4.8 24.901 4.824 26.533 ;
     RECT  31.68 22.211 31.704 26.533 ;
     RECT  37.008 24.709 38.664 26.581 ;
     RECT  37.008 26.581 38.76 26.627 ;
     RECT  28.08 22.165 28.104 26.629 ;
     RECT  34.512 21.973 35.112 26.629 ;
     RECT  28.08 26.629 28.2 26.675 ;
     RECT  37.728 26.627 38.76 26.725 ;
     RECT  40.08 26.341 41.016 26.725 ;
     RECT  37.728 26.725 41.016 26.819 ;
     RECT  31.68 26.533 32.184 27.155 ;
     RECT  7.296 25.621 8.112 27.349 ;
     RECT  37.728 26.819 40.512 27.395 ;
     RECT  32.16 27.155 32.184 27.589 ;
     RECT  6.96 27.349 8.112 27.685 ;
     RECT  34.176 26.629 35.112 27.875 ;
     RECT  37.728 27.395 38.904 27.875 ;
     RECT  4.56 26.533 4.824 28.163 ;
     RECT  32.16 27.589 32.952 28.163 ;
     RECT  40.032 27.395 40.512 28.211 ;
     RECT  6.96 27.685 8.232 28.403 ;
     RECT  11.856 24.901 13.512 28.547 ;
     RECT  38.16 27.875 38.904 28.547 ;
     RECT  40.2 28.211 40.512 28.549 ;
     RECT  11.856 28.547 11.88 28.931 ;
     RECT  6.96 28.403 8.112 28.979 ;
     RECT  40.2 28.549 41.016 29.123 ;
     RECT  28.176 26.675 28.2 29.269 ;
     RECT  29.4 23.939 29.712 29.269 ;
     RECT  32.928 28.163 32.952 29.363 ;
     RECT  40.2 29.123 40.512 30.085 ;
     RECT  40.2 30.085 41.016 30.181 ;
     RECT  38.16 28.547 38.76 30.275 ;
     RECT  4.8 28.163 4.824 30.421 ;
     RECT  4.8 30.421 5.16 30.659 ;
     RECT  20.352 25.091 20.376 30.707 ;
     RECT  26.784 30.757 26.808 30.805 ;
     RECT  28.176 29.269 29.712 30.851 ;
     RECT  25.872 30.805 26.808 30.899 ;
     RECT  28.896 30.851 29.712 30.899 ;
     RECT  38.16 30.275 38.184 31.285 ;
     RECT  23.856 24.035 24.312 31.333 ;
     RECT  25.872 30.899 25.896 31.333 ;
     RECT  40.08 30.181 41.016 31.379 ;
     RECT  40.08 31.379 40.512 31.427 ;
     RECT  21.648 30.181 21.672 31.523 ;
     RECT  0.144 31.429 0.168 31.619 ;
     RECT  7.8 28.979 8.112 31.765 ;
     RECT  38.16 31.285 38.664 31.765 ;
     RECT  38.16 31.765 38.76 31.813 ;
     RECT  4.8 30.659 4.824 31.861 ;
     RECT  15.36 31.429 15.384 31.861 ;
     RECT  16.944 28.933 16.968 31.861 ;
     RECT  4.56 31.861 4.824 31.909 ;
     RECT  13.2 28.547 13.512 32.053 ;
     RECT  4.56 31.909 5.544 32.099 ;
     RECT  6.864 31.765 8.112 32.099 ;
     RECT  38.16 31.813 38.856 32.149 ;
     RECT  7.104 32.099 8.112 32.245 ;
     RECT  21.072 32.197 21.096 32.387 ;
     RECT  27.312 31.333 27.336 32.435 ;
     RECT  15.36 31.861 16.968 32.437 ;
     RECT  18.6 23.075 18.912 32.437 ;
     RECT  7.104 32.245 8.568 32.483 ;
     RECT  23.856 31.333 25.896 32.483 ;
     RECT  13.2 32.053 14.232 32.531 ;
     RECT  15.36 32.437 18.912 32.531 ;
     RECT  4.56 32.099 4.824 32.963 ;
     RECT  4.656 32.963 4.824 33.059 ;
     RECT  7.104 32.483 8.112 33.155 ;
     RECT  15.984 32.531 18.912 33.635 ;
     RECT  7.8 33.155 8.112 33.925 ;
     RECT  37.872 32.149 38.856 33.925 ;
     RECT  34.8 27.875 35.112 34.165 ;
     RECT  16.944 33.635 18.912 34.259 ;
     RECT  37.872 33.925 39.144 34.499 ;
     RECT  20.592 33.493 20.616 34.549 ;
     RECT  7.8 33.925 8.232 34.595 ;
     RECT  20.592 34.549 21.24 34.739 ;
     RECT  34.224 34.165 35.112 34.741 ;
     RECT  34.224 34.741 35.688 35.173 ;
     RECT  16.944 34.259 16.968 35.269 ;
     RECT  18.6 34.259 18.912 35.269 ;
     RECT  15.888 34.357 15.912 35.459 ;
     RECT  34.128 35.173 35.688 35.459 ;
     RECT  0.144 35.509 0.168 35.795 ;
     RECT  37.872 34.499 37.896 35.939 ;
     RECT  39.12 34.499 39.144 35.939 ;
     RECT  7.8 34.595 8.112 35.941 ;
     RECT  20.592 34.739 20.616 35.987 ;
     RECT  34.128 35.459 35.112 35.987 ;
     RECT  7.8 35.941 8.952 35.989 ;
     RECT  16.944 35.269 18.912 36.035 ;
     RECT  4.8 33.059 4.824 36.133 ;
     RECT  4.56 36.133 4.824 36.179 ;
     RECT  29.4 30.899 29.712 36.421 ;
     RECT  16.944 36.035 16.968 36.517 ;
     RECT  16.848 36.517 16.968 36.563 ;
     RECT  16.848 36.563 16.872 36.803 ;
     RECT  38.832 36.373 38.856 36.947 ;
     RECT  23.856 32.483 24.312 36.949 ;
     RECT  23.856 36.949 24.504 37.139 ;
     RECT  2.4 26.099 2.712 37.333 ;
     RECT  25.872 32.483 25.896 37.573 ;
     RECT  31.248 36.997 31.272 37.573 ;
     RECT  2.4 37.333 2.904 37.619 ;
     RECT  25.68 37.573 25.896 37.619 ;
     RECT  29.4 36.421 30.216 37.619 ;
     RECT  38.16 36.997 38.184 37.619 ;
     RECT  25.68 37.619 25.704 38.149 ;
     RECT  7.8 35.989 9.096 38.243 ;
     RECT  29.4 37.619 29.712 38.725 ;
     RECT  31.248 37.573 31.464 38.725 ;
     RECT  25.632 38.149 25.704 38.749 ;
     RECT  4.56 36.179 4.584 38.819 ;
     RECT  25.632 38.749 25.656 39.011 ;
     RECT  4.464 38.821 4.488 39.155 ;
     RECT  29.4 38.725 31.464 39.251 ;
     RECT  2.4 37.619 2.712 39.253 ;
     RECT  20.496 37.621 20.52 39.299 ;
     RECT  23.856 37.139 24.312 39.781 ;
     RECT  31.248 39.251 31.464 40.453 ;
     RECT  2.4 39.253 3.336 40.499 ;
     RECT  31.248 40.453 32.808 40.741 ;
     RECT  31.248 40.741 33.192 40.885 ;
     RECT  29.4 39.251 29.712 40.933 ;
     RECT  31.056 40.885 33.192 40.933 ;
     RECT  23.664 39.781 24.312 40.981 ;
     RECT  2.4 40.499 2.712 41.049 ;
     RECT  7.8 38.243 8.112 41.049 ;
     RECT  13.2 32.531 13.512 41.049 ;
     RECT  18.6 36.035 18.912 41.049 ;
     RECT  23.568 40.981 24.312 41.049 ;
     RECT  34.8 35.987 35.112 41.049 ;
     RECT  40.2 31.427 40.512 41.049 ;
     RECT  2.4 41.049 2.52 41.063 ;
     RECT  7.8 41.049 7.92 41.063 ;
     RECT  13.2 41.049 13.32 41.063 ;
     RECT  18.6 41.049 18.72 41.063 ;
     RECT  23.568 41.049 24.12 41.063 ;
     RECT  29.4 40.933 33.192 41.063 ;
     RECT  34.8 41.049 34.92 41.063 ;
     RECT  40.2 41.049 40.32 41.063 ;
     RECT  23.568 41.063 23.976 43.152 ;
     RECT  30.192 41.063 33.192 43.152 ;
  END
END ot_qfd_kv_landing_ecc
END LIBRARY
